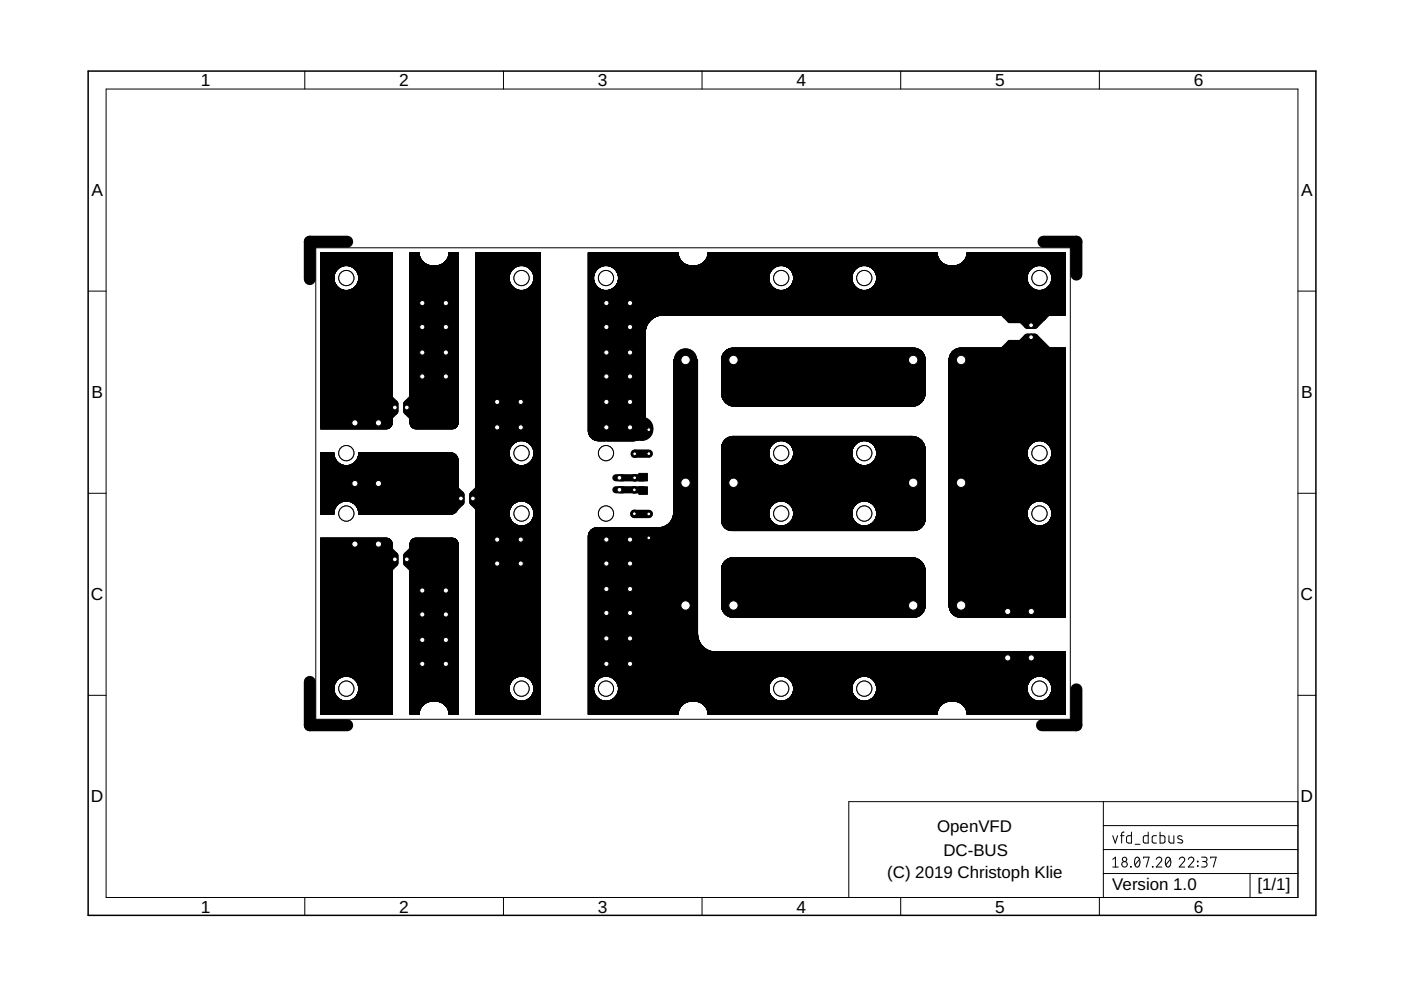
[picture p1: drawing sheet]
<svg xmlns="http://www.w3.org/2000/svg" width="297mm" height="210mm" viewBox="0 0 297 210" stroke-linecap="round" stroke-linejoin="round" font-family="sans-serif">
<defs><g id="words">
<g font-size="3.7">
<text x="42.5" y="18.3">1</text>
<text x="84.7" y="18.3">2</text>
<text x="126.8" y="18.3">3</text>
<text x="168.9" y="18.3">4</text>
<text x="211" y="18.3">5</text>
<text x="253.1" y="18.3">6</text>
<text x="19.4" y="41.6">A</text>
<text x="275.9" y="41.6">A</text>
<text x="19.4" y="84.4">B</text>
<text x="275.9" y="84.4">B</text>
<text x="19.3" y="127.3">C</text>
<text x="275.8" y="127.3">C</text>
<text x="19.3" y="170.1">D</text>
<text x="275.8" y="170.1">D</text>
<text x="42.5" y="193.5">1</text>
<text x="84.7" y="193.5">2</text>
<text x="126.8" y="193.5">3</text>
<text x="168.9" y="193.5">4</text>
<text x="211" y="193.5">5</text>
<text x="253.1" y="193.5">6</text>
</g>
<g font-size="3.6">
<text x="198.7" y="176.3">OpenVFD</text>
<text x="200" y="181.4">DC-BUS</text>
<text x="188.1" y="186.2">(C) 2019 Christoph Klie</text>
<text x="235.8" y="188.7">Version 1.0</text>
<text x="266.6" y="188.7">[1/1]</text>
</g>
</g></defs>
<g fill="none" stroke="#000" stroke-width=".51">
<circle cx="73.4" cy="58.9" r=".76"/>
<circle cx="110.6" cy="58.9" r=".76"/>
<circle cx="128.5" cy="58.9" r=".76"/>
<circle cx="165.6" cy="58.9" r=".76"/>
<circle cx="183.2" cy="58.9" r=".76"/>
<circle cx="220.4" cy="58.9" r=".76"/>
<circle cx="73.4" cy="96.1" r=".76"/>
<circle cx="110.6" cy="96.1" r=".76"/>
<circle cx="128.5" cy="96.1" r=".76"/>
<circle cx="165.6" cy="96.1" r=".76"/>
<circle cx="183.2" cy="96.1" r=".76"/>
<circle cx="220.4" cy="96.1" r=".76"/>
<circle cx="73.4" cy="108.9" r=".76"/>
<circle cx="110.6" cy="108.9" r=".76"/>
<circle cx="128.5" cy="108.9" r=".76"/>
<circle cx="165.6" cy="108.9" r=".76"/>
<circle cx="183.2" cy="108.9" r=".76"/>
<circle cx="220.4" cy="108.9" r=".76"/>
<circle cx="73.4" cy="146" r=".76"/>
<circle cx="110.6" cy="146" r=".76"/>
<circle cx="128.5" cy="146" r=".76"/>
<circle cx="165.6" cy="146" r=".76"/>
<circle cx="183.2" cy="146" r=".76"/>
<circle cx="220.4" cy="146" r=".76"/>
</g>
<path d="M213.9 72.2h3.2v1.8h-3.2zM213.9 66.6h3.2v1.8h-3.2zM81.3 81.7h1.9v3.2h-1.9zM86.9 81.7h1.9v3.2h-1.9zM95.3 100.9h1.8v3.2h-1.8zM100.9 100.9h1.8v3.2h-1.8zM135.4 100.4h1.9v1.6h-1.9zM135.4 103.2h1.9v1.6h-1.9zM81.3 120.1h1.9v3.2h-1.9zM86.9 120.1h1.9v3.2h-1.9z" fill="#000" stroke="#000" stroke-width=".21"/>
<path d="M133.3 64.3l.3 .2v26.1h-5v-26.3h75.2M145.4 76.3v59.7l-4.8 4.8M155.5 76.3h38.1M203.8 76.3v52.1h19M155.5 102.4h38.1M155.5 128.4h38.1M133.3 140.8h83.5M217.8 140.8h5" fill="none" stroke="#000" stroke-width="5"/>
<g fill="none" stroke="#000" stroke-width=".21">
<path d="M68 60h3M68 59.9l3 .1M68 59.9h3M68 59.8h3M68 59.8h2.9M68 59.7l2.9 .1M68 59.7h2.9M68 59.6h2.9M68 59.5h2.9M68 59.5h2.8M68 59.4h2.8M68 59.3h2.8"/>
<path d="M68 59.2h2.8M68 59.1h2.8M68 59h2.8M68 58.9h2.8M68 58.8h2.8M68 58.7h2.8M68 58.6h2.8M68 58.5h2.8M68 58.4h2.8M68 58.2h2.9M68 58.1h2.9M68 58h3"/>
<path d="M68 57.6h3.2M68 57.4h3.2M68 57.3h3.3M68 56.3h15.1M68 56.2h15.1M68 56.1h15.1M68 56h15.1M68 55.9h15.1M68 55.8h15.1M68 55.7h15.1M68 55.6h15.1M68 55.5h15.1"/>
<path d="M68 55.4h15.1M68 55.3h15.1M68 55.2h15.1M68 55.1h15.1M68 55h15.1M68 54.9h15.1M68 54.8h15.1M68 54.7h15.1M68 54.6h15.1M68 54.5h15.1M68 54.4h15.1M68 54.3h15.1"/>
<path d="M68 54.2h15.1M68 54.1h15.1M68 54h15.1M68 53.9h15.1M68 53.8h15.1M68 53.7h15.1M68 53.6h15.1M70.8 58.6v.7M70.8 59.3l.2 .7M70.8 58.4l-2.8 .1M70.9 58.3l-2.9 .1M70.9 58.3h-2.9"/>
<path d="M70.9 58.1l-2.9 .1M71 57.9l-.2 .7M71 60l.3 .6M71 58h-3M71 57.9h-3M71.1 57.8h-3.1M71.1 57.7h-3.1M71.2 57.6h-3.2M71.2 57.5h-3.2M71.3 57.4h-3.3M71.3 57.3l-.3 .6M71.4 57.3h-3.4"/>
<path d="M71.4 57.2l-3.4 .1M71.5 57.2h-3.5M71.5 57.1h-3.5M71.6 57.1h-3.6M71.6 57h-3.6M71.7 57h-3.7M71.7 56.9h-3.7M71.8 56.9h-3.8M71.8 56.9l-.5 .4M71.9 56.8h-3.9M72 56.7l-4 .1M72.1 56.7h-4.1"/>
<path d="M72.2 56.6l-4.2 .1M72.2 56.6h-4.2M72.3 56.5l-4.3 .1M72.4 56.5h-4.4M72.7 56.4l-4.7 .1M72.9 56.4h-4.9M73.1 56.3l-1.3 .6M73.8 56.3l.6 .2M74 56.4h9.1M74.2 56.4h8.9M74.4 56.5h8.7M74.4 56.5l.6 .4"/>
<path d="M74.5 56.5h8.6M74.6 56.6h8.5M74.7 56.6h8.4M74.8 56.7h8.3M74.9 56.7h8.2M75 56.8h8.1M75 56.9l.5 .4M75.1 56.9h8M75.1 57h8M75.2 57h7.9M75.3 57.1h7.8M75.4 57.2h7.7"/>
<path d="M75.5 57.3h7.6M75.5 57.3l.6 1.3M75.6 57.4h7.5M75.6 57.5h7.5M75.6 57.6h7.5M75.7 57.6h7.4M75.7 57.7h7.4M75.8 57.8h7.3M75.8 57.9h7.3M75.9 60h7.2M75.9 57.9h7.2M75.9 59.9h7.2"/>
<path d="M75.9 58h7.2M75.9 59.8h7.2M75.9 58.1h7.2M75.9 59.7h7.2M75.9 58.2h7.2M76 59.6h7.1M76 58.3h7.1M76 59.5h7.1M76 59.4h7.1M76 58.4h7.1M76 58.5h7.1M76.1 58.6v.7"/>
<path d="M76.1 59.3l-.6 1.3M76.1 59.3h7M76.1 59.2h7M76.1 59.1h7M76.1 59h7M76.1 58.9h7M76.1 58.8h7M76.1 58.7h7M76.1 58.6h7M83.1 56.3l-15.1 .1M87 56.3h10.1M87 60h10.1"/>
<path d="M87 59.9h10.1M87 59.8h10.1M87 59.7h10.1M87 59.6h10.1M87 59.5h10.1M87 59.4h10.1M87 59.3h10.1M87 59.2h10.1M87 59.1h10.1M87 59h10.1M87 58.9h10.1M87 58.8h10.1"/>
<path d="M87 58.7h10.1M87 58.6h10.1M87 58.5h10.1M87 58.4h10.1M87 58.3h10.1M87 58.2h10.1M87 58.1h10.1M87 58h10.1M87 57.9h10.1M87 57.8h10.1M87 57.7h10.1M87 57.6h10.1"/>
<path d="M87 57.5h10.1M87 57.4h10.1M87 57.3h10.1M87 57.2h10.1M87 57.1h10.1M87 57h10.1M87 56.9h10.1M87 56.8h10.1M87 56.7h10.1M87 56.6h10.1M87 56.5h10.1M87 56.4h10.1"/>
<path d="M87 56.3h4.2M87 56.2l4 .1M87 56.2h3.8M87 56.1l3.7 .1M87 56.1h3.5M87 56h3.4M87 56h3.3M87 55.9h3.3M87 55.9h3.1M87 55.8h3.1M87 55.8h3M87 55.7h2.9"/>
<path d="M87 55.6l2.9 .1M87 55.6h2.8M87 55.5l2.7 .1M87 55.5h2.7M87 55.4l2.6 .1M87 55.4h2.6M87 55.3l2.5 .1M87 55.3h2.5M87 55.2h2.5M87 55.2h2.4M87 55.1h2.4M87 55.1h2.3"/>
<path d="M87 55h2.3l.2 .4M87 54.9l2.3 .1M87 54.9h2.2M87 54.8l2.2 .1M87 54.8h2.2M87 54.7l2.2 .1M87 54.6l2.1 .1M87 54.6h2.1M87 54.5h2M87 54.4h2M87 54.3l2 .1M87 54.3h1.9"/>
<path d="M87 54.2h1.9M87 54.1h1.9M87 54h1.9M87 53.9h1.9M87 53.8h1.9M87 53.7h1.9M87 53.7h1.8M87 53.6h1.8M88.9 53.9l-.1-.3h-1.8v36.1M88.9 53.9h.1M88.9 53.9v.4M88.9 54.3h.1"/>
<path d="M88.9 54.3l.2 .4M89.1 54.7h-2.1M89.1 54.7h.1M89.1 54.7l.2 .3M89.3 55v.1M89.3 55h.1M89.5 55.4l.4 .3M89.5 55.4h.1M89.8 55.6l.3 .3M90.1 55.9h.1M90.2 55.9l.3 .2M90.5 56.1h.1"/>
<path d="M90.5 56.1l.4 .1M90.9 56.2v.1M90.9 56.2l.8 .2M92.3 56.3l.1 .1M92.4 56.3v.1M92.8 56.3h-.4M92.8 56.3h.1M92.8 56.3h4.3M93 56.3h4.1M93.2 56.2h3.9M93.3 56.2h3.8M93.5 56.1h3.6"/>
<path d="M93.5 56.1l-.7 .2M93.5 56.1h.1M93.6 56h3.5M93.7 56h3.4M93.8 55.9h3.3M93.9 55.9h3.2M93.9 55.9l-.3 .2M94 55.8h3.1M94.1 55.7h3M94.2 55.7h2.9M94.2 55.6l-.3 .3M94.2 55.6l.1 .1"/>
<path d="M94.3 55.6h2.8M94.4 55.5h2.7M94.5 55.4h2.6M94.5 55.4h.1M94.5 55.3h2.6M94.5 55.4l-.3 .2M94.6 55.3h2.5M94.6 55.2h2.5M94.7 55.1h2.4M94.8 55h2.3M94.8 55l-.3 .4M94.8 55v.1"/>
<path d="M94.8 55h.1M94.8 54.9h2.3M94.9 54.8h2.2M94.9 54.7h2.2M95 54.7h.1M95 54.6h2.1M95 54.5h2.1M95.1 54.4h2M95.1 54.3h2M95.1 54.3l-.1 .4M95.1 54.2h2M95.1 54.1h2"/>
<path d="M95.2 54h1.9M95.2 53.9h1.9M95.2 53.9l-.1 .4M95.2 53.9v-.3h1.9v36.1M95.2 53.8h1.9M95.2 53.7h1.9M95.2 53.6h1.9M95.2 53.9h.1M97.1 54.7h-2.1l-.2 .3M100.9 53.6h13.7v97.9h-13.7zM100.9 60h7.2M100.9 59.9h7.2"/>
<path d="M100.9 59.8l7.2 .1M100.9 59.8h7.2M100.9 59.7h7.2M100.9 59.6h7.1M100.9 59.5h7.1M100.9 59.4h7.1M100.9 59.3h7M100.9 59.2h7M100.9 59.1h7M100.9 59h7M100.9 58.9h7M100.9 58.8h7"/>
<path d="M100.9 58.7h7M100.9 58.6h7M100.9 58.5h7M100.9 58.4h7.1M100.9 58.3h7.1M100.9 58.2h7.1M100.9 58.1h7.2M100.9 58h7.2M100.9 57.9h7.2M100.9 57.9h7.3M100.9 57.7h7.4M100.9 57.6h7.4"/>
<path d="M100.9 57.2h7.7M100.9 56.9h8M100.9 56.3h13.7M100.9 56.2h13.7M100.9 56.1h13.7M100.9 56h13.7M100.9 55.9h13.7M100.9 55.8h13.7M100.9 55.7h13.7M100.9 55.6h13.7M100.9 55.5h13.7M100.9 55.4h13.7"/>
<path d="M100.9 55.3h13.7M100.9 55.2h13.7M100.9 55.1h13.7M100.9 55h13.7M100.9 54.9h13.7M100.9 54.8h13.7M100.9 54.7h13.7M100.9 54.6h13.7M100.9 54.5h13.7M100.9 54.4h13.7M100.9 54.3h13.7M100.9 54.2h13.7"/>
<path d="M100.9 54.1h13.7M100.9 54h13.7M100.9 53.9h13.7M100.9 53.8h13.7M100.9 53.7h13.7M100.9 53.6h13.7M107.9 58.6l.2 1.4M108 58.5h-7.1M108 58.3l-7.1 .1M108.1 58.2h-7.2M108.1 58l-7.2 .1M108.1 57.9l-.2 .7"/>
<path d="M108.1 60l.4 .6M108.2 57.8h-7.3M108.2 57.7h-7.3M108.3 57.6h-7.4M108.4 57.5h-7.5M108.4 57.4l-7.5 .1M108.4 57.4h-7.5M108.5 57.3l-7.6 .1M108.5 57.3l-.4 .6M108.5 57.3h-7.6M108.6 57.2h-7.7M108.7 57.1h-7.8"/>
<path d="M108.8 57h-7.9M108.9 56.9h-8M108.9 56.9l-.4 .4M109 56.8h-8.1M109.1 56.7l-8.2 .1M109.2 56.7h-8.3M109.3 56.6l-8.4 .1M109.4 56.6h-8.5M109.5 56.5l-8.6 .1M109.6 56.5h-8.7M109.6 56.5l-.7 .4M109.8 56.4l-8.9 .1"/>
<path d="M110 56.4h-9.1M110.2 56.3l-.6 .2M110.9 56.3l.7 .2M111.1 56.4h3.5M111.3 56.4h3.3M111.6 56.5h3M111.6 56.5l.6 .4M111.8 56.6h2.8M111.9 56.7h2.7M112 56.7h2.6M112.1 56.8h2.5M112.2 56.9h2.4"/>
<path d="M112.2 56.9l.5 .4M112.3 57h2.3M112.4 57h2.2M112.4 57.1h2.2M112.5 57.1h2.1M112.5 57.2h2.1M112.6 57.2h2M112.6 57.3h2M112.7 57.3h1.9M112.7 57.3l.3 .6M112.7 57.4h1.9M112.8 57.5h1.8"/>
<path d="M112.8 57.6h1.8M112.9 57.7h1.7M112.9 57.8h1.7M113 57.9h1.6M113 59.9h1.6M113 57.9l.2 .7M113 60l-.3 .6M113 58h1.6M113.1 59.8h1.5M113.1 58.1h1.5M113.1 59.7h1.5M113.1 59.6h1.5"/>
<path d="M113.1 58.2h1.5M113.1 58.3h1.5M113.1 59.5h1.5M113.1 58.4h1.5M113.2 59.4h1.4M113.2 58.4h1.4M113.2 59.3h1.4M113.2 58.5h1.4M113.2 59.2h1.4M113.2 59.1h1.4M113.2 59h1.4M113.2 58.9h1.4"/>
<path d="M113.2 58.8h1.4M113.2 58.7h1.4M113.2 58.6h1.4M113.2 58.6l-.2 1.4M114.6 56.3l-13.7 .1M124.7 53.8l19.1 .1-.1-.3h-19v37.6M124.7 60h1.4M124.7 59.9h1.3M124.7 59.8h1.3M124.7 59.7h1.3M124.7 59.6h1.3M124.7 59.6h1.2"/>
<path d="M124.7 59.5h1.2M124.7 59.4h1.2M124.7 59.3h1.2M124.7 59.2h1.2M124.7 59.1h1.2M124.7 59h1.2M124.7 58.9h1.2M124.7 58.8h1.2M124.7 58.7h1.2M124.7 58.6h1.2M124.7 58.5h1.2M124.7 58.4h1.2"/>
<path d="M124.7 58.3h1.2M124.7 58.2h1.3M124.7 58.1h1.3M124.7 58h1.3M124.7 57.9h1.4M124.7 57.8h1.4M124.7 57.2h1.8M124.7 56.9h2.1M124.7 56.3h21.4M124.7 56.2l21.2 .1M124.7 56.2h21M124.7 56.1l20.9 .1"/>
<path d="M124.7 56.1h20.8l.3 .1M124.7 56h20.7M124.7 56h20.5M124.7 55.9h20.5M124.7 55.9h20.4M124.7 55.8h20.3M124.7 55.8h20.2M124.7 55.7h20.1M124.7 55.6h20.1M124.7 55.6h20M124.7 55.5l20 .1M124.7 55.5h19.9"/>
<path d="M124.7 55.4l19.8 .1M124.7 55.4h19.8M124.7 55.3h19.7M124.7 55.2h19.7M124.7 55.2h19.6M124.7 55.1h19.6M124.7 55h19.5M124.7 54.9l19.5 .1M124.7 54.9h19.4M124.7 54.8l19.4 .1M124.7 54.8h19.4M124.7 54.7l19.4 .1"/>
<path d="M124.7 54.6l19.3 .1M124.7 54.6h19.3M124.7 54.5l19.3 .1M124.7 54.5h19.3M124.7 54.4h19.2M124.7 54.3h19.2M124.7 54.2h19.1M124.7 54.1h19.1M124.7 54l19.1 .1M124.7 54h19.1M124.7 53.9l19.1 .1M124.7 53.9h19.1"/>
<path d="M124.7 53.8h19.1M124.7 53.7h19.1M124.7 53.6h19.1M125.9 58.6l.1 1.4M125.9 58.5l-1.2 .1M125.9 58.4h-1.2M125.9 58.3l-1.2 .1M126 58.2l-1.3 .1M126 58.1h-1.3M126 58h-1.3M126 57.9l-1.3 .1M126 57.9l-.1 .7"/>
<path d="M126 60l.4 .6M126.1 57.8h-1.4M126.2 57.7h-1.5M126.2 57.6h-1.5M126.3 57.6h-1.6M126.3 57.5h-1.6M126.3 57.4l-1.6 .1M126.4 57.4h-1.7M126.4 57.3l-1.7 .1M126.4 57.3l-.4 .6M126.4 57.3h-1.7M126.6 57.2h-1.9"/>
<path d="M126.6 57.1h-1.9M126.7 57.1h-2M126.7 57h-2M126.8 57h-2.1M126.9 56.9h-2.2M126.9 56.9l-.5 .4M126.9 56.8h-2.2M127 56.7l-2.3 .1M127.1 56.7h-2.4M127.2 56.6l-2.5 .1M127.3 56.6h-2.6M127.4 56.5l-2.7 .1"/>
<path d="M127.5 56.5l-.6 .4M127.5 56.5h-2.8M127.7 56.4l-3 .1M127.9 56.4h-3.2M128.1 56.3l-.6 .2M128.8 56.3l.7 .2M129.1 56.4h36M129.3 56.4h35.6M129.5 56.5h35.1M129.5 56.5l.6 .4M129.6 56.5h34.9M129.7 56.6h34.7"/>
<path d="M129.8 56.6h34.6M129.9 56.7h34.4M129.9 56.7h34.3M130 56.8h34.1M130.1 56.9h33.9M130.1 56.9l.5 .4M130.2 56.9h33.8M130.2 57h33.7M130.3 57h33.6M130.3 57.1h33.5M130.4 57.1h33.3M130.4 57.2h33.3"/>
<path d="M130.5 57.2h33.1M130.5 57.3h33.1M130.6 57.3h32.9M130.6 57.3l.3 .6M130.6 57.4h32.9M130.7 57.5h32.7M130.7 57.6h32.7M130.8 57.7h32.5M130.9 57.9h32.3M130.9 60h32.3M130.9 59.9l32.3 .1M130.9 57.9l.2 .7"/>
<path d="M130.9 60l-.3 .6M131 59.9h32.2M131 58h32.2M131 59.8h32.1M131 58.1h32.1M131 59.7l32.1 .1M131 59.7h32.1M131 58.2h32.1M131 59.6h32.1M131 59.5h32.1M131 58.3h32.1M131.1 59.5h31.9"/>
<path d="M131.1 58.4h31.9M131.1 59.4h31.9M131.1 58.5h31.9M131.1 59.3h31.9M131.1 58.6l-.2 1.4M131.1 59.2h31.9M131.1 59.1h31.9M131.1 59h31.9M131.1 58.9h31.9M131.1 58.8h31.9M131.1 58.7h31.9M131.1 58.6h31.9"/>
<path d="M143.8 53.9h.1M143.8 53.9l.1 .4M143.9 54.3h.1M143.9 54.3h-19.2M143.9 54.3l.1 .4M144 54.7h.1M144 54.7h-19.3M144 54.7l.2 .3M144.2 55h.1M144.2 55l-19.5 .1M144.2 55l.2 .4M144.4 55.4l.4 .3"/>
<path d="M144.8 55.6l.3 .3M145.1 55.9h.1M145.1 55.9l.4 .2M145.8 56.2v.1M145.8 56.2l.4 .1M146.2 56.3h.1M146.2 56.3l.5 .1M147.7 56.3h-.4M147.7 56.3h.1M147.8 56.3h53.2M147.9 56.3h53M148.2 56.2h52.4"/>
<path d="M148.3 56.2h52.2M148.4 56.1h52M148.4 56.1l-.7 .2M148.5 56.1h.1M148.5 56h51.8M148.7 56h51.5M148.7 55.9h51.4M148.8 55.9h.1M148.8 55.9l-.3 .2M148.8 55.9h51.2M148.9 55.8h51M149 55.8h50.8"/>
<path d="M149 55.7h50.8M149.1 55.7h50.6M149.1 55.6l-.3 .3M149.1 55.6l.1 .1M149.2 55.6h50.4M149.2 55.6v.1M149.3 55.5h50.2M149.4 55.4h50M149.4 55.4l-.2 .2M149.5 55.3h49.8M149.5 55.2h49.8M149.6 55.1h49.6"/>
<path d="M149.7 55h.1M149.7 55h49.4M149.7 55l-.3 .4M149.7 55v.1M149.7 54.9h49.4M149.8 54.9h49.3M149.8 54.8h49.2M149.9 54.7h.1M149.9 54.7h49M149.9 54.7l-.2 .3M149.9 54.6h49M149.9 54.5h49"/>
<path d="M150 54.4h48.8M150 54.3h.1M150 54.3h48.8M150 54.2h48.8M150 54.3l-.1 .4M150.1 54.2h48.7M150.1 54.1h48.7M150.1 54h48.6M150.1 53.9h.1M150.1 53.9v-.3h48.6v.3M150.1 53.9h48.6M150.1 53.8h48.6"/>
<path d="M150.1 53.9l-.1 .4M150.1 53.7h48.6M150.1 53.6h48.6M163 58.6l.2 1.4 .3 .6M163 58.5l-31.9 .1M163.1 58.3h-32.1M163.1 58.2l-32.1 .1M163.2 58h-32.2M163.3 57.8h-32.4M163.3 57.7h-32.5M163.5 57.4l-32.8 .1M163.5 57.3l-.5 1.3"/>
<path d="M164 56.9l-.5 .4M164.6 56.5l-.6 .4M165.3 56.3l-.7 .2M166 56.3l.6 .2M166.2 56.4h16.5M166.4 56.4h16.1M166.6 56.5h15.6M166.6 56.5l1.1 .8M166.7 56.5h15.5M166.8 56.6h15.3M166.9 56.6h15.1M167 56.7h14.9"/>
<path d="M167.1 56.7h14.7M167.2 56.8h14.5M167.3 56.9h14.3M167.3 57h14.2M167.4 57h14.1M167.5 57.1h13.9M167.5 57.1h13.8M167.6 57.2h13.7M167.7 57.3h13.5M167.7 57.3h13.4M167.7 57.3l.4 .6M167.8 57.4h13.3"/>
<path d="M167.8 57.5h13.3M167.9 57.6h13.1M167.9 57.7h13.1M167.9 57.7h13M168 57.8h12.9M168 57.9h12.8M168.1 60h12.7M168.1 57.9h12.7M168.1 59.9h12.7M168.1 58h12.7M168.1 57.9l.2 .7M168.1 60l-.4 .6"/>
<path d="M168.1 59.8h12.7M168.1 59.8h12.6M168.1 58.1h12.6M168.1 59.7h12.6M168.1 58.2h12.6M168.2 59.6h12.5M168.2 58.3h12.5M168.2 59.5h12.5M168.2 59.4h12.5M168.2 58.4h12.5M168.2 59.4h12.4M168.2 58.5h12.4"/>
<path d="M168.3 58.6v.7M168.3 59.3h12.3M168.3 59.2h12.3M168.3 59.1h12.3M168.3 59h12.3M168.3 58.9h12.3M168.3 58.8h12.3M168.3 58.7h12.3M168.3 58.6h12.3M168.3 59.3l-.2 .7M180.6 58.6v.7M180.6 59.3l.2 .7"/>
<path d="M180.7 58.4h-12.5M180.8 58.1h-12.7M180.8 57.9l-.2 .7M180.8 60l.3 .6M181.1 57.4l-13.3 .1M181.1 57.3l-.3 .6M181.6 56.9l-.5 .4M182.2 56.5l-.6 .4M182.9 56.3l-.7 .2M183.6 56.3l.7 .2M183.8 56.4h36M184 56.4h35.6"/>
<path d="M184.3 56.5h35.1M184.3 56.5l1 .8M184.3 56.5h35M184.4 56.6h34.8M184.5 56.6h34.6M184.6 56.7h34.4M184.7 56.7h34.2M184.8 56.8h34M184.9 56.9h33.9M184.9 56.9h33.8M185 57h33.7M185 57h33.6"/>
<path d="M185.2 57.2h33.2M185.3 57.2h33.1M185.3 57.3h33M185.3 57.3l.4 .6M185.4 57.4h32.8M185.4 57.5h32.8M185.5 57.6h32.7M185.5 57.6h32.6M185.5 57.7h32.6M185.6 57.7h32.5M185.6 57.8h32.4M185.7 57.9h32.3"/>
<path d="M185.7 60h32.2M185.7 59.9h32.2M185.7 58h32.2M185.7 57.9l.2 .7M185.7 60l-.4 .6M185.7 59.8h32.2M185.7 58.1h32.2M185.8 59.7h32.1M185.8 58.2h32.1M185.8 59.6h32M185.8 58.3h32M185.8 58.2h32"/>
<path d="M185.8 59.5h32M185.8 59.4h32M185.8 58.4h32M185.8 58.5h32M185.9 58.6v.7M185.9 59.3h31.9M185.9 59.2h31.9M185.9 59.1h31.9M185.9 59h31.9M185.9 58.9h31.9M185.9 58.8h31.9M185.9 58.7h31.9"/>
<path d="M185.9 58.6h31.9M185.9 58.5h31.9M185.9 59.3l-.2 .7M198.7 53.9h.1M198.7 53.9l.1 .4M198.8 54.3h.1M198.8 54.3h-48.8M198.8 54.3l.1 .4M198.9 54.7h.1M198.9 54.7h-49M198.9 54.7l.2 .3M199.1 55h.1"/>
<path d="M199.1 55l.1 .1M199.1 55l.3 .4M199.4 55.4l.3 .3M199.4 55.4h-50M199.4 55.4h.1M199.7 55.6l.3 .3M200 55.9h.1M200 55.9l.3 .2M200.3 56.1h.1M200.4 56.1l.3 .1M200.7 56.2l.1 .1M200.7 56.2l.9 .2"/>
<path d="M202.2 56.3v.1M202.6 56.3h-.4M202.6 56.3h.1M202.7 56.3h23.2M202.9 56.3h23M203 56.2l-.4 .1M203 56.2v.1M203.1 56.2h22.8M203.2 56.2h22.7M203.3 56.1h22.6M203.4 56.1l-.4 .1M203.4 56.1h.1"/>
<path d="M203.5 56h22.4M203.6 56h22.3M203.6 55.9h22.3M203.7 55.9l-.3 .2M203.7 55.9h.1M203.8 55.9h22.1M203.8 55.9h.1M203.8 55.8h22.1M203.9 55.8h22M204 55.7h21.9M204.1 55.6l-.3 .3M204.1 55.6v.1"/>
<path d="M204.1 55.6h21.8M204.2 55.6h21.7M204.2 55.5h21.7M204.3 55.5h21.6M204.3 55.4h21.6M204.3 55.4l-.2 .2M204.4 55.3h21.5M204.4 55.4h.1M204.4 55.2h21.5M204.5 55.2h21.4M204.5 55.1h21.4M204.6 55.1h21.3"/>
<path d="M204.6 55h21.3M204.6 55l-.2 .4M204.6 55v.1M204.6 55h.1M204.7 54.9h21.2M204.7 54.8h21.2M204.8 54.7h21.1M204.8 54.7h.1M204.8 54.7l-.2 .3M204.8 54.6h21.1M204.9 54.5h21M204.9 54.4h21"/>
<path d="M204.9 54.3h21M204.9 54.3l-.1 .4M204.9 54.3h.1M205 54.2h20.9M205 54.3h.1M205 54.1h20.9M205 54h20.9M205 53.9h20.9M205 53.9l.1-.3h20.8v13.2h-101.2M205 53.9h.1M205 53.8h20.9M205 53.7h20.9"/>
<path d="M205 53.6h20.9M205 53.9v.4M205.1 53.6h20.8M217.8 58.6v.7M217.8 59.3l.1 .7M217.9 57.9l-.1 .7M217.9 60l.4 .6M218.3 57.3l-.4 .6M218.5 57.1h-33.4M219.4 56.5l-1.1 .8M220 56.3l-.6 .2M220.7 56.3l.7 .2"/>
<path d="M221 56.4h4.9M221.1 56.4h4.8M221.4 56.5h4.5M221.4 56.5l.6 .4M221.5 56.5h4.4M221.6 56.6h4.3M221.7 56.7h4.2M221.8 56.7h4.1M221.9 56.8h4M222 56.9h3.9M222 56.9l.5 .4M222.1 56.9h3.8"/>
<path d="M222.1 57h3.8M222.2 57h3.7M222.2 57.1h3.7M222.3 57.1h3.6M222.3 57.2h3.6M222.4 57.2h3.5M222.4 57.3h3.5M222.5 57.3h3.4M222.5 57.3l.3 .6M222.5 57.4h3.4M222.6 57.5h3.3M222.6 57.6h3.3"/>
<path d="M222.7 57.7h3.2M222.7 57.8h3.2M222.8 57.8h3.1M222.8 57.9h3.1M222.8 60h3.1M222.8 59.9h3.1M222.8 58h3.1M222.8 57.9l.2 .7M222.8 60l-.3 .6M222.9 59.8h3M222.9 58.1h3M222.9 58h3"/>
<path d="M222.9 59.7h3M222.9 59.6h3M222.9 58.2h3M222.9 58.3h3M222.9 59.5h3M222.9 58.4h3M223 59.5h2.9M223 59.4h2.9M223 58.4h2.9M223 59.3h2.9M223 58.5h2.9M223 58.6v.7"/>
<path d="M223 59.2h2.9M223 59.1h2.9M223 59h2.9M223 58.9h2.9M223 58.8h2.9M223 58.7h2.9M223 58.6h2.9M223 59.3l-.2 .7M225.9 56.3l-101.2 .1M68 76.3h15.1M68 80h15.1M68 79.9h15.1"/>
<path d="M68 79.8h15.1M68 79.7h15.1M68 79.6h15.1M68 79.5h15.1M68 79.4h15.1M68 79.3h15.1M68 79.2h15.1M68 79.1h15.1M68 79h15.1M68 78.9h15.1M68 78.8h15.1M68 78.7h15.1"/>
<path d="M68 78.6h15.1M68 78.5h15.1M68 78.4h15.1M68 78.3h15.1M68 78.2h15.1M68 78.1h15.1M68 78h15.1M68 77.9h15.1M68 77.8h15.1M68 77.7h15.1M68 77.6h15.1M68 77.5h15.1"/>
<path d="M68 77.4h15.1M68 77.3h15.1M68 77.2h15.1M68 77.1h15.1M68 77h15.1M68 76.9h15.1M68 76.8h15.1M68 76.7h15.1M68 76.6h15.1M68 76.5h15.1M68 76.4h15.1M68 73.8h15.1"/>
<path d="M68 76.2h15.1M68 76.1h15.1M68 76h15.1M68 75.9h15.1M68 75.8h15.1M68 75.7h15.1M68 75.6h15.1M68 75.5h15.1M68 75.4h15.1M68 75.3h15.1M68 75.2h15.1M68 75.1h15.1"/>
<path d="M68 75h15.1M68 74.9h15.1M68 74.8h15.1M68 74.7h15.1M68 74.6h15.1M68 74.5h15.1M68 74.4h15.1M68 74.3h15.1M68 74.2h15.1M68 74.1h15.1M68 74h15.1M68 73.9h15.1"/>
<path d="M68 61.6h15.1M68 73.7h15.1M68 73.6h15.1M68 73.5h15.1M68 73.4h15.1M68 73.3h15.1M68 73.2h15.1M68 73.1h15.1M68 73h15.1M68 72.9h15.1M68 72.8h15.1M68 72.7h15.1"/>
<path d="M68 72.6h15.1M68 72.5h15.1M68 72.4h15.1M68 72.3h15.1M68 72.2h15.1M68 72.1h15.1M68 72h15.1M68 71.9h15.1M68 71.8h15.1M68 71.7h15.1M68 71.6h15.1M68 71.5h15.1"/>
<path d="M68 71.4h15.1M68 71.3h15.1M68 71.2h15.1M68 71.1h15.1M68 71h15.1M68 70.9h15.1M68 70.8h15.1M68 70.7h15.1M68 70.6h15.1M68 70.5h15.1M68 70.4h15.1M68 70.3h15.1"/>
<path d="M68 70.2h15.1M68 70.1h15.1M68 70h15.1M68 69.9h15.1M68 69.8h15.1M68 69.7h15.1M68 69.6h15.1M68 69.5h15.1M68 69.4h15.1M68 69.3h15.1M68 69.2h15.1M68 69.1h15.1"/>
<path d="M68 69h15.1M68 68.9h15.1M68 68.8h15.1M68 68.7h15.1M68 68.6h15.1M68 68.5h15.1M68 68.4h15.1M68 68.3h15.1M68 68.2h15.1M68 68.1h15.1M68 68h15.1M68 67.9h15.1"/>
<path d="M68 67.8h15.1M68 67.7h15.1M68 67.6h15.1M68 67.5h15.1M68 67.4h15.1M68 67.3h15.1M68 67.2h15.1M68 67.1h15.1M68 67h15.1M68 66.9h15.1M68 66.8h15.1M68 66.7h15.1"/>
<path d="M68 66.6h15.1M68 66.5h15.1M68 66.4h15.1M68 66.3h15.1M68 66.2h15.1M68 66.1h15.1M68 66h15.1M68 65.9h15.1M68 65.8h15.1M68 65.7h15.1M68 65.6h15.1M68 65.5h15.1"/>
<path d="M68 65.4h15.1M68 65.3h15.1M68 65.2h15.1M68 65.1h15.1M68 65h15.1M68 64.9h15.1M68 64.8h15.1M68 64.7h15.1M68 64.6h15.1M68 64.5h15.1M68 64.4h15.1M68 64.3h15.1"/>
<path d="M68 64.2h15.1M68 64.1h15.1M68 64h15.1M68 63.9h15.1M68 63.8h15.1M68 63.7h15.1M68 63.6h15.1M68 63.5h15.1M68 63.4h15.1M68 63.3h15.1M68 63.2h15.1M68 63.1h15.1"/>
<path d="M68 63h15.1M68 62.9h15.1M68 62.8h15.1M68 62.7h15.1M68 62.6h15.1M68 62.5h15.1M68 62.4h15.1M68 62.3h15.1M68 62.2h15.1M68 62.1h15.1M68 62h15.1M68 61.9h15.1"/>
<path d="M68 61.8h15.1M68 61.7h15.1M68 61.5l5 .1M68 61.5h4.8M68 61.4h4.6M68 61.4h4.5M68 61.3h4.3M68 61.2h4.2M68 61.2h4.1M68 61.1h3.9M68 61l3.9 .1M68 61h3.8"/>
<path d="M68 60.9l3.8 .1M68 60.9h3.7M68 60.8l3.6 .1M68 60.8h3.6M68 60.7l3.5 .1M68 60.7h3.5M68 60.6l3.4 .1M68 60.6h3.4M68 60.5l3.3 .1M68 60.5h3.3M68 60.4h3.2M68 60.3l3.2 .1"/>
<path d="M68 60.3h3.2M68 60.2l3.2 .1M68 60.2h3.1M68 60.1l3.1 .1M68 60.1h3.1M71.3 60.6l1.1 .8 .7 .2M73.8 61.6h9.3M74 61.5h9.1M74.3 61.4h8.8M74.4 61.4h8.7M74.5 61.3h8.6M74.6 61.3h8.5"/>
<path d="M74.7 61.2h8.4M74.8 61.2h8.3M74.9 61.1h8.2M75 61.1h8.1M75.1 61h8M75.2 60.9h7.9M75.3 60.8h7.8M75.4 60.7h7.7M75.5 60.6h7.6M75.5 60.6l-1.1 .8-.6 .2M75.6 60.5h7.5M75.6 60.4h7.5"/>
<path d="M75.7 60.3h7.4M75.7 60.2h7.4M75.8 60.2h7.3M75.8 60.1h7.3M75.8 60h7.3M87 76.3h10.1M87 80h10.1M87 79.9h10.1M87 79.8h10.1M87 79.7h10.1M87 79.6h10.1M87 79.5h10.1"/>
<path d="M87 79.4h10.1M87 79.3h10.1M87 79.2h10.1M87 79.1h10.1M87 79h10.1M87 78.9h10.1M87 78.8h10.1M87 78.7h10.1M87 78.6h10.1M87 78.5h10.1M87 78.4h10.1M87 78.3h10.1"/>
<path d="M87 78.2h10.1M87 78.1h10.1M87 78h10.1M87 77.9h10.1M87 77.8h10.1M87 77.7h10.1M87 77.6h10.1M87 77.5h10.1M87 77.4h10.1M87 77.3h10.1M87 77.2h10.1M87 77.1h10.1"/>
<path d="M87 77h10.1M87 76.9h10.1M87 76.8h10.1M87 76.7h10.1M87 76.6h10.1M87 76.5h10.1M87 76.4h10.1M87 73.8h10.1M87 76.2h10.1M87 76.1h10.1M87 76h10.1M87 75.9h10.1"/>
<path d="M87 75.8h10.1M87 75.7h10.1M87 75.6h10.1M87 75.5h10.1M87 75.4h10.1M87 75.3h10.1M87 75.2h10.1M87 75.1h10.1M87 75h10.1M87 74.9h10.1M87 74.8h10.1M87 74.7h10.1"/>
<path d="M87 74.6h10.1M87 74.5h10.1M87 74.4h10.1M87 74.3h10.1M87 74.2h10.1M87 74.1h10.1M87 74h10.1M87 73.9h10.1M87 61.6h10.1M87 73.7h10.1M87 73.6h10.1M87 73.5h10.1"/>
<path d="M87 73.4h10.1M87 73.3h10.1M87 73.2h10.1M87 73.1h10.1M87 73h10.1M87 72.9h10.1M87 72.8h10.1M87 72.7h10.1M87 72.6h10.1M87 72.5h10.1M87 72.4h10.1M87 72.3h10.1"/>
<path d="M87 72.2h10.1M87 72.1h10.1M87 72h10.1M87 71.9h10.1M87 71.8h10.1M87 71.7h10.1M87 71.6h10.1M87 71.5h10.1M87 71.4h10.1M87 71.3h10.1M87 71.2h10.1M87 71.1h10.1"/>
<path d="M87 71h10.1M87 70.9h10.1M87 70.8h10.1M87 70.7h10.1M87 70.6h10.1M87 70.5h10.1M87 70.4h10.1M87 70.3h10.1M87 70.2h10.1M87 70.1h10.1M87 70h10.1M87 69.9h10.1"/>
<path d="M87 69.8h10.1M87 69.7h10.1M87 69.6h10.1M87 69.5h10.1M87 69.4h10.1M87 69.3h10.1M87 69.2h10.1M87 69.1h10.1M87 69h10.1M87 68.9h10.1M87 68.8h10.1M87 68.7h10.1"/>
<path d="M87 68.6h10.1M87 68.5h10.1M87 68.4h10.1M87 68.3h10.1M87 68.2h10.1M87 68.1h10.1M87 68h10.1M87 67.9h10.1M87 67.8h10.1M87 67.7h10.1M87 67.6h10.1M87 67.5h10.1"/>
<path d="M87 67.4h10.1M87 67.3h10.1M87 67.2h10.1M87 67.1h10.1M87 67h10.1M87 66.9h10.1M87 66.8h10.1M87 66.7h10.1M87 66.6h10.1M87 66.5h10.1M87 66.4h10.1M87 66.3h10.1"/>
<path d="M87 66.2h10.1M87 66.1h10.1M87 66h10.1M87 65.9h10.1M87 65.8h10.1M87 65.7h10.1M87 65.6h10.1M87 65.5h10.1M87 65.4h10.1M87 65.3h10.1M87 65.2h10.1M87 65.1h10.1"/>
<path d="M87 65h10.1M87 64.9h10.1M87 64.8h10.1M87 64.7h10.1M87 64.6h10.1M87 64.5h10.1M87 64.4h10.1M87 64.3h10.1M87 64.2h10.1M87 64.1h10.1M87 64h10.1M87 63.9h10.1"/>
<path d="M87 63.8h10.1M87 63.7h10.1M87 63.6h10.1M87 63.5h10.1M87 63.4h10.1M87 63.3h10.1M87 63.2h10.1M87 63.1h10.1M87 63h10.1M87 62.9h10.1M87 62.8h10.1M87 62.7h10.1"/>
<path d="M87 62.6h10.1M87 62.5h10.1M87 62.4h10.1M87 62.3h10.1M87 62.2h10.1M87 62.1h10.1M87 62h10.1M87 61.9h10.1M87 61.8h10.1M87 61.7h10.1M87 61.5h10.1M87 61.4h10.1"/>
<path d="M87 61.3h10.1M87 61.2h10.1M87 61.1h10.1M87 61h10.1M87 60.9h10.1M87 60.8h10.1M87 60.7h10.1M87 60.6h10.1M87 60.5h10.1M87 60.4h10.1M87 60.3h10.1M87 60.2h10.1"/>
<path d="M87 60.1h10.1M100.9 76.3h13.7M100.9 80h13.7M100.9 79.9h13.7M100.9 79.8h13.7M100.9 79.7h13.7M100.9 79.6h13.7M100.9 79.5h13.7M100.9 79.4h13.7M100.9 79.3h13.7M100.9 79.2h13.7M100.9 79.1h13.7"/>
<path d="M100.9 79h13.7M100.9 78.9h13.7M100.9 78.8h13.7M100.9 78.7h13.7M100.9 78.6h13.7M100.9 78.5h13.7M100.9 78.4h13.7M100.9 78.3h13.7M100.9 78.2h13.7M100.9 78.1h13.7M100.9 78h13.7M100.9 77.9h13.7"/>
<path d="M100.9 77.8h13.7M100.9 77.7h13.7M100.9 77.6h13.7M100.9 77.5h13.7M100.9 77.4h13.7M100.9 77.3h13.7M100.9 77.2h13.7M100.9 77.1h13.7M100.9 77h13.7M100.9 76.9h13.7M100.9 76.8h13.7M100.9 76.7h13.7"/>
<path d="M100.9 76.6h13.7M100.9 76.5h13.7M100.9 76.4h13.7M100.9 73.8h13.7M100.9 76.2h13.7M100.9 76.1h13.7M100.9 76h13.7M100.9 75.9h13.7M100.9 75.8h13.7M100.9 75.7h13.7M100.9 75.6h13.7M100.9 75.5h13.7"/>
<path d="M100.9 75.4h13.7M100.9 75.3h13.7M100.9 75.2h13.7M100.9 75.1h13.7M100.9 75h13.7M100.9 74.9h13.7M100.9 74.8h13.7M100.9 74.7h13.7M100.9 74.6h13.7M100.9 74.5h13.7M100.9 74.4h13.7M100.9 74.3h13.7"/>
<path d="M100.9 74.2h13.7M100.9 74.1h13.7M100.9 74h13.7M100.9 73.9h13.7M100.9 61.6h13.7M100.9 73.7h13.7M100.9 73.6h13.7M100.9 73.5h13.7M100.9 73.4h13.7M100.9 73.3h13.7M100.9 73.2h13.7M100.9 73.1h13.7"/>
<path d="M100.9 73h13.7M100.9 72.9h13.7M100.9 72.8h13.7M100.9 72.7h13.7M100.9 72.6h13.7M100.9 72.5h13.7M100.9 72.4h13.7M100.9 72.3h13.7M100.9 72.2h13.7M100.9 72.1h13.7M100.9 72h13.7M100.9 71.9h13.7"/>
<path d="M100.9 71.8h13.7M100.9 71.7h13.7M100.9 71.6h13.7M100.9 71.5h13.7M100.9 71.4h13.7M100.9 71.3h13.7M100.9 71.2h13.7M100.9 71.1h13.7M100.9 71h13.7M100.9 70.9h13.7M100.9 70.8h13.7M100.9 70.7h13.7"/>
<path d="M100.9 70.6h13.7M100.9 70.5h13.7M100.9 70.4h13.7M100.9 70.3h13.7M100.9 70.2h13.7M100.9 70.1h13.7M100.9 70h13.7M100.9 69.9h13.7M100.9 69.8h13.7M100.9 69.7h13.7M100.9 69.6h13.7M100.9 69.5h13.7"/>
<path d="M100.9 69.4h13.7M100.9 69.3h13.7M100.9 69.2h13.7M100.9 69.1h13.7M100.9 69h13.7M100.9 68.9h13.7M100.9 68.8h13.7M100.9 68.7h13.7M100.9 68.6h13.7M100.9 68.5h13.7M100.9 68.4h13.7M100.9 68.3h13.7"/>
<path d="M100.9 68.2h13.7M100.9 68.1h13.7M100.9 68h13.7M100.9 67.9h13.7M100.9 67.8h13.7M100.9 67.7h13.7M100.9 67.6h13.7M100.9 67.5h13.7M100.9 67.4h13.7M100.9 67.3h13.7M100.9 67.2h13.7M100.9 67.1h13.7"/>
<path d="M100.9 67h13.7M100.9 66.9h13.7M100.9 66.8h13.7M100.9 66.7h13.7M100.9 66.6h13.7M100.9 66.5h13.7M100.9 66.4h13.7M100.9 66.3h13.7M100.9 66.2h13.7M100.9 66.1h13.7M100.9 66h13.7M100.9 65.9h13.7"/>
<path d="M100.9 65.8h13.7M100.9 65.7h13.7M100.9 65.6h13.7M100.9 65.5h13.7M100.9 65.4h13.7M100.9 65.3h13.7M100.9 65.2h13.7M100.9 65.1h13.7M100.9 65h13.7M100.9 64.9h13.7M100.9 64.8h13.7M100.9 64.7h13.7"/>
<path d="M100.9 64.6h13.7M100.9 64.5h13.7M100.9 64.4h13.7M100.9 64.3h13.7M100.9 64.2h13.7M100.9 64.1h13.7M100.9 64h13.7M100.9 63.9h13.7M100.9 63.8h13.7M100.9 63.7h13.7M100.9 63.6h13.7M100.9 63.5h13.7"/>
<path d="M100.9 63.4h13.7M100.9 63.3h13.7M100.9 63.2h13.7M100.9 63.1h13.7M100.9 63h13.7M100.9 62.9h13.7M100.9 62.8h13.7M100.9 62.7h13.7M100.9 62.6h13.7M100.9 62.5h13.7M100.9 62.4h13.7M100.9 62.3h13.7"/>
<path d="M100.9 62.2h13.7M100.9 62.1h13.7M100.9 62h13.7M100.9 61.9h13.7M100.9 61.8h13.7M100.9 61.7h13.7M100.9 61.5l9.3 .1M100.9 61.5h9.1M100.9 61.4h8.8M100.9 61.4h8.7M100.9 61.3h8.6M100.9 61.3h8.5"/>
<path d="M100.9 61.2h8.4M100.9 61.2h8.3M100.9 61.1h8.2M100.9 61l8.1 .1M100.9 61h8M100.9 60.9l8 .1M100.9 60.9h7.9M100.9 60.8l7.9 .1M100.9 60.8h7.8M100.9 60.7l7.8 .1M100.9 60.7h7.7M100.9 60.6l7.7 .1"/>
<path d="M100.9 60.6h7.6M100.9 60.5h7.6M100.9 60.5h7.5M100.9 60.4h7.5M100.9 60.3l7.5 .1M100.9 60.3h7.4M100.9 60.2l7.4 .1M100.9 60.2h7.4M100.9 60.1l7.3 .1M100.9 60.1h7.3M100.9 60l7.3 .1M108.5 60.6l1.1 .8 .6 .2"/>
<path d="M111 61.6h3.6M111.1 61.5h3.5M111.4 61.4h3.2M111.5 61.4h3.1M111.7 61.3h2.9M111.8 61.2h2.8M111.9 61.2h2.7M112 61.1h2.6M112.1 61.1h2.5M112.2 61h2.4M112.3 60.9h2.3M112.4 60.9h2.2"/>
<path d="M112.4 60.8h2.2M112.5 60.8h2.1M112.5 60.7h2.1M112.6 60.7h2M112.6 60.6h2M112.7 60.5h1.9M112.7 60.6l-1.1 .8-.7 .2M112.8 60.4h1.8M112.8 60.3h1.8M112.9 60.2h1.7M112.9 60.1h1.7M113 60h1.6"/>
<path d="M124.7 76.3h12.1M124.7 80h12.1M124.7 79.9h12.1M124.7 79.8h12.1M124.7 79.7h12.1M124.7 79.6h12.1M124.7 79.5h12.1M124.7 79.4h12.1M124.7 79.3h12.1M124.7 79.2h12.1M124.7 79.1h12.1M124.7 79h12.1"/>
<path d="M124.7 78.9h12.1M124.7 78.8h12.1M124.7 78.7h12.1M124.7 78.6h12.1M124.7 78.5h12.1M124.7 78.4h12.1M124.7 78.3h12.1M124.7 78.2h12.1M124.7 78.1h12.1M124.7 78h12.1M124.7 77.9h12.1M124.7 77.8h12.1"/>
<path d="M124.7 77.7h12.1M124.7 77.6h12.1M124.7 77.5h12.1M124.7 77.4h12.1M124.7 77.3h12.1M124.7 77.2h12.1M124.7 77.1h12.1M124.7 77h12.1M124.7 76.9h12.1M124.7 76.8h12.1M124.7 76.7h12.1M124.7 76.6h12.1"/>
<path d="M124.7 76.5h12.1M124.7 76.4h12.1M124.7 73.8h12.1M124.7 76.2h12.1M124.7 76.1h12.1M124.7 76h12.1M124.7 75.9h12.1M124.7 75.8h12.1M124.7 75.7h12.1M124.7 75.6h12.1M124.7 75.5h12.1M124.7 75.4h12.1"/>
<path d="M124.7 75.3h12.1M124.7 75.2h12.1M124.7 75.1h12.1M124.7 75h12.1M124.7 74.9h12.1M124.7 74.8h12.1M124.7 74.7h12.1M124.7 74.6h12.1M124.7 74.5h12.1M124.7 74.4h12.1M124.7 74.3h12.1M124.7 74.2h12.1"/>
<path d="M124.7 74.1h12.1M124.7 74h12.1M124.7 73.9h12.1M124.7 61.6h101.2M124.7 73.7h12.1M124.7 73.6h12.1M124.7 73.5h12.1M124.7 73.4h12.1M124.7 73.3h12.1M124.7 73.2h12.1M124.7 73.1h12.1M124.7 73h12.1"/>
<path d="M124.7 72.9h12.1M124.7 72.8h12.1M124.7 72.7h12.1M124.7 72.6h12.1M124.7 72.5h12.1M124.7 72.4h12.1M124.7 72.3h12.1M124.7 72.2h12.1M124.7 72.1h12.1M124.7 72h12.1M124.7 71.9h12.1M124.7 71.8h12.1"/>
<path d="M124.7 71.7h12.1M124.7 71.6h12.1M124.7 71.5h12.1M124.7 71.4h12.1M124.7 71.3h12.1M124.7 71.2h12.1M124.7 71.1h12.1M124.7 71h12.1M124.7 70.9h12.1M124.7 70.8h12.1M124.7 70.7h12.1M124.7 70.6h12.1"/>
<path d="M124.7 70.5h12.1M124.7 70.4h12.1M124.7 70.3h12.1M124.7 70.2h12.1M124.7 70.1h12.1M124.7 70h12.1M124.7 69.9h12.2M124.7 69.8h12.2M124.7 69.7h12.2M124.7 69.6h12.2M124.7 69.2h12.4M124.7 69.1h12.4"/>
<path d="M124.7 69h12.4M124.7 68.5h12.8M124.7 68.4h12.8M124.7 66.7h101.2M124.7 66.6h101.2M124.7 66.5h101.2M124.7 66.4h101.2M124.7 66.3h101.2M124.7 66.2h101.2M124.7 66.1h101.2M124.7 66h101.2M124.7 65.9h101.2"/>
<path d="M124.7 65.8h101.2M124.7 65.7h101.2M124.7 65.6h101.2M124.7 65.5h101.2M124.7 65.4h101.2M124.7 65.3h101.2M124.7 65.2h101.2M124.7 65.1h101.2M124.7 65h101.2M124.7 64.9h101.2M124.7 64.8h101.2M124.7 64.7h101.2"/>
<path d="M124.7 64.6h101.2M124.7 64.5h101.2M124.7 64.4h101.2M124.7 64.3h101.2M124.7 64.2h101.2M124.7 64.1h101.2M124.7 64h101.2M124.7 63.9h101.2M124.7 63.8h101.2M124.7 63.7h101.2M124.7 63.6h101.2M124.7 63.5h101.2"/>
<path d="M124.7 63.4h101.2M124.7 63.3h101.2M124.7 63.2h101.2M124.7 63.1h101.2M124.7 63h101.2M124.7 62.9h101.2M124.7 62.8h101.2M124.7 62.7h101.2M124.7 62.6h101.2M124.7 62.5h101.2M124.7 62.4h101.2M124.7 62.3h101.2"/>
<path d="M124.7 62.2h101.2M124.7 62.1h101.2M124.7 62h101.2M124.7 61.9h101.2M124.7 61.8h101.2M124.7 61.7h101.2M124.7 61.5l3.4 .1M124.7 61.5h3.2M124.7 61.4h3M124.7 61.4h2.8M124.7 61.3h2.7M124.7 61.3h2.6"/>
<path d="M124.7 61.2h2.5M124.7 61.2h2.4M124.7 61.1h2.3M124.7 61l2.3 .1M124.7 61h2.2M124.7 60.9l2.1 .1M124.7 60.9h2M124.7 60.8l2 .1M124.7 60.8h1.9M124.7 60.7l1.9 .1M124.7 60.7h1.8M124.7 60.6l1.8 .1"/>
<path d="M124.7 60.6h1.7M124.7 60.5h1.7M124.7 60.5h1.6M124.7 60.4h1.6M124.7 60.3l1.6 .1M124.7 60.3h1.6M124.7 60.2l1.5 .1M124.7 60.2h1.5M124.7 60.1l1.5 .1M124.7 60.1h1.4M124.7 60l1.4 .1M126.4 60.6l1.1 .8 .6 .2"/>
<path d="M128.9 61.6h36.3M129.1 61.5h36M129.3 61.4h35.5M129.5 61.4h35.2M129.6 61.3h34.9M129.8 61.2h34.6M129.9 61.2h34.4M130 61.1h34.1M130.1 61h33.9M130.2 61h33.8M130.2 60.9h33.7M130.3 60.9h33.6"/>
<path d="M130.3 60.8h33.5M130.4 60.8h33.3M130.5 60.7h33.2M130.5 60.7h33.1M130.5 60.6h33.1M130.6 60.5l32.9 .1M130.6 60.6l-1.1 .8-.7 .2M130.6 60.5h32.9M130.7 60.4h32.7M130.7 60.3h32.7M130.8 60.2h32.5M130.9 60.1h32.4"/>
<path d="M136.8 70.6v20.3M136.8 70.3h-12.1M136.8 70.1v.5M136.9 69.7l-12.2 .1M136.9 69.6l-12.2 .1M136.9 69.5l-12.2 .1M136.9 69.5l-.1 .6M137 69.5h-12.3M137 69.4h-12.3M137 69.3h-12.3M137.1 69.3h-12.4M137.1 69l-.2 .5"/>
<path d="M137.2 68.9l-12.5 .1M137.2 68.9h-12.5M137.2 68.8l-12.5 .1M137.3 68.8h-12.6M137.3 68.7l-12.6 .1M137.3 68.7h-12.6M137.4 68.6l-12.7 .1M137.4 68.6h-12.7M137.4 68.5h-12.7M137.5 68.4l-12.8 .1M137.6 68.3h-12.9M137.7 68.2h-13"/>
<path d="M137.8 68.1h-13.1M137.8 68h-13.1M137.9 67.9l-13.2 .1M138 67.9h-13.3M138 67.8l-13.3 .1M138.1 67.8h-13.4M138.1 67.7l-13.4 .1M138.2 67.7h-13.5M138.3 67.6h-13.6M138.4 67.5h-13.7M138.5 67.5h-13.8M138.5 67.4h-13.8"/>
<path d="M138.5 67.4a3.5 3.5 0 0 0-1.4 1.6M138.6 67.4h-13.9M138.7 67.3h-14M138.9 67.2l-14.2 .1M138.9 67.2h-14.2M139 67.1l-.5 .3M139 67.1l-14.3 .1M139.1 67.1h-14.4M139.3 67l-14.6 .1M139.4 67h-14.7M139.7 66.9l-15 .1M139.9 66.9h-15.2"/>
<path d="M140.4 66.8l-15.7 .1M140.6 66.8l-1.6 .3M142.8 80h5.1M142.8 79.9h5.1M142.8 79.8h5.1M142.8 79.7h5.1M142.8 79.6h5.1M142.8 79.5h5.1M142.8 79.4h5.1M142.8 79.3h5.1M142.8 79.2h5.1M142.8 79.1h5.1"/>
<path d="M142.8 79h5.1M142.8 78.9h5.1M142.8 78.8h5.1M142.8 78.7h5.1M142.8 78.6h5.1M142.8 78.5h5.1M142.8 78.4h5.1M142.8 78.3h5.1M142.8 78.2h5.1M142.8 78.1h5.1M142.8 78h5.1M142.8 77.9h5.1"/>
<path d="M142.8 77.8h5.1M142.8 77.7h5.1M142.8 77.6h5.1M142.8 77.5h5.1M142.8 77.4h5.1M142.8 77.3h5.1M142.8 77.2h5.1M142.8 77.1h5.1M142.8 77h5.1M142.8 76.9h5.1M142.8 76.8h5.1M142.8 76.7h5.1"/>
<path d="M142.8 76.6h5.1M142.8 76.5h5.1M142.8 76.4h5.1M153 76.3h43.2M153 80h43.2M153 79.9h43.2M153 79.8h43.2M153 79.7h43.2M153 79.6h43.2M153 79.5h43.2M153 79.4h43.2M153 79.3h43.2"/>
<path d="M153 79.2h43.2M153 79.1h43.2M153 79h43.2M153 78.9h43.2M153 78.8h43.2M153 78.7h43.2M153 78.6h43.2M153 78.5h43.2M153 78.4h43.2M153 78.3h43.2M153 78.2h43.2M153 78.1h43.2"/>
<path d="M153 78h43.2M153 77.9h43.2M153 77.8h43.2M153 77.7h43.2M153 77.6h43.2M153 77.5h43.2M153 77.4h43.2M153 77.3h43.2M153 77.2h43.2M153 77.1h43.2M153 77h43.2M153 76.9h43.2"/>
<path d="M153 76.8h43.2M153 76.7h43.2M153 76.6h43.2M153 76.5h43.2M153 76.4h43.2M153 76.3v7M153 76.2h43.2M153 76.2h43.1M153 76.1h43.1M153 76h43.1M153 75.9h43.1M153 75.8h43.1"/>
<path d="M153.1 75.7l43 .1M153.1 75.7h43M153.1 75.6h43M153.1 75.6h42.9M153.1 75.6l-.1 .7M153.1 75.5h42.9M153.1 75.4h42.9M153.2 75.4h42.8M153.2 75.3h42.7M153.2 75.3l-.1 .3M153.2 75.2h42.7M153.3 75.1h42.5"/>
<path d="M153.3 75h42.5M153.4 75h42.3M153.4 75l-.2 .3M153.4 74.9h42.3M153.5 74.8h42.1M153.6 74.7h42M153.6 74.7h41.9M153.6 74.7l-.2 .3M153.7 74.6h41.8M153.7 74.5h41.7M153.8 74.5h41.5M153.8 74.4h41.5"/>
<path d="M153.9 74.4h41.3M153.9 74.3h41.3M154 74.3h41.1M154.1 74.2h41M154.2 74.2h40.7M154.2 74.1h40.7M154.4 74.1h40.4M154.5 74h40.2M154.5 74l-.9 .7M154.6 74h39.9M154.7 73.9h39.7M155 73.9h39.2"/>
<path d="M155.1 73.8h38.9M155.2 73.8l-.7 .2M155.5 73.8h-.3M163.5 60.6l1.1 .8 .7 .2M166 61.6h16.9M166.2 61.5h16.5M166.5 61.4h15.9M166.6 61.4h15.7M166.7 61.3h15.4M166.8 61.3h15.3M166.9 61.2h15.1M167 61.2h14.9"/>
<path d="M167.1 61.1h14.7M167.2 61.1h14.5M167.3 61h14.3M167.4 60.9h14.1M167.5 60.8h13.9M167.6 60.7h13.7M167.7 60.6h13.5M167.7 60.6h13.4M167.7 60.6l-1.1 .8-.6 .2M167.8 60.5h13.3M167.8 60.4h13.3M167.8 60.4h13.2"/>
<path d="M167.9 60.3h13.1M167.9 60.2h13.1M168 60.2h12.9M168 60.1h12.9M168 60l12.9 .1M168 60h12.8M181.1 60.6l1.1 .8 .7 .2M183.6 61.6h36.4M183.8 61.5h36M184.1 61.4h35.5M184.2 61.4h35.2M184.3 61.3h35"/>
<path d="M184.4 61.3h34.8M184.5 61.2h34.6M184.6 61.2h34.4M184.7 61.1h34.2M184.8 61.1h34M184.9 61h33.9M184.9 61h33.8M185 60.9h33.7M185 60.9h33.6M185.1 60.8h33.4M185.2 60.7h33.2M185.3 60.6h33"/>
<path d="M185.3 60.6l-1 .8-.7 .2M185.4 60.5h32.9M185.4 60.5h32.8M185.4 60.4h32.8M185.5 60.3h32.6M185.5 60.2h32.6M185.6 60.2h32.5M185.6 60.1h32.4M185.6 60h32.4M185.7 60h32.3M193.6 73.8h.4M194 73.8l.7 .2"/>
<path d="M194.7 74l.8 .7M195.5 74.7l.2 .3M195.7 75l.2 .3M195.9 75.3l.1 .3M196 75.6l.1 .4M196.1 76l.1 .3M196.2 76.3v7M201.2 76.3h24.7M201.2 80h24.7M201.2 79.9h24.7M201.2 79.8h24.7M201.2 79.7h24.7"/>
<path d="M201.2 79.6h24.7M201.2 79.5h24.7M201.2 79.4h24.7M201.2 79.3h24.7M201.2 79.2h24.7M201.2 79.1h24.7M201.2 79h24.7M201.2 78.9h24.7M201.2 78.8h24.7M201.2 78.7h24.7M201.2 78.6h24.7M201.2 78.5h24.7"/>
<path d="M201.2 78.4h24.7M201.2 78.3h24.7M201.2 78.2h24.7M201.2 78.1h24.7M201.2 78h24.7M201.2 77.9h24.7M201.2 77.8h24.7M201.2 77.7h24.7M201.2 77.6h24.7M201.2 77.5h24.7M201.2 77.4h24.7M201.2 77.3h24.7"/>
<path d="M201.2 77.2h24.7M201.2 77.1h24.7M201.2 77h24.7M201.2 76.9h24.7M201.2 76.8h24.7M201.2 76.7h24.7M201.2 76.6h24.7M201.2 76.5h24.7M201.2 76.4h24.7M201.2 76.3v52.1M201.2 76.2h24.7M201.3 76l-.1 .3"/>
<path d="M201.3 76.1h24.6M201.3 76h24.6M201.3 75.9h24.6M201.3 75.8h24.6M201.3 75.7h24.6M201.3 75.6h24.6M201.3 75.6v.4M201.4 75.5h24.5M201.4 75.4h24.5M201.4 75.3h24.5M201.5 75.2h24.4M201.5 75.1h24.4"/>
<path d="M201.6 75h24.3M201.6 75l-.3 .6M201.7 74.9h24.2M201.7 74.8h24.2M201.8 74.8h24.1M201.8 74.7h24.1M201.8 74.7l-.2 .3M201.9 74.6h24M202 74.5h23.9M202.1 74.4h23.8M202.2 74.3h23.7M202.3 74.3h23.6"/>
<path d="M202.3 74.2h23.6M202.4 74.2h23.5M202.5 74.1h23.4M202.6 74.1h23.3M202.7 74l-.9 .7M202.7 74h23.2M202.9 74h23M203 73.9h22.9M203.2 73.9h22.7M203.4 73.8h22.5v57.1h-22.2M203.8 73.8l-1.1 .2M218.3 60.6l1.1 .8 .6 .2"/>
<path d="M220.8 61.6h5.1M221 61.5h4.9M221.2 61.4h4.7M221.3 61.4h4.6M221.5 61.3h4.4M221.6 61.3h4.3M221.7 61.2h4.2M221.8 61.1h4.1M221.9 61.1h4M222 61h3.9M222.1 61h3.8M222.1 60.9h3.8"/>
<path d="M222.2 60.9h3.7M222.2 60.8h3.7M222.3 60.8h3.6M222.3 60.7h3.6M222.4 60.7h3.5M222.4 60.6h3.5M222.5 60.6l-1.1 .8-.7 .2M222.5 60.6h3.4M222.5 60.5h3.4M222.6 60.4h3.3M222.6 60.3h3.3M222.7 60.3h3.2"/>
<path d="M222.7 60.2h3.2M222.7 60.1h3.2M222.8 60.1h3.1M68 99.9h29.1M68 99.8h29.1M68 99.7h29.1M68 99.6h29.1M68 99.5h29.1M68 99.4h29.1M68 99.3h29.1M68 99.2h29.1M68 99.1h29.1"/>
<path d="M68 99h29.1M68 98.9h29.1M68 98.8h29.1M68 98.7h29.1M68 98.6l4.9 .1M68 98.6h4.6M68 98.5l4.5 .1M68 98.5h4.3M68 98.4h4.3M68 98.4h4.2M68 98.3h4.1M68 98.3h4"/>
<path d="M68 98.2h3.9M68 98.1l3.8 .1M68 98.1h3.8M68 98l3.7 .1M68 98h3.6M68 97.9l3.6 .1M68 97.9h3.5M68 97.8l3.5 .1M68 97.8h3.4M68 97.7h3.4M68 97.7h3.3M68 97.6h3.3"/>
<path d="M68 97.5h3.2M68 97.4h3.2M68 97.3l3.1 .1M68 97.3h3.1M68 97.2l3.1 .1M68 97.2h3.1M68 97.1l3 .1M68 97.1h3M68 97h3M68 96.9l3 .1M68 96.9h2.9M68 96.8h2.9"/>
<path d="M68 96.7h2.9M68 96.6h2.9M68 96.6h2.8M68 96.5h2.8M68 96.4h2.8M68 96.3h2.8M68 96.2h2.8M68 96.1h2.8M68 96h2.8M68 90.4h14.9M68 90.3h15M68 89.9h15.1"/>
<path d="M68 89.8h15.1M68 89.7h15.1M68 89.6h15.1M68 89.5h15.1M68 89.4h15.1M68 89.3h15.1M68 89.2h15.1M68 89.1h15.1M68 89h15.1M68 88.9h15.1M68 88.8h15.1M68 88.7h15.1"/>
<path d="M68 88.6h15.1M68 88.5h15.1M68 88.4h15.1M68 88.3h15.1M68 88.2h15.1M68 88.1h15.1M68 88h15.1M68 87.9h15.1M68 87.8h15.1M68 87.7h15.1M68 87.6h15.1M68 87.5h15.1"/>
<path d="M68 87.4h15.1M68 87.3h15.1M68 87.2h15.1M68 87.1h15.1M68 87h15.1M68 86.9h15.1M68 86.8h15.1M68 86.7h15.1M68 86.6h15.1M68 86.5h15.1M68 86.4h15.1M68 86.3h15.1"/>
<path d="M68 86.2h15.1M68 86.1h15.1M68 86h15.1M68 85.9h15.1M68 85.8h15.1M68 85.7h15.1M68 85.6h15.1M68 85.5h15.1M68 85.4h15.1M68 85.3h15.1M68 85.2h15.1M68 85.1h15.1"/>
<path d="M68 85h15.1M68 84.9h15.1M68 84.8h15.1M68 84.7h15.1M68 84.6h15.1M68 84.5h15.1M68 84.4h15.1M68 84.3h15.1M68 84.2h15.1M68 84.1h15.1M68 84h15.1M68 83.9h15.1"/>
<path d="M68 83.8h15.1M68 83.7h15.1M68 83.6h15.1M68 83.5h15.1M68 83.4h15.1M68 83.3h15.1M68 83.2h15.1M68 83.1h15.1M68 83h15.1M68 82.9h15.1M68 82.8h15.1M68 82.7h15.1"/>
<path d="M68 82.6h15.1M68 82.5h15.1M68 82.4h15.1M68 82.3h15.1M68 82.2h15.1M68 82.1h15.1M68 82h15.1M68 81.9h15.1M68 81.8h15.1M68 81.7h15.1M68 81.6h15.1M68 81.5h15.1"/>
<path d="M68 81.4h15.1M68 81.3h15.1M68 81.2h15.1M68 81.1h15.1M68 81h15.1M68 80.9h15.1M68 80.8h15.1M68 80.7h15.1M68 80.6h15.1M68 80.5h15.1M68 80.4h15.1M68 80.3h15.1"/>
<path d="M68 80.2h15.1M68 80.1h15.1M70.8 96.4v-.4h-2.8v13h2.8v-.5M70.8 96.4l.2 .7M71 97.1l.3 .6M71.3 97.7l.5 .5 1.3 .5M74 98.7h23.1M74.2 98.6h22.9M74.4 98.6h22.7M74.5 98.5h22.6M74.6 98.4h22.5M74.7 98.4h22.4"/>
<path d="M74.8 98.3h22.3M74.9 98.3h22.2M75 98.2h22.1M75.1 98.2h22M75.1 98.1h22M75.2 98.1h21.9M75.2 98h21.9M75.3 98h21.8M75.3 97.9h21.8M75.4 97.9h21.7M75.4 97.8h21.7M75.5 97.7h21.6"/>
<path d="M75.5 97.7l-.5 .5-1.2 .5M75.6 97.6h21.5M75.6 97.5h21.5M75.7 97.4h21.4M75.7 97.3h21.4M75.8 97.3h21.3M75.8 97.2h21.2M75.9 97.1h21.1M75.9 97h21.1M75.9 96.9h21M75.9 96.8h21M76 96.7h20.9"/>
<path d="M76 96.7h20.8M76 96.6h20.8M76 96.5h20.7M76 96.5h20.6M76.1 96.4h20.5M76.1 96.4h20.4M76.1 96.3h20.4M76.1 96.2l20.3 .1M76.1 96.2h20.2M76.1 96.1l20.1 .1M76.1 96.1h20M76.1 96l19.8 .1"/>
<path d="M76.1 96.4l-.6 1.3M82.2 90.9h-14.2M82.4 90.8l-14.4 .1M82.4 90.8h-14.4M82.5 90.7l-14.5 .1M82.6 90.7h-14.6M82.7 90.6h-14.7M82.8 90.5l-14.8 .1M82.8 90.5h-14.8M82.8 90.5l-.3 .3M82.9 90.4h-14.9M83 90.3h-15"/>
<path d="M83 90.3l-.2 .2M83 90.2h-15M83 90.1l-15 .1M83.1 90.1h-15.1M83.1 90.1l-.1 .2M83.1 90l-15.1 .1M83.1 90h-15.1M83.1 89.9h-15.1M83.1 89.9v.2M83.1 89.7v-36.1h-15.1v37.3h13.9l.6-.1M83.1 89.7h-15.1M83.1 89.7v.2"/>
<path d="M87 89.8h10.1M87 89.7h10.1M87 89.6h10.1M87 89.5h10.1M87 89.4h10.1M87 89.3h10.1M87 89.2h10.1M87 89.1h10.1M87 89h10.1M87 88.9h10.1M87 88.8h10.1M87 88.7h10.1"/>
<path d="M87 88.6h10.1M87 88.5h10.1M87 88.4h10.1M87 88.3h10.1M87 88.2h10.1M87 88.1h10.1M87 88h10.1M87 87.9h10.1M87 87.8h10.1M87 87.7h10.1M87 87.6h10.1M87 87.5h10.1"/>
<path d="M87 87.4h10.1M87 87.3h10.1M87 87.2h10.1M87 87.1h10.1M87 87h10.1M87 86.9h10.1M87 86.8h10.1M87 86.7h10.1M87 86.6h10.1M87 86.5h10.1M87 86.4h10.1M87 86.3h10.1"/>
<path d="M87 86.2h10.1M87 86.1h10.1M87 86h10.1M87 85.9h10.1M87 85.8h10.1M87 85.7h10.1M87 85.6h10.1M87 85.5h10.1M87 85.4h10.1M87 85.3h10.1M87 85.2h10.1M87 85.1h10.1"/>
<path d="M87 85h10.1M87 84.9h10.1M87 84.8h10.1M87 84.7h10.1M87 84.6h10.1M87 84.5h10.1M87 84.4h10.1M87 84.3h10.1M87 84.2h10.1M87 84.1h10.1M87 84h10.1M87 83.9h10.1"/>
<path d="M87 83.8h10.1M87 83.7h10.1M87 83.6h10.1M87 83.5h10.1M87 83.4h10.1M87 83.3h10.1M87 83.2h10.1M87 83.1h10.1M87 83h10.1M87 82.9h10.1M87 82.8h10.1M87 82.7h10.1"/>
<path d="M87 82.6h10.1M87 82.5h10.1M87 82.4h10.1M87 82.3h10.1M87 82.2h10.1M87 82.1h10.1M87 82h10.1M87 81.9h10.1M87 81.8h10.1M87 81.7h10.1M87 81.6h10.1M87 81.5h10.1"/>
<path d="M87 81.4h10.1M87 81.3h10.1M87 81.2h10.1M87 81.1h10.1M87 81h10.1M87 80.9h10.1M87 80.8h10.1M87 80.7h10.1M87 80.6h10.1M87 80.5h10.1M87 80.4h10.1M87 80.3h10.1"/>
<path d="M87 80.2h10.1M87 80.1h10.1M87 89.7v.2M87 89.9h10.1M87 89.9v.2M87 90h10.1M87 90.1h10M87 90.1l.1 .2M87.1 90.3h9.9M87.1 90.3h9.8M87.1 90.3l.1 .2M87.2 90.4h9.7"/>
<path d="M87.2 90.5l.4 .3 .6 .1h7.7M87.3 90.5h9.5M87.3 90.6h9.4M87.4 90.6h9.3M87.5 90.7h9.1M87.5 90.7h9M87.7 90.8h8.7M87.7 90.8h8.6M87.9 90.9h8.2M95.5 96l1 .3M95.7 96h-19.6v.4M96.5 96.3l.1 .2"/>
<path d="M96.6 96.5l.3 .4M96.8 90.5h-9.6M96.8 90.5l-.3 .3-.7 .1M96.9 90.4h-9.7M96.9 90.3l-.1 .2M96.9 96.9l.1 .2M97 90.2h-9.9M97 90.1l-9.9 .1M97 90.1l-.1 .2M97 97.1l.1 .2M97 90l-10 .1M97.1 89.9h-10.1"/>
<path d="M97.1 89.9l-.1 .2M97.1 97.3v.3M97.1 97.6v9.8M97.1 89.7v.2M100.9 99.9h13.7M100.9 99.8h13.7M100.9 99.7h13.7M100.9 99.6h13.7M100.9 99.5h13.7M100.9 99.4h13.7M100.9 99.3h13.7M100.9 99.2h13.7"/>
<path d="M100.9 99.1h13.7M100.9 99h13.7M100.9 98.9h13.7M100.9 98.8h13.7M100.9 98.7h13.7M100.9 98.6l9.1 .1M100.9 98.6h8.9M100.9 98.5l8.7 .1M100.9 98.5h8.6M100.9 98.4h8.5M100.9 98.4h8.4M100.9 98.3h8.3"/>
<path d="M100.9 98.3h8.2M100.9 98.2h8.2M100.9 98.1l8 .1M100.9 98.1h8M100.9 98l7.9 .1M100.9 98h7.9M100.9 97.9l7.8 .1M100.9 97.9h7.8M100.9 97.8l7.7 .1M100.9 97.8h7.7M100.9 97.7h7.6M100.9 97.6h7.5"/>
<path d="M100.9 97.5h7.5M100.9 97.4h7.4M100.9 97.3l7.4 .1M100.9 97.3h7.3M100.9 97.2l7.3 .1M100.9 97.2h7.3M100.9 97.1l7.3 .1M100.9 97.1h7.2M100.9 97l7.2 .1M100.9 97h7.2M100.9 96.9h7.2M100.9 96.8h7.2"/>
<path d="M100.9 96.8h7.1M100.9 96.7l7.1 .1M100.9 96.7h7.1M100.9 96.6h7.1M100.9 96.5h7.1M100.9 96.5h7M100.9 96.4h7M100.9 96.3h7M100.9 96.2h7M100.9 96.1h7M100.9 96h7M100.9 95.9h7"/>
<path d="M100.9 95.8h7M100.9 95.7h7.1M100.9 95.6h7.1M100.9 95.5h7.1M100.9 95.4h7.1M100.9 95.3h7.2M100.9 95.2h7.2M100.9 95.1h7.2M100.9 94.9h7.3M100.9 94.8h7.4M100.9 93.4h13.7M100.9 93.3h13.7"/>
<path d="M100.9 93.2h13.7M100.9 93.1h13.7M100.9 93h13.7M100.9 92.9h13.7M100.9 92.8h13.7M100.9 92.7h13.7M100.9 92.6h13.7M100.9 92.5h13.7M100.9 92.4h13.7M100.9 92.3h13.7M100.9 92.2h13.7M100.9 92.1h13.7"/>
<path d="M100.9 92h13.7M100.9 91.9h13.7M100.9 91.8h13.7M100.9 91.7h13.7M100.9 91.6h13.7M100.9 91.5h13.7M100.9 91.4h13.7M100.9 91.3h13.7M100.9 91.2h13.7M100.9 91.1h13.7M100.9 91h13.7M100.9 90.9h13.7"/>
<path d="M100.9 90.8h13.7M100.9 90.7h13.7M100.9 90.6h13.7M100.9 90.5h13.7M100.9 90.4h13.7M100.9 90.3h13.7M100.9 90.2h13.7M100.9 90.1h13.7M100.9 90h13.7M100.9 89.9h13.7M100.9 89.8h13.7M100.9 89.7h13.7"/>
<path d="M100.9 89.6h13.7M100.9 89.5h13.7M100.9 89.4h13.7M100.9 89.3h13.7M100.9 89.2h13.7M100.9 89.1h13.7M100.9 89h13.7M100.9 88.9h13.7M100.9 88.8h13.7M100.9 88.7h13.7M100.9 88.6h13.7M100.9 88.5h13.7"/>
<path d="M100.9 88.4h13.7M100.9 88.3h13.7M100.9 88.2h13.7M100.9 88.1h13.7M100.9 88h13.7M100.9 87.9h13.7M100.9 87.8h13.7M100.9 87.7h13.7M100.9 87.6h13.7M100.9 87.5h13.7M100.9 87.4h13.7M100.9 87.3h13.7"/>
<path d="M100.9 87.2h13.7M100.9 87.1h13.7M100.9 87h13.7M100.9 86.9h13.7M100.9 86.8h13.7M100.9 86.7h13.7M100.9 86.6h13.7M100.9 86.5h13.7M100.9 86.4h13.7M100.9 86.3h13.7M100.9 86.2h13.7M100.9 86.1h13.7"/>
<path d="M100.9 86h13.7M100.9 85.9h13.7M100.9 85.8h13.7M100.9 85.7h13.7M100.9 85.6h13.7M100.9 85.5h13.7M100.9 85.4h13.7M100.9 85.3h13.7M100.9 85.2h13.7M100.9 85.1h13.7M100.9 85h13.7M100.9 84.9h13.7"/>
<path d="M100.9 84.8h13.7M100.9 84.7h13.7M100.9 84.6h13.7M100.9 84.5h13.7M100.9 84.4h13.7M100.9 84.3h13.7M100.9 84.2h13.7M100.9 84.1h13.7M100.9 84h13.7M100.9 83.9h13.7M100.9 83.8h13.7M100.9 83.7h13.7"/>
<path d="M100.9 83.6h13.7M100.9 83.5h13.7M100.9 83.4h13.7M100.9 83.3h13.7M100.9 83.2h13.7M100.9 83.1h13.7M100.9 83h13.7M100.9 82.9h13.7M100.9 82.8h13.7M100.9 82.7h13.7M100.9 82.6h13.7M100.9 82.5h13.7"/>
<path d="M100.9 82.4h13.7M100.9 82.3h13.7M100.9 82.2h13.7M100.9 82.1h13.7M100.9 82h13.7M100.9 81.9h13.7M100.9 81.8h13.7M100.9 81.7h13.7M100.9 81.6h13.7M100.9 81.5h13.7M100.9 81.4h13.7M100.9 81.3h13.7"/>
<path d="M100.9 81.2h13.7M100.9 81.1h13.7M100.9 81h13.7M100.9 80.9h13.7M100.9 80.8h13.7M100.9 80.7h13.7M100.9 80.6h13.7M100.9 80.5h13.7M100.9 80.4h13.7M100.9 80.3h13.7M100.9 80.2h13.7M100.9 80.1h13.7"/>
<path d="M107.9 95.7h-7M108 95.5l-7.1 .1M108.1 95.2l-7.2 .1M108.1 95.1l-.2 .6 .2 1.4M108.1 97.1a2.61 2.61 0 0 0 2.1 1.6M108.1 95l-7.2 .1M108.2 95h-7.3M108.2 94.9l-7.3 .1M108.3 94.8h-7.4M108.3 94.7h-7.4M108.4 94.7h-7.5M108.4 94.6h-7.5"/>
<path d="M108.5 94.5h-7.6M108.5 94.4l-7.6 .1M108.6 94.4h-7.7M108.6 94.3l-7.7 .1M108.6 94.3h-7.7M108.7 94.2l-7.8 .1M108.8 94.2h-7.9M108.8 94.1h-7.9M108.9 94.1h-8M108.9 94h-8M109 94h-8.1M109.1 93.9h-8.2"/>
<path d="M109.2 93.9h-8.3M109.3 93.8h-8.4M109.4 93.7l-8.5 .1M109.4 93.7h-8.5M109.5 93.6l-8.6 .1M109.6 93.6l-1.1 .9-.4 .6M109.7 93.6h-8.8M110 93.5l-9.1 .1M110.1 93.5h-9.2M110.2 93.5l-.6 .1M110.9 93.5l.7 .1M111 93.5h3.6"/>
<path d="M111.1 98.7h3.5M111.2 93.5h3.4M111.4 98.6h3.2M111.4 93.6h3.2M111.5 98.6h3.1M111.6 93.6h3M111.6 93.6l.6 .4M111.7 98.5h2.9M111.7 93.7h2.9M111.7 98.4h2.9M111.8 93.7h2.8M111.8 98.4h2.8"/>
<path d="M111.9 93.8h2.7M111.9 98.3h2.7M112 93.9h2.6M112 98.3h2.6M112.1 93.9h2.5M112.1 98.2h2.5M112.1 94h2.5M112.2 98.2h2.4M112.2 94l.8 1.1M112.2 98.1h2.4M112.2 94h2.4M112.3 94.1h2.3"/>
<path d="M112.3 98.1h2.3M112.4 98h2.2M112.4 94.2h2.2M112.4 97.9h2.2M112.5 94.3h2.1M112.5 97.9h2.1M112.5 97.8h2.1M112.6 94.4h2M112.6 97.7h2M112.7 97.7h1.9M112.7 94.5h1.9M112.7 97.7l-.5 .5-1.3 .5"/>
<path d="M112.7 97.6h1.9M112.7 94.6h1.9M112.8 97.5h1.8M112.8 94.7h1.8M112.8 97.4h1.8M112.8 94.8h1.8M112.9 94.8h1.7M112.9 97.3h1.7M112.9 94.9h1.7M112.9 97.2h1.7M113 97.2h1.6M113 95h1.6"/>
<path d="M113 97.1h1.6M113 95.1h1.6M113 95.1l.2 1.3M113 97.1l-.3 .6M113 97h1.6M113.1 97h1.5M113.1 96.9h1.5M113.1 95.2h1.5M113.1 95.3h1.5M113.1 96.8h1.5M113.1 95.4h1.5M113.1 96.7h1.5"/>
<path d="M113.1 96.6h1.5M113.1 95.5h1.5M113.2 96.6h1.4M113.2 96.5h1.4M113.2 95.6h1.4M113.2 95.7h1.4M113.2 96.4h1.4M113.2 96.3h1.4M113.2 96.2h1.4M113.2 96.1h1.4M113.2 96h1.4M113.2 95.9h1.4"/>
<path d="M113.2 95.8h1.4M113.2 96.4l-.2 .7M114.6 93.4l-13.7 .1M124.7 91.5h12M124.7 91.4h12M124.7 91.3h12.1M124.7 91.2h12.1M124.7 91.1h12.1M124.7 91h12.1M124.7 90.9h12.1M124.7 90.8h12.1M124.7 90.7h12.1"/>
<path d="M124.7 90.6h12.1M124.7 90.5h12.1M124.7 90.4h12.1M124.7 90.3h12.1M124.7 90.2h12.1M124.7 90.1h12.1M124.7 90h12.1M124.7 89.9h12.1M124.7 89.8h12.1M124.7 89.7h12.1M124.7 89.6h12.1M124.7 89.5h12.1"/>
<path d="M124.7 89.4h12.1M124.7 89.3h12.1M124.7 89.2h12.1M124.7 89.1h12.1M124.7 89h12.1M124.7 88.9h12.1M124.7 88.8h12.1M124.7 88.7h12.1M124.7 88.6h12.1M124.7 88.5h12.1M124.7 88.4h12.1M124.7 88.3h12.1"/>
<path d="M124.7 88.2h12.1M124.7 88.1h12.1M124.7 88h12.1M124.7 87.9h12.1M124.7 87.8h12.1M124.7 87.7h12.1M124.7 87.6h12.1M124.7 87.5h12.1M124.7 87.4h12.1M124.7 87.3h12.1M124.7 87.2h12.1M124.7 87.1h12.1"/>
<path d="M124.7 87h12.1M124.7 86.9h12.1M124.7 86.8h12.1M124.7 86.7h12.1M124.7 86.6h12.1M124.7 86.5h12.1M124.7 86.4h12.1M124.7 86.3h12.1M124.7 86.2h12.1M124.7 86.1h12.1M124.7 86h12.1M124.7 85.9h12.1"/>
<path d="M124.7 85.8h12.1M124.7 85.7h12.1M124.7 85.6h12.1M124.7 85.5h12.1M124.7 85.4h12.1M124.7 85.3h12.1M124.7 85.2h12.1M124.7 85.1h12.1M124.7 85h12.1M124.7 84.9h12.1M124.7 84.8h12.1M124.7 84.7h12.1"/>
<path d="M124.7 84.6h12.1M124.7 84.5h12.1M124.7 84.4h12.1M124.7 84.3h12.1M124.7 84.2h12.1M124.7 84.1h12.1M124.7 84h12.1M124.7 83.9h12.1M124.7 83.8h12.1M124.7 83.7h12.1M124.7 83.6h12.1M124.7 83.5h12.1"/>
<path d="M124.7 83.4h12.1M124.7 83.3h12.1M124.7 83.2h12.1M124.7 83.1h12.1M124.7 83h12.1M124.7 82.9h12.1M124.7 82.8h12.1M124.7 82.7h12.1M124.7 82.6h12.1M124.7 82.5h12.1M124.7 82.4h12.1M124.7 82.3h12.1"/>
<path d="M124.7 82.2h12.1M124.7 82.1h12.1M124.7 82h12.1M124.7 81.9h12.1M124.7 81.8h12.1M124.7 81.7h12.1M124.7 81.6h12.1M124.7 81.5h12.1M124.7 81.4h12.1M124.7 81.3h12.1M124.7 81.2h12.1M124.7 81.1h12.1"/>
<path d="M124.7 81h12.1M124.7 80.9h12.1M124.7 80.8h12.1M124.7 80.7h12.1M124.7 80.6h12.1M124.7 80.5h12.1M124.7 80.4h12.1M124.7 80.3h12.1M124.7 80.2h12.1M124.7 80.1h12.1M124.7 91.2l.1 .4M124.8 91.6h11.9"/>
<path d="M124.8 91.5h11.9M124.8 91.6v.3M124.8 91.7h11.9M124.8 91.9h11.8M124.8 91.8h11.8M124.8 91.9l.4 .6M124.9 92h11.6M124.9 92.1h11.6M124.9 92.2h11.6M125 92.3h11.4M125 92.4h11.3M125.1 92.4h11.2"/>
<path d="M125.1 92.5h11.1M125.2 92.5l.2 .3M125.2 92.6h11M125.2 92.6h10.9M125.3 92.7h10.8M125.3 92.8h10.7M125.4 92.8l.2 .2M125.4 92.9h10.5M125.5 92.9h10.3M125.5 93h10.3M125.6 93h10.1M125.6 93l.3 .2"/>
<path d="M125.7 93.1h9.9M125.8 93.1h9.7M125.9 93.2h9.5M125.9 93.2l.7 .2M126.1 93.3h9.1M126.2 93.3h8.9M126.4 93.4h8.5M126.6 93.4h8.1M126.6 93.4l.4 .1M128.1 93.5h.1M128.8 93.5h.1M135.6 93.1l-1.4 .4"/>
<path d="M136.2 92.6l-.6 .5M136.4 92.3l-.2 .3M136.4 92.2h-11.5M136.5 92.1h-11.6M136.6 91.8h-11.8M136.7 91.7h-11.9M136.7 91.6l-11.9 .1M136.7 91.7l-.3 .6M136.8 91.4h-12.1M136.8 91.3l-.1 .4M136.8 90.9v.4M142.8 99.9h5.1"/>
<path d="M142.8 99.8h5.1M142.8 99.7h5.1M142.8 99.6h5.1M142.8 99.5h5.1M142.8 99.4h5.1M142.8 99.3h5.1M142.8 99.2h5.1M142.8 99.1h5.1M142.8 99h5.1M142.8 98.9h5.1M142.8 98.8h5.1M142.8 98.7h5.1"/>
<path d="M142.8 98.6h5.1M142.8 98.5h5.1M142.8 98.4h5.1M142.8 98.3h5.1M142.8 98.2h5.1M142.8 98.1h5.1M142.8 98h5.1M142.8 97.9h5.1M142.8 97.8h5.1M142.8 97.7h5.1M142.8 97.6h5.1M142.8 97.5h5.1"/>
<path d="M142.8 97.4h5.1M142.8 97.3h5.1M142.8 97.2h5.1M142.8 97.1h5.1M142.8 97h5.1M142.8 96.9h5.1M142.8 96.8h5.1M142.8 96.7h5.1M142.8 96.6h5.1M142.8 96.5h5.1M142.8 96.4h5.1M142.8 96.3h5.1"/>
<path d="M142.8 96.2h5.1M142.8 96.1h5.1M142.8 96h5.1M142.8 95.9h5.1M142.8 95.8h5.1M142.8 95.7h5.1M142.8 95.6h5.1M142.8 95.5h5.1M142.8 95.4h5.1M142.8 95.3h5.1M142.8 95.2h5.1M142.8 95.1h5.1"/>
<path d="M142.8 95h5.1M142.8 94.9h5.1M142.8 94.8h5.1M142.8 94.7h5.1M142.8 94.6h5.1M142.8 94.5h5.1M142.8 94.4h5.1M142.8 94.3h5.1M142.8 94.2h5.1M142.8 94.1h5.1M142.8 94h5.1M142.8 93.9h5.1"/>
<path d="M142.8 93.8h5.1M142.8 93.7h5.1M142.8 93.6h5.1M142.8 93.5h5.1M142.8 93.4h5.1M142.8 93.3h5.1M142.8 93.2h5.1M142.8 93.1h5.1M142.8 93h5.1M142.8 92.9h5.1M142.8 92.8h5.1M142.8 92.7h5.1"/>
<path d="M142.8 92.6h5.1M142.8 92.5h5.1M142.8 92.4h5.1M142.8 92.3h5.1M142.8 92.2h5.1M142.8 92.1h5.1M142.8 92h5.1M142.8 91.9h5.1M142.8 91.8h5.1M142.8 91.7h5.1M142.8 91.6h5.1M142.8 91.5h5.1"/>
<path d="M142.8 91.4h5.1M142.8 91.3h5.1M142.8 91.2h5.1M142.8 91.1h5.1M142.8 91h5.1M142.8 90.9h5.1M142.8 90.8h5.1M142.8 90.7h5.1M142.8 90.6h5.1M142.8 90.5h5.1M142.8 90.4h5.1M142.8 90.3h5.1"/>
<path d="M142.8 90.2h5.1M142.8 90.1h5.1M142.8 90h5.1M142.8 89.9h5.1M142.8 89.8h5.1M142.8 89.7h5.1M142.8 89.6h5.1M142.8 89.5h5.1M142.8 89.4h5.1M142.8 89.3h5.1M142.8 89.2h5.1M142.8 89.1h5.1"/>
<path d="M142.8 89h5.1M142.8 88.9h5.1M142.8 88.8h5.1M142.8 88.7h5.1M142.8 88.6h5.1M142.8 88.5h5.1M142.8 88.4h5.1M142.8 88.3h5.1M142.8 88.2h5.1M142.8 88.1h5.1M142.8 88h5.1M142.8 87.9h5.1"/>
<path d="M142.8 87.8h5.1M142.8 87.7h5.1M142.8 87.6h5.1M142.8 87.5h5.1M142.8 87.4h5.1M142.8 87.3h5.1M142.8 87.2h5.1M142.8 87.1h5.1M142.8 87h5.1M142.8 86.9h5.1M142.8 86.8h5.1M142.8 86.7h5.1"/>
<path d="M142.8 86.6h5.1M142.8 86.5h5.1M142.8 86.4h5.1M142.8 86.3h5.1M142.8 86.2h5.1M142.8 86.1h5.1M142.8 86h5.1M142.8 85.9h5.1M142.8 85.8h5.1M142.8 85.7h5.1M142.8 85.6h5.1M142.8 85.5h5.1"/>
<path d="M142.8 85.4h5.1M142.8 85.3h5.1M142.8 85.2h5.1M142.8 85.1h5.1M142.8 85h5.1M142.8 84.9h5.1M142.8 84.8h5.1M142.8 84.7h5.1M142.8 84.6h5.1M142.8 84.5h5.1M142.8 84.4h5.1M142.8 84.3h5.1"/>
<path d="M142.8 84.2h5.1M142.8 84.1h5.1M142.8 84h5.1M142.8 83.9h5.1M142.8 83.8h5.1M142.8 83.7h5.1M142.8 83.6h5.1M142.8 83.5h5.1M142.8 83.4h5.1M142.8 83.3h5.1M142.8 83.2h5.1M142.8 83.1h5.1"/>
<path d="M142.8 83h5.1M142.8 82.9h5.1M142.8 82.8h5.1M142.8 82.7h5.1M142.8 82.6h5.1M142.8 82.5h5.1M142.8 82.4h5.1M142.8 82.3h5.1M142.8 82.2h5.1M142.8 82.1h5.1M142.8 82h5.1M142.8 81.9h5.1"/>
<path d="M142.8 81.8h5.1M142.8 81.7h5.1M142.8 81.6h5.1M142.8 81.5h5.1M142.8 81.4h5.1M142.8 81.3h5.1M142.8 81.2h5.1M142.8 81.1h5.1M142.8 81h5.1M142.8 80.9h5.1M142.8 80.8h5.1M142.8 80.7h5.1"/>
<path d="M142.8 80.6h5.1M142.8 80.5h5.1M142.8 80.4h5.1M142.8 80.3h5.1M142.8 80.2h5.1M142.8 80.1h5.1M153 99.9h43.2M153 99.8h43.2M153 99.7h43.2M153 99.6h43.2M153 99.5h43.2M153 99.4h43.2"/>
<path d="M153 99.3h43.2M153 99.2h43.2M153 99.1h43.2M153 99h43.2M153 98.9h43.2M153 98.8h43.2M153 98.7h43.2M153 98.6l12.1 .1M153 98.6h11.8M153 98.5l11.7 .1M153 98.5h11.5M153 98.4h11.5"/>
<path d="M153 98.4h11.4M153 98.3h11.3M153 98.3h11.2M153 98.2h11.1M153 98.1l11 .1M153 98.1h11M153 98l10.9 .1M153 98h10.9M153 97.9l10.8 .1M153 97.9h10.7M153 97.8l10.7 .1M153 97.8h10.6"/>
<path d="M153 97.7h10.6M153 97.7h10.5M153 97.6h10.5M153 97.5h10.4M153 97.4h10.4M153 97.3l10.3 .1M153 97.3h10.3M153 97.2l10.3 .1M153 97.2h10.3M153 97.1l10.2 .1M153 97.1h10.2M153 97h10.2"/>
<path d="M153 96.9l10.2 .1M153 96.9h10.1M153 96.8h10.1M153 96.7h10.1M153 96.6h10.1M153 96.6h10M153 96.5h10M153 96.4h10M153 96.3h10M153 96.2h10M153 96.1h10M153 96h10"/>
<path d="M153 95.9h10M153 95.8h10M153 95.7h10M153 95.5h10M153 95.5h10.1M153 95.4h10.1M153 95.2h10.1M153 95.2h10.2M153 95.1h10.2M153 83.4h43.2M153 83.3h43.2M153 83.2h43.2"/>
<path d="M153 83.1h43.2M153 83h43.2M153 82.9h43.2M153 82.8h43.2M153 82.7h43.2M153 82.6h43.2M153 82.5h43.2M153 82.4h43.2M153 82.3h43.2M153 82.2h43.2M153 82.1h43.2M153 82h43.2"/>
<path d="M153 81.9h43.2M153 81.8h43.2M153 81.7h43.2M153 81.6h43.2M153 81.5h43.2M153 81.4h43.2M153 81.3h43.2M153 81.2h43.2M153 81.1h43.2M153 81h43.2M153 80.9h43.2M153 80.8h43.2"/>
<path d="M153 80.7h43.2M153 80.6h43.2M153 80.5h43.2M153 80.4h43.2M153 80.3h43.2M153 80.2h43.2M153 80.1h43.2M153 83.3v.4M153 95.1v15.2M153 83.6h43.1M153 83.5h43.1M153 83.8h43.1"/>
<path d="M153 83.7h43.1M153 83.7l.1 .4M153 94.6h10.5M153 94.5h10.5M153 83.9h43.1M153.1 94.4h10.5M153.1 84h43M153.1 83.9h43M153.1 84.1h42.9M153.1 94.3l-.1 .8M153.1 84.2h42.9M153.1 84.1l.1 .4"/>
<path d="M153.1 84.3h42.9M153.2 84.3h42.8M153.2 84.4h42.7M153.2 94l-.1 .3M153.2 84.5h42.7M153.2 84.5l.5 .7M153.3 84.6h42.6M153.3 84.6h42.5M153.3 84.7h42.5M153.4 84.7h42.4M153.4 93.7l-.2 .3M153.4 84.8h42.3"/>
<path d="M153.5 84.9h42.2M153.5 84.9h42.1M153.5 93.5h41.9M153.5 85h42.1M153.6 85h42M153.6 93.4h41.8M153.6 93.4h41.7M153.6 93.4l-.2 .3M153.6 85.1h41.9M153.6 85.2h41.9M153.7 93.3h41.6M153.7 85.2l.3 .3"/>
<path d="M153.7 85.2h41.7M153.7 93.2l41.5 .1M153.8 85.3h41.6M153.8 93.2h41.3M153.8 85.3h41.5M153.9 85.4h41.4M153.9 93.1h41.1M153.9 85.4h41.3M154 93h41M154 85.5h41.2M154 85.5l.6 .4 1.2 .3M154.1 93h40.8"/>
<path d="M154.1 85.5h41M154.1 92.9h40.7M154.1 85.6h40.9M154.1 92.9l-.5 .5M154.2 85.6h40.7M154.2 92.9h40.5M154.2 85.7h40.7M154.3 92.8h40.3M154.3 85.7h40.5M154.4 92.8h40.1M154.4 85.8h40.3M154.5 92.7h39.9"/>
<path d="M154.5 85.9h40.1M154.6 85.9h39.9M154.6 92.7h39.6M154.8 92.6h39.3M154.8 86h39.6M154.8 92.6l-.7 .3M155 86h39.2M155 92.6h38.8M155.1 86.1h39M155.4 92.5h38M155.4 86.1h38.4M155.5 92.5l-.7 .1"/>
<path d="M155.8 86.2h37.5M163 95.7v.7M163 96.4l.5 1.3M163 95.7h-10M163 95.6h-10M163.1 95.4l-10.1 .1M163.1 95.3l-10.1 .1M163.1 95.3h-10.1M163.2 95.1h-10.2M163.2 95.1l-.2 .6M163.2 95h-10.2M163.3 94.9l-10.3 .1"/>
<path d="M163.3 94.9h-10.3M163.3 94.8h-10.3M163.4 94.8h-10.4M163.4 94.7h-10.4M163.4 94.6h-10.4M163.5 97.7l.5 .5 1.3 .5M163.6 94.4h-10.5M163.7 94.3l-10.6 .1M163.7 94.3h-10.6M163.8 94.2l-10.7 .1M163.8 94.2h-10.7M163.9 94.1h-10.8"/>
<path d="M163.9 94.1h-10.7M164 94h-10.8M164.1 94h-10.9M164.1 93.9h-10.9M164.3 93.9h-11M164.3 93.8h-11M164.4 93.7l-11.1 .1M164.5 93.7h-11.1M164.6 93.6l-11.2 .1M164.6 93.6l-1.1 .9-.3 .6M164.8 93.6h-11.4M165 93.5l-11.5 .1"/>
<path d="M165.2 93.5h-11.7M165.3 93.5l-.7 .1M166 93.5l.6 .1M166.1 93.5h16.7M166.2 98.7h16.5M166.2 93.5h16.4M166.4 98.6h16.1M166.5 93.6h15.9M166.6 98.6h15.7M166.6 93.6l1.1 .9M166.7 93.6h15.5M166.7 98.5h15.5"/>
<path d="M166.8 98.4h15.3M166.8 93.7h15.3M166.8 93.7h15.2M166.9 98.4h15.1M166.9 93.8h15M167 98.3h14.9M167 93.9h14.9M167.1 98.3h14.7M167.1 93.9h14.7M167.2 98.2h14.5M167.2 94h14.5M167.3 98.2h14.3"/>
<path d="M167.3 94h14.3M167.3 98.1h14.3M167.3 94.1h14.2M167.4 98.1h14.1M167.4 94.1h14.1M167.4 98h14.1M167.4 94.2h14M167.5 98h13.9M167.5 94.2h13.9M167.5 97.9h13.9M167.5 94.3h13.8M167.6 97.9h13.7"/>
<path d="M167.6 94.3h13.7M167.6 97.8h13.7M167.6 94.4h13.6M167.7 97.7h13.5M167.7 94.4h13.5M167.7 97.7h13.4M167.7 94.5l.4 .6M167.7 97.7l-.5 .5-1.2 .5M167.7 94.5h13.4M167.8 97.6h13.3M167.8 94.6h13.3M167.8 97.5h13.2"/>
<path d="M167.9 97.5h13.1M167.9 94.7h13.1M167.9 97.4h13.1M167.9 94.8h13.1M168 97.3h12.9M168 94.9h12.9M168 97.2h12.9M168 97.2h12.8M168 95h12.8M168.1 97.1h12.7M168.1 97h12.7M168.1 95.1h12.7"/>
<path d="M168.1 95.1l.2 .6M168.1 97.1l-.4 .6M168.1 95.2h12.7M168.1 96.9h12.6M168.1 95.2h12.6M168.1 96.8h12.6M168.1 95.3h12.6M168.2 96.8h12.5M168.2 96.7h12.5M168.2 95.4h12.5M168.2 96.6h12.5M168.2 95.5h12.5"/>
<path d="M168.2 96.5h12.4M168.2 95.7h12.4M168.3 95.7v.7M168.3 96.5h12.3M168.3 96.4h12.3M168.3 96.3h12.3M168.3 96.2h12.3M168.3 96.1h12.3M168.3 96h12.3M168.3 95.9h12.3M168.3 95.8h12.3M168.3 95.7h12.3"/>
<path d="M168.3 96.4l-.2 .7M180.6 95.7v.7M180.6 96.4l.2 .7M180.7 95.6h-12.5M180.7 95.3h-12.6M180.8 95.1l-.2 .6M180.8 97.1l.3 .6M181 94.7h-13.1M181.1 94.5l-.3 .6M181.1 97.7l.5 .5 1.3 .5M181.6 94l-.5 .5M182.2 93.6l-.6 .4"/>
<path d="M182.9 93.5l-.7 .1M183.6 93.5l1.2 .5M183.7 93.5h11.8M183.8 98.7h12.4M183.9 93.5l11.6 .1M184 98.6h12.2M184.1 93.6h11.5M184.2 98.6h12M184.3 93.6l11.3 .1M184.3 98.5h11.9M184.4 98.4h11.8M184.4 93.7h11.2"/>
<path d="M184.4 93.7l11.3 .1M184.5 98.4h11.7M184.6 93.8h11.1M184.6 98.3h11.6M184.6 93.9h11.1M184.7 98.3h11.5M184.7 93.9h11.1M184.8 98.2h11.4M184.8 94h11M184.8 94l.9 1.1M184.9 98.2h11.3M184.9 94h10.9"/>
<path d="M184.9 98.1h11.3M184.9 94.1h11M185 98.1h11.2M185 94.1h10.9M185 98h11.2M185 94.2h10.9M185.1 98h11.1M185.1 94.2h10.8M185.1 97.9h11.1M185.1 94.3h10.8M185.2 97.9h11M185.2 94.3l10.8 .1"/>
<path d="M185.2 97.8h11M185.3 94.4h10.7M185.3 97.7h10.9M185.3 97.7l-.5 .5-1.2 .5M185.4 94.5h10.6M185.4 97.6h10.8M185.4 94.6h10.6M185.4 97.5h10.8M185.5 97.5h10.7M185.5 94.7h10.6M185.5 97.4h10.7M185.5 94.8h10.6"/>
<path d="M185.6 97.3h10.6M185.6 94.9h10.5M185.6 97.2h10.6M185.6 94.9l10.5 .1M185.6 95h10.5M185.7 95h10.4M185.7 97.1h10.5M185.7 97h10.5M185.7 95.1h10.4M185.7 95.1l.2 .6M185.7 97.1l-.4 .6M185.7 95.2h10.4"/>
<path d="M185.7 96.9h10.5M185.7 95.2h10.5M185.8 96.8h10.4M185.8 95.3h10.4M185.8 96.7h10.4M185.8 95.4h10.4M185.8 95.5h10.4M185.8 96.6h10.4M185.8 96.5h10.4M185.8 95.7h10.4M185.8 95.6h10.4M185.9 95.7v.7"/>
<path d="M185.9 96.5h10.3M185.9 96.4h10.3M185.9 96.3h10.3M185.9 96.2h10.3M185.9 96.1h10.3M185.9 96h10.3M185.9 95.9h10.3M185.9 95.8h10.3M185.9 95.7h10.3M185.9 96.4l-.2 .7M193.3 92.5l.8 .1M194.1 92.6l.4 .2"/>
<path d="M194.5 85.9l-1.2 .3M194.5 92.8l1 .7M195.2 85.5l-.7 .4M195.5 93.5l.2 .3M195.7 84.9l-.5 .6M195.7 93.8l.2 .4M195.9 84.5l-.2 .4M195.9 94.2l.2 .8M196 84.1h-42.9M196.1 83.7h-43.1M196.1 83.7l-.2 .8M196.1 95l.1 .4"/>
<path d="M196.2 83.4h-43.2M196.2 95.4v14.6M196.2 83.3l-.1 .4M201.2 99.9h24.7M201.2 99.8h24.7M201.2 99.7h24.7M201.2 99.6h24.7M201.2 99.5h24.7M201.2 99.4h24.7M201.2 99.3h24.7M201.2 99.2h24.7M201.2 99.1h24.7"/>
<path d="M201.2 99h24.7M201.2 98.9h24.7M201.2 98.8h24.7M201.2 98.7h24.7M201.2 98.6l18.6 .1M201.2 98.6h18.4M201.2 98.5l18.3 .1M201.2 98.5h18.1M201.2 98.4h18M201.2 98.4h17.9M201.2 98.3h17.8M201.2 98.3h17.7"/>
<path d="M201.2 98.2h17.7M201.2 98.1l17.6 .1M201.2 98.1h17.5M201.2 98l17.5 .1M201.2 98h17.4M201.2 97.9l17.3 .1M201.2 97.9h17.3M201.2 97.8l17.2 .1M201.2 97.8h17.2M201.2 97.7h17.1M201.2 97.6h17M201.2 97.5h17"/>
<path d="M201.2 97.4h16.9M201.2 97.3l16.9 .1M201.2 97.3h16.9M201.2 97.2l16.8 .1M201.2 97.2h16.8M201.2 97.1l16.8 .1M201.2 97.1h16.8M201.2 97h16.7M201.2 96.9h16.7M201.2 96.8h16.7M201.2 96.8h16.6M201.2 96.7h16.6"/>
<path d="M201.2 96.6h16.6M201.2 96.5h16.6M201.2 96.4h16.6M201.2 96.3h16.6M201.2 96.2h16.6M201.2 96.1h16.6M201.2 96h16.6M201.2 95.9h16.6M201.2 95.8h16.6M201.2 95.7h16.6M201.2 95.6h16.6M201.2 95.4h16.6"/>
<path d="M201.2 95.3h16.7M201.2 95.1h16.7M201.2 94.9h16.9M201.2 94.8h16.9M201.2 94.7h17M201.2 94.4h17.1M201.2 94.1h17.4M201.2 93.4h24.7M201.2 93.3h24.7M201.2 93.2h24.7M201.2 93.1h24.7M201.2 93h24.7"/>
<path d="M201.2 92.9h24.7M201.2 92.8h24.7M201.2 92.7h24.7M201.2 92.6h24.7M201.2 92.5h24.7M201.2 92.4h24.7M201.2 92.3h24.7M201.2 92.2h24.7M201.2 92.1h24.7M201.2 92h24.7M201.2 91.9h24.7M201.2 91.8h24.7"/>
<path d="M201.2 91.7h24.7M201.2 91.6h24.7M201.2 91.5h24.7M201.2 91.4h24.7M201.2 91.3h24.7M201.2 91.2h24.7M201.2 91.1h24.7M201.2 91h24.7M201.2 90.9h24.7M201.2 90.8h24.7M201.2 90.7h24.7M201.2 90.6h24.7"/>
<path d="M201.2 90.5h24.7M201.2 90.4h24.7M201.2 90.3h24.7M201.2 90.2h24.7M201.2 90.1h24.7M201.2 90h24.7M201.2 89.9h24.7M201.2 89.8h24.7M201.2 89.7h24.7M201.2 89.6h24.7M201.2 89.5h24.7M201.2 89.4h24.7"/>
<path d="M201.2 89.3h24.7M201.2 89.2h24.7M201.2 89.1h24.7M201.2 89h24.7M201.2 88.9h24.7M201.2 88.8h24.7M201.2 88.7h24.7M201.2 88.6h24.7M201.2 88.5h24.7M201.2 88.4h24.7M201.2 88.3h24.7M201.2 88.2h24.7"/>
<path d="M201.2 88.1h24.7M201.2 88h24.7M201.2 87.9h24.7M201.2 87.8h24.7M201.2 87.7h24.7M201.2 87.6h24.7M201.2 87.5h24.7M201.2 87.4h24.7M201.2 87.3h24.7M201.2 87.2h24.7M201.2 87.1h24.7M201.2 87h24.7"/>
<path d="M201.2 86.9h24.7M201.2 86.8h24.7M201.2 86.7h24.7M201.2 86.6h24.7M201.2 86.5h24.7M201.2 86.4h24.7M201.2 86.3h24.7M201.2 86.2h24.7M201.2 86.1h24.7M201.2 86h24.7M201.2 85.9h24.7M201.2 85.8h24.7"/>
<path d="M201.2 85.7h24.7M201.2 85.6h24.7M201.2 85.5h24.7M201.2 85.4h24.7M201.2 85.3h24.7M201.2 85.2h24.7M201.2 85.1h24.7M201.2 85h24.7M201.2 84.9h24.7M201.2 84.8h24.7M201.2 84.7h24.7M201.2 84.6h24.7"/>
<path d="M201.2 84.5h24.7M201.2 84.4h24.7M201.2 84.3h24.7M201.2 84.2h24.7M201.2 84.1h24.7M201.2 84h24.7M201.2 83.9h24.7M201.2 83.8h24.7M201.2 83.7h24.7M201.2 83.6h24.7M201.2 83.5h24.7M201.2 83.4h24.7"/>
<path d="M201.2 83.3h24.7M201.2 83.2h24.7M201.2 83.1h24.7M201.2 83h24.7M201.2 82.9h24.7M201.2 82.8h24.7M201.2 82.7h24.7M201.2 82.6h24.7M201.2 82.5h24.7M201.2 82.4h24.7M201.2 82.3h24.7M201.2 82.2h24.7"/>
<path d="M201.2 82.1h24.7M201.2 82h24.7M201.2 81.9h24.7M201.2 81.8h24.7M201.2 81.7h24.7M201.2 81.6h24.7M201.2 81.5h24.7M201.2 81.4h24.7M201.2 81.3h24.7M201.2 81.2h24.7M201.2 81.1h24.7M201.2 81h24.7"/>
<path d="M201.2 80.9h24.7M201.2 80.8h24.7M201.2 80.7h24.7M201.2 80.6h24.7M201.2 80.5h24.7M201.2 80.4h24.7M201.2 80.3h24.7M201.2 80.2h24.7M201.2 80.1h24.7M217.8 95.7v.7M217.8 96.4l.1 .7M217.8 95.7h-16.6"/>
<path d="M217.8 95.5l-16.6 .1M217.8 95.5h-16.6M217.9 95.3l-16.7 .1M217.9 95.2l-16.7 .1M217.9 95.2h-16.7M217.9 95.1l-.1 .6M217.9 97.1l.4 .6M218 95l-16.8 .1M218 95h-16.8M218 94.9l-16.8 .1M218.1 94.8h-16.9M218.1 94.7h-16.9"/>
<path d="M218.2 94.6h-17M218.3 94.5h-17.1M218.3 97.7l.5 .5 1.2 .5M218.4 94.4h-17.2M218.4 94.3l-17.2 .1M218.5 94.3h-17.3M218.5 94.2l-17.3 .1M218.6 94.2h-17.4M218.7 94.1h-17.5M218.7 94h-17.5M218.8 94l-.9 1.1M218.8 94h-17.6"/>
<path d="M218.9 93.9h-17.7M219 93.9h-17.8M219.1 93.8h-17.9M219.2 93.7l-18 .1M219.2 93.7h-18M219.4 93.6l-18.2 .1M219.5 93.6h-18.3M219.8 93.5l-18.6 .1M219.9 93.5h-18.7M220 93.5l-1.2 .5M220.7 93.5l.7 .1M220.9 93.5h5"/>
<path d="M220.9 98.7h5M221 93.5h4.9M221.2 98.6h4.7M221.2 93.6h4.7M221.3 98.6h4.6M221.4 93.6h4.5M221.4 93.6l1.1 .9M221.5 98.5h4.4M221.5 93.7h4.4M221.5 98.4h4.4M221.6 93.7h4.3M221.6 98.4h4.3"/>
<path d="M221.7 93.8h4.2M221.7 98.3h4.2M221.8 93.9h4.1M221.8 98.3h4.1M221.9 93.9h4M221.9 98.2h4M222 94h3.9M222 98.2h3.9M222 98.1h3.9M222.1 94.1h3.8M222.1 98.1h3.8M222.2 98h3.7"/>
<path d="M222.2 94.2h3.7M222.2 97.9h3.7M222.3 97.9h3.6M222.3 94.3h3.6M222.4 97.8h3.5M222.4 94.3h3.5M222.4 94.4h3.5M222.4 97.7h3.5M222.5 94.4h3.4M222.5 97.7h3.4M222.5 94.5h3.4M222.5 94.5l.3 .6"/>
<path d="M222.5 97.7l-.5 .5-1.3 .5M222.5 97.6h3.4M222.5 94.6h3.4M222.6 97.5h3.3M222.6 94.6h3.3M222.6 94.7h3.3M222.6 97.4h3.3M222.7 94.8h3.2M222.7 97.4h3.2M222.7 97.3h3.2M222.7 94.9h3.2M222.8 97.2h3.1"/>
<path d="M222.8 95h3.1M222.8 97.1h3.1M222.8 97h3.1M222.8 95.1h3.1M222.8 95.1l.2 .6M222.8 97.1l-.3 .6M222.9 97h3M222.9 96.9h3M222.9 95.2h3M222.9 95.3h3M222.9 96.8h3M222.9 96.7h3"/>
<path d="M222.9 95.4h3M222.9 96.6h3M222.9 95.5h3M223 96.6h2.9M223 96.5h2.9M223 95.6h2.9M223 95.5h2.9M223 95.7h2.9M223 95.7v.7M223 96.4h2.9M223 96.3h2.9M223 96.2h2.9"/>
<path d="M223 96.1h2.9M223 96h2.9M223 95.9h2.9M223 95.8h2.9M223 96.4l-.2 .7M225.9 93.4l-24.7 .1M68 120h15.1M68 119.9h15.1M68 119.8h15.1M68 119.7h15.1M68 119.6h15.1M68 119.5h15.1"/>
<path d="M68 119.4h15.1M68 119.3h15.1M68 119.2h15.1M68 119.1h15.1M68 119h15.1M68 118.9h15.1M68 118.8h15.1M68 118.7h15.1M68 118.6h15.1M68 118.5h15.1M68 118.4h15.1M68 118.3h15.1"/>
<path d="M68 118.2h15.1M68 118.1h15.1M68 118h15.1M68 117.9h15.1M68 117.8h15.1M68 117.7h15.1M68 117.6h15.1M68 117.5h15.1M68 117.4h15.1M68 117.3h15.1M68 117.2h15.1M68 117.1h15.1"/>
<path d="M68 117h15.1M68 116.9h15.1M68 116.8h15.1M68 116.7h15.1M68 116.6h15.1M68 116.5h15.1M68 116.4h15.1M68 116.3h15.1M68 116.2h15.1M68 116.1h15.1M68 116h15.1M68 115.9h15.1"/>
<path d="M68 115.8h15.1M68 115.7h15.1M68 115.6h15.1M68 115.5h15.1M68 115.4h15.1M68 115.3h15.1M68 115.2h15.1M68 115.1h15.1M68 115h15.1M68 114.9h15.1M68 114.9h15M68 114.8h15"/>
<path d="M68 114.7l15 .1M68 114.7h15M68 114.6h14.9M68 114.5l14.8 .1M68 114.5h14.8M68 114.4h14.7M68 114.3h14.6M68 114.3h14.5M68 114.2h14.4M68 114.1h14.2M68 109h2.8M68 108.9h2.8"/>
<path d="M68 108.8h2.8M68 108.7h2.8M68 108.6h2.8M68 108.5h2.8M68 108.4h2.8M68 108.3h2.8M68 108.3h2.9M68 108.2h2.9M68 108.1h2.9M68 108h2.9M68 107.9h3M68 107.8h3"/>
<path d="M68 107.6h3.1M68 107.5h3.2M68 107.4h3.3M68 107.3h3.3M68 106.2h29.1M68 106.1h29.1M68 106h29.1M68 105.9h29.1M68 105.8h29.1M68 105.7h29.1M68 105.6h29.1M68 105.5h29.1"/>
<path d="M68 105.4h29.1M68 105.3h29.1M68 105.2h29.1M68 105.1h29.1M68 105h29.1M68 104.9h29.1M68 104.8h29.1M68 104.7h29.1M68 104.6h29.1M68 104.5h29.1M68 104.4h29.1M68 104.3h29.1"/>
<path d="M68 104.2h29.1M68 104.1h29.1M68 104h29.1M68 103.9h29.1M68 103.8h29.1M68 103.7h29.1M68 103.6h29.1M68 103.5h29.1M68 103.4h29.1M68 103.3h29.1M68 103.2h29.1M68 103.1h29.1"/>
<path d="M68 103h29.1M68 102.9h29.1M68 102.8h29.1M68 102.7h29.1M68 102.6h29.1M68 102.5h29.1M68 102.4h29.1M68 102.3h29.1M68 102.2h29.1M68 102.1h29.1M68 102h29.1M68 101.9h29.1"/>
<path d="M68 101.8h29.1M68 101.7h29.1M68 101.6h29.1M68 101.5h29.1M68 101.4h29.1M68 101.3h29.1M68 101.2h29.1M68 101.1h29.1M68 101h29.1M68 100.9h29.1M68 100.8h29.1M68 100.7h29.1"/>
<path d="M68 100.6h29.1M68 100.5h29.1M68 100.4h29.1M68 100.3h29.1M68 100.2h29.1M68 100.1h29.1M68 100h29.1M70.8 108.4h-2.8M70.9 108.1h-2.9M71 107.9h-3M71 107.9l-.2 .6M71 107.8h-3"/>
<path d="M71.1 107.7l-3.1 .1M71.1 107.7h-3.1M71.1 107.6l-3.1 .1M71.2 107.5l-3.2 .1M71.2 107.4h-3.2M71.3 107.3h-3.3M71.4 107.2l-3.4 .1M71.4 107.2h-3.4M71.5 107.1h-3.5M71.6 107h-3.6M71.7 106.9h-3.7M71.7 106.8l-3.7 .1"/>
<path d="M71.8 106.8h-3.8M71.9 106.7l-3.9 .1M72 106.7h-4M72.1 106.6l-4.1 .1M72.2 106.6h-4.2M72.2 106.5l-4.2 .1M72.3 106.5h-4.3M72.4 106.4h-4.4M72.7 106.4h-4.7M72.8 106.3h-4.8M73 106.3h-5M73.1 106.2a2.69 2.69 0 0 0-2.1 1.7"/>
<path d="M73.8 106.2l.6 .2M73.8 106.3h23.3M74 106.3h23.1M74.2 106.4h22.9M74.4 106.4h22.7M74.4 106.4a2.6 2.6 0 0 1 1.7 2.6h19.6M74.5 106.5h22.6M74.6 106.5h22.5M74.7 106.6h22.4M74.8 106.6h22.3M74.9 106.7h22.2M75 106.7h22.1"/>
<path d="M75.1 106.8h22M75.2 106.9h21.9M75.2 107h21.9M75.3 107h21.8M75.3 107.1h21.8M75.4 107.1h21.7M75.4 107.2h21.7M75.5 107.2h21.6M75.5 107.3h21.6M75.6 107.3h21.5M75.6 107.4h21.5M75.6 107.5h21.5"/>
<path d="M75.7 107.5h21.4M75.7 107.6h21.4M75.8 107.7h21.3M75.8 107.8h21.2M75.9 107.8h21.1M75.9 107.9h21.1M75.9 108.1h21.1M75.9 108h21.1M75.9 108.2h21M75.9 108.1h21M76 108.2h20.9M76 108.3h20.8"/>
<path d="M76 108.5h20.7M82.5 114.3l-.6-.2h-13.9v37.4h15.1v-36.1M82.5 114.3l.2 .1M82.7 114.4l.1 .2M82.8 114.6l.2 .1M83 114.7l.1 .2M83.1 114.9v.2M83.1 115.1v.3M87 115.4v36.1h1.8l.1-.3M87 120h10.1M87 119.9h10.1M87 119.8h10.1"/>
<path d="M87 119.7h10.1M87 119.6h10.1M87 119.5h10.1M87 119.4h10.1M87 119.3h10.1M87 119.2h10.1M87 119.1h10.1M87 119h10.1M87 118.9h10.1M87 118.8h10.1M87 118.7h10.1M87 118.6h10.1"/>
<path d="M87 118.5h10.1M87 118.4h10.1M87 118.3h10.1M87 118.2h10.1M87 118.1h10.1M87 118h10.1M87 117.9h10.1M87 117.8h10.1M87 117.7h10.1M87 117.6h10.1M87 117.5h10.1M87 117.4h10.1"/>
<path d="M87 117.3h10.1M87 117.2h10.1M87 117.1h10.1M87 117h10.1M87 116.9h10.1M87 116.8h10.1M87 116.7h10.1M87 116.6h10.1M87 116.5h10.1M87 116.4h10.1M87 116.3h10.1M87 116.2h10.1"/>
<path d="M87 116.1h10.1M87 116h10.1M87 115.9h10.1M87 115.8h10.1M87 115.7h10.1M87 115.6h10.1M87 115.5h10.1M87 115.4h10.1M87 115.3h10.1M87 115.2h10.1M87 115.1h10.1M87 115.1v.3"/>
<path d="M87 115h10M87 114.9h10M87 114.9v.2M87.1 114.9h9.9M87.1 114.8h9.9M87.1 114.7h9.8M87.1 114.7l-.1 .2M87.2 114.7h9.7M87.2 114.6h9.7M87.2 114.6h9.6M87.2 114.6l-.1 .1M87.3 114.5h9.5"/>
<path d="M87.3 114.4h9.4M87.4 114.4h9.3M87.4 114.4l.8-.3h7.6l.7 .2 .3 .3M87.4 114.4l-.2 .2M87.5 114.3h9.1M87.5 114.3h9M87.7 114.2h8.7M87.7 114.2h8.6M87.9 114.1h8.2M95.9 109h-19.8M96.1 108.9h-20M96.2 108.9h-20.1"/>
<path d="M96.3 108.8h-20.2M96.4 108.8h-20.3M96.5 108.7l-1 .3M96.5 108.7h-20.4M96.5 108.6l-20.4 .1M96.6 108.6h-20.5M96.6 108.5l-20.5 .1M96.6 108.6l-.1 .1M96.8 108.4l-20.8 .1M96.8 108.4h-20.8M96.8 108.4l-.2 .2M96.8 114.6l.1 .1"/>
<path d="M96.9 108.3h-20.9M96.9 114.7l.1 .2M96.9 108.2l-.1 .2M97 114.9l.1 .2M97 107.9l-.1 .3M97.1 115.1v.3M97.1 107.7l-.1 .2M97.1 115.4v36.1h-1.9v-.3M97.1 107.4v.3M100.9 111.8h13.7M100.9 120h13.7M100.9 119.9h13.7"/>
<path d="M100.9 119.8h13.7M100.9 119.7h13.7M100.9 119.6h13.7M100.9 119.5h13.7M100.9 119.4h13.7M100.9 119.3h13.7M100.9 119.2h13.7M100.9 119.1h13.7M100.9 119h13.7M100.9 118.9h13.7M100.9 118.8h13.7M100.9 118.7h13.7"/>
<path d="M100.9 118.6h13.7M100.9 118.5h13.7M100.9 118.4h13.7M100.9 118.3h13.7M100.9 118.2h13.7M100.9 118.1h13.7M100.9 118h13.7M100.9 117.9h13.7M100.9 117.8h13.7M100.9 117.7h13.7M100.9 117.6h13.7M100.9 117.5h13.7"/>
<path d="M100.9 117.4h13.7M100.9 117.3h13.7M100.9 117.2h13.7M100.9 117.1h13.7M100.9 117h13.7M100.9 116.9h13.7M100.9 116.8h13.7M100.9 116.7h13.7M100.9 116.6h13.7M100.9 116.5h13.7M100.9 116.4h13.7M100.9 116.3h13.7"/>
<path d="M100.9 116.2h13.7M100.9 116.1h13.7M100.9 116h13.7M100.9 115.9h13.7M100.9 115.8h13.7M100.9 115.7h13.7M100.9 115.6h13.7M100.9 115.5h13.7M100.9 115.4h13.7M100.9 115.3h13.7M100.9 115.2h13.7M100.9 115.1h13.7"/>
<path d="M100.9 115h13.7M100.9 114.9h13.7M100.9 114.8h13.7M100.9 114.7h13.7M100.9 114.6h13.7M100.9 114.5h13.7M100.9 114.4h13.7M100.9 114.3h13.7M100.9 114.2h13.7M100.9 114.1h13.7M100.9 114h13.7M100.9 113.9h13.7"/>
<path d="M100.9 113.8h13.7M100.9 113.7h13.7M100.9 113.6h13.7M100.9 113.5h13.7M100.9 113.4h13.7M100.9 113.3h13.7M100.9 113.2h13.7M100.9 113.1h13.7M100.9 113h13.7M100.9 112.9h13.7M100.9 112.8h13.7M100.9 112.7h13.7"/>
<path d="M100.9 112.6h13.7M100.9 112.5h13.7M100.9 112.4h13.7M100.9 112.3h13.7M100.9 112.2h13.7M100.9 112.1h13.7M100.9 112h13.7M100.9 111.9h13.7M100.9 111.7h13.7M100.9 111.6h13.7M100.9 111.5h13.7M100.9 111.5h9.3"/>
<path d="M100.9 111.4h9.1M100.9 111.3l8.9 .1M100.9 111.3h8.7M100.9 111.2l8.6 .1M100.9 111.2h8.5M100.9 111.1l8.4 .1M100.9 111.1h8.3M100.9 111l8.2 .1M100.9 111h8.1M100.9 110.9l8 .1M100.9 110.9h8M100.9 110.8h7.9"/>
<path d="M100.9 110.7h7.8M100.9 110.6h7.7M100.9 110.5h7.6M100.9 110.4l7.6 .1M100.9 110.4h7.5M100.9 110.3l7.5 .1M100.9 110.3h7.5M100.9 110.2h7.4M100.9 110.1h7.4M100.9 110.1h7.3M100.9 110h7.3M100.9 109.9h7.3"/>
<path d="M100.9 109.9h7.2M100.9 109.8h7.2M100.9 109.7l7.2 .1M100.9 109.7h7.2M100.9 109.6h7.2M100.9 109.5h7.1M100.9 109.4l7.1 .1M100.9 109.4h7.1M100.9 109.3h7.1M100.9 109.2h7M100.9 109.1h7M100.9 109h7"/>
<path d="M100.9 108.9h7M100.9 108.8h7M100.9 108.7h7M100.9 108.6h7M100.9 108.5h7M100.9 108.4h7.1M100.9 108.3h7.1M100.9 108.2h7.1M100.9 108.1h7.2M100.9 108h7.2M100.9 107.9h7.2M100.9 107.8h7.2"/>
<path d="M100.9 107.7h7.3M100.9 107.6h7.4M100.9 107h7.9M100.9 106.2h13.7M100.9 106.1h13.7M100.9 106h13.7M100.9 105.9h13.7M100.9 105.8h13.7M100.9 105.7h13.7M100.9 105.6h13.7M100.9 105.5h13.7M100.9 105.4h13.7"/>
<path d="M100.9 105.3h13.7M100.9 105.2h13.7M100.9 105.1h13.7M100.9 105h13.7M100.9 104.9h13.7M100.9 104.8h13.7M100.9 104.7h13.7M100.9 104.6h13.7M100.9 104.5h13.7M100.9 104.4h13.7M100.9 104.3h13.7M100.9 104.2h13.7"/>
<path d="M100.9 104.1h13.7M100.9 104h13.7M100.9 103.9h13.7M100.9 103.8h13.7M100.9 103.7h13.7M100.9 103.6h13.7M100.9 103.5h13.7M100.9 103.4h13.7M100.9 103.3h13.7M100.9 103.2h13.7M100.9 103.1h13.7M100.9 103h13.7"/>
<path d="M100.9 102.9h13.7M100.9 102.8h13.7M100.9 102.7h13.7M100.9 102.6h13.7M100.9 102.5h13.7M100.9 102.4h13.7M100.9 102.3h13.7M100.9 102.2h13.7M100.9 102.1h13.7M100.9 102h13.7M100.9 101.9h13.7M100.9 101.8h13.7"/>
<path d="M100.9 101.7h13.7M100.9 101.6h13.7M100.9 101.5h13.7M100.9 101.4h13.7M100.9 101.3h13.7M100.9 101.2h13.7M100.9 101.1h13.7M100.9 101h13.7M100.9 100.9h13.7M100.9 100.8h13.7M100.9 100.7h13.7M100.9 100.6h13.7"/>
<path d="M100.9 100.5h13.7M100.9 100.4h13.7M100.9 100.3h13.7M100.9 100.2h13.7M100.9 100.1h13.7M100.9 100h13.7M107.9 108.5h-7M108 108.4l-7.1 .1M108 108.3h-7.1M108.1 108.1h-7.2M108.1 107.9l-7.2 .1M108.1 107.9l-.2 .6 .2 1.4"/>
<path d="M108.1 109.9l.8 1.1 .7 .3M108.2 107.7l-7.3 .1M108.2 107.6l-7.3 .1M108.3 107.5h-7.4M108.4 107.4l-7.5 .1M108.4 107.4h-7.5M108.4 107.3h-7.5M108.5 107.3h-7.6M108.5 107.2l-7.6 .1M108.6 107.2h-7.7M108.6 107.1h-7.7M108.7 107.1h-7.8"/>
<path d="M108.7 107h-7.8M108.8 106.9h-7.9M108.9 106.8l-8 .1M108.9 106.8h-8M109 106.7l-8.1 .1M109.1 106.7h-8.2M109.2 106.6l-8.3 .1M109.3 106.6h-8.4M109.4 106.5l-8.5 .1M109.5 106.5h-8.6M109.6 106.4l-1.1 .9-.4 .6M109.6 111.3l.6 .2"/>
<path d="M109.6 106.4h-8.7M109.8 106.4h-8.9M110 106.3h-9.1M110.2 106.3h-9.3M110.2 106.2l-.6 .2M110.9 106.2a2.61 2.61 0 0 1 2.1 1.7M110.9 106.3h3.7M111 111.5h3.6M111.1 111.4h3.5M111.2 106.3h3.4M111.3 106.4h3.3M111.4 111.4h3.2"/>
<path d="M111.5 106.4h3.1M111.6 111.3h3M111.6 111.3l-.7 .2M111.7 111.3h2.9M111.7 106.5h2.9M111.8 111.2h2.8M111.8 106.5h2.8M111.8 106.6h2.8M112 111.1h2.6M112 106.6h2.6M112 106.7h2.6M112.1 106.7h2.5"/>
<path d="M112.1 111h2.5M112.2 111h2.4M112.2 111l-.6 .3M112.2 106.8h2.4M112.2 110.9h2.4M112.3 106.8h2.3M112.3 106.9h2.3M112.3 110.8h2.3M112.4 107h2.2M112.4 110.8h2.2M112.4 110.7h2.2M112.5 107.1h2.1"/>
<path d="M112.5 110.7h2.1M112.5 110.6h2.1M112.6 110.6h2M112.6 107.2h2M112.6 110.5h2M112.7 110.5h1.9M112.7 107.3h1.9M112.7 110.4h1.9M112.7 107.4h1.9M112.8 110.3h1.8M112.8 107.4h1.8M112.8 107.5h1.8"/>
<path d="M112.8 110.2h1.8M112.9 110.1h1.7M112.9 107.6h1.7M112.9 110h1.7M112.9 107.7h1.7M113 109.9h1.6M113 107.8h1.6M113 107.9l.2 .6-.2 1.4M113 109.9l-.8 1.1M113 109.8h1.6M113 107.9h1.6M113.1 109.7h1.5"/>
<path d="M113.1 108h1.5M113.1 109.6h1.5M113.1 108.1h1.5M113.1 108.2h1.5M113.1 109.5h1.5M113.1 108.3h1.5M113.1 109.4h1.5M113.2 109.3h1.4M113.2 108.4h1.4M113.2 109.2h1.4M113.2 108.5h1.4M113.2 109.1h1.4"/>
<path d="M113.2 109h1.4M113.2 108.9h1.4M113.2 108.8h1.4M113.2 108.7h1.4M113.2 108.6h1.4M124.7 113.8v37.7h19l.1-.3M124.7 120h23.2M124.7 119.9h23.2M124.7 119.8h23.2M124.7 119.7h23.2M124.7 119.6h23.2M124.7 119.5h23.2"/>
<path d="M124.7 119.4h23.2M124.7 119.3h23.2M124.7 119.2h23.2M124.7 119.1h23.2M124.7 119h23.2M124.7 118.9h23.2M124.7 118.8h23.2M124.7 118.7h23.2M124.7 118.6h23.2M124.7 118.5h23.2M124.7 118.4h23.2M124.7 118.3h23.2"/>
<path d="M124.7 118.2h23.2M124.7 118.1h23.2M124.7 118h23.2M124.7 117.9h23.2M124.7 117.8h23.2M124.7 117.7h23.2M124.7 117.6h23.2M124.7 117.5h23.2M124.7 117.4h23.2M124.7 117.3h23.2M124.7 117.2h23.2M124.7 117.1h23.2"/>
<path d="M124.7 117h23.2M124.7 116.9h23.2M124.7 116.8h23.2M124.7 116.7h23.2M124.7 116.6h23.2M124.7 116.5h23.2M124.7 116.4h23.2M124.7 116.3h23.2M124.7 116.2h23.2M124.7 116.1h23.2M124.7 116h23.2M124.7 115.9h23.2"/>
<path d="M124.7 115.8h23.2M124.7 115.7h23.2M124.7 115.6h23.2M124.7 115.5h23.2M124.7 115.4h23.2M124.7 115.3h23.2M124.7 115.2h23.2M124.7 115.1h23.2M124.7 115h23.2M124.7 114.9h23.2M124.7 114.8h23.2M124.7 114.7h23.2"/>
<path d="M124.7 114.6h23.2M124.7 114.5h23.2M124.7 114.4h23.2M124.7 114.3h23.2M124.7 114.2h23.2M124.7 114.1h23.2M124.7 114h23.2M124.7 113.9h23.2M124.7 113.8h23.2M124.7 113.7h23.2M124.7 113.6h23.2M124.7 113.5h23.2"/>
<path d="M124.8 113.5l-.1 .3M124.8 113.5h23.1M124.8 113.4h23.1M124.8 113.3h23.1M124.8 113.2h23.1M124.8 113.1h23.1M124.9 113.1h23M124.9 113h23M124.9 112.9l-.1 .6M124.9 112.9h23M125 112.8h22.9M125 112.7h22.9"/>
<path d="M125.1 112.7h22.8M125.1 112.6h22.8M125.2 112.5h22.7M125.3 112.4l-.4 .5M125.3 112.4h22.6M125.4 112.3h22.5M125.5 112.2h22.4M125.6 112.2h22.3M125.7 112.1h22.2M125.8 112.1l-.5 .3M125.8 112.1h22.1M125.9 112h22"/>
<path d="M126 112h21.9M126.3 111.9h21.6M139.8 111.9h8.1M140.3 111.8h7.6M140.5 111.8h7.4M140.7 111.7h7.2M140.8 111.7h7.1M140.9 111.6h7M141 111.5h6.9M141.2 111.5h6.7M141.2 111.4h6.7M141.4 111.4l-.9 .3-.9 .2h-13l-.8 .2"/>
<path d="M141.4 111.4h6.5M141.4 111.3h6.5M141.5 111.3h6.4M141.6 111.2h6.3M141.7 111.1h6.2M141.7 111.1l-.3 .3M141.8 111.1h6.1M141.8 111h6.1M141.9 111h6M141.9 110.9h6M142 110.8h5.9M142 110.8l-.3 .3"/>
<path d="M142.1 110.7h5.8M142.1 110.6h5.8M142.2 110.6h5.7M142.2 110.5h5.7M142.3 110.4h5.6M142.3 110.4l-.3 .4M142.4 110.3h5.5M142.4 110.2h5.5M142.5 110.2h5.4M142.5 110.1h5.4M142.5 110h5.4M142.5 110l-.2 .4"/>
<path d="M142.6 109.9h5.3M142.6 109.8h5.3M142.6 109.7h5.3M142.7 109.6h5.2M142.7 109.6l-.2 .4M142.7 109.5h5.2M142.7 109.4h5.2M142.7 109.3h5.2M142.8 109.2h5.1M142.8 109.2l-.1 .4M142.8 109.1h5.1M142.8 109h5.1"/>
<path d="M142.8 108.7v.5M142.8 108.7v-32.4h5.1v58.1M142.8 108.9h5.1M142.8 108.8h5.1M142.8 108.7h5.1M142.8 108.6h5.1M142.8 108.5h5.1M142.8 108.4h5.1M142.8 108.3h5.1M142.8 108.2h5.1M142.8 108.1h5.1M142.8 108h5.1"/>
<path d="M142.8 107.9h5.1M142.8 107.8h5.1M142.8 107.7h5.1M142.8 107.6h5.1M142.8 107.5h5.1M142.8 107.4h5.1M142.8 107.3h5.1M142.8 107.2h5.1M142.8 107.1h5.1M142.8 107h5.1M142.8 106.9h5.1M142.8 106.8h5.1"/>
<path d="M142.8 106.7h5.1M142.8 106.6h5.1M142.8 106.5h5.1M142.8 106.4h5.1M142.8 106.3h5.1M142.8 106.2h5.1M142.8 106.1h5.1M142.8 106h5.1M142.8 105.9h5.1M142.8 105.8h5.1M142.8 105.7h5.1M142.8 105.6h5.1"/>
<path d="M142.8 105.5h5.1M142.8 105.4h5.1M142.8 105.3h5.1M142.8 105.2h5.1M142.8 105.1h5.1M142.8 105h5.1M142.8 104.9h5.1M142.8 104.8h5.1M142.8 104.7h5.1M142.8 104.6h5.1M142.8 104.5h5.1M142.8 104.4h5.1"/>
<path d="M142.8 104.3h5.1M142.8 104.2h5.1M142.8 104.1h5.1M142.8 104h5.1M142.8 103.9h5.1M142.8 103.8h5.1M142.8 103.7h5.1M142.8 103.6h5.1M142.8 103.5h5.1M142.8 103.4h5.1M142.8 103.3h5.1M142.8 103.2h5.1"/>
<path d="M142.8 103.1h5.1M142.8 103h5.1M142.8 102.9h5.1M142.8 102.8h5.1M142.8 102.7h5.1M142.8 102.6h5.1M142.8 102.5h5.1M142.8 102.4h5.1M142.8 102.3h5.1M142.8 102.2h5.1M142.8 102.1h5.1M142.8 102h5.1"/>
<path d="M142.8 101.9h5.1M142.8 101.8h5.1M142.8 101.7h5.1M142.8 101.6h5.1M142.8 101.5h5.1M142.8 101.4h5.1M142.8 101.3h5.1M142.8 101.2h5.1M142.8 101.1h5.1M142.8 101h5.1M142.8 100.9h5.1M142.8 100.8h5.1"/>
<path d="M142.8 100.7h5.1M142.8 100.6h5.1M142.8 100.5h5.1M142.8 100.4h5.1M142.8 100.3h5.1M142.8 100.2h5.1M142.8 100.1h5.1M142.8 100h5.1M153 110.3h10.4M153 110.2l10.4 .1M153 110.2h10.4M153 110.1l10.3 .1"/>
<path d="M153 110.1h10.3M153 110h10.3M153 109.9h10.2M153 109.8h10.2M153 109.7h10.2M153 109.7h10.1M153 109.6l10.1 .1M153 109.6h10.1M153 109.5h10.1M153 109.4h10.1M153 109.4h10M153 109.3h10"/>
<path d="M153 109.2h10M153 109.1h10M153 109h10M153 108.9h10M153 108.8h10M153 108.7h10M153 108.6h10M153 108.5h10M153 108.4h10M153 108.3h10.1M153 108.2h10.1M153 108.1h10.1"/>
<path d="M153 108h10.2M153 107.9h10.2M153 107.6h10.3M153 107.4h10.5M153 107.3h10.5M153 106.2h43.2M153 106.1h43.2M153 106h43.2M153 105.9h43.2M153 105.8h43.2M153 105.7h43.2M153 105.6h43.2"/>
<path d="M153 105.5h43.2M153 105.4h43.2M153 105.3h43.2M153 105.2h43.2M153 105.1h43.2M153 105h43.2M153 104.9h43.2M153 104.8h43.2M153 104.7h43.2M153 104.6h43.2M153 104.5h43.2M153 104.4h43.2"/>
<path d="M153 104.3h43.2M153 104.2h43.2M153 104.1h43.2M153 104h43.2M153 103.9h43.2M153 103.8h43.2M153 103.7h43.2M153 103.6h43.2M153 103.5h43.2M153 103.4h43.2M153 103.3h43.2M153 103.2h43.2"/>
<path d="M153 103.1h43.2M153 103h43.2M153 102.9h43.2M153 102.8h43.2M153 102.7h43.2M153 102.6h43.2M153 102.5h43.2M153 102.4h43.2M153 102.3h43.2M153 102.2h43.2M153 102.1h43.2M153 102h43.2"/>
<path d="M153 101.9h43.2M153 101.8h43.2M153 101.7h43.2M153 101.6h43.2M153 101.5h43.2M153 101.4h43.2M153 101.3h43.2M153 101.2h43.2M153 101.1h43.2M153 101h43.2M153 100.9h43.2M153 100.8h43.2"/>
<path d="M153 100.7h43.2M153 100.6h43.2M153 100.5h43.2M153 100.4h43.2M153 100.3h43.2M153 100.2h43.2M153 100.1h43.2M153 100h43.2M153 110.3l.1 .7M153 110.6h10.7M153 110.6h10.6M153 110.5h10.6"/>
<path d="M153 110.4h10.5M153 110.7h10.8M153 110.7h10.7M153 110.8h10.9M153 110.8h10.8M153.1 110.9h10.8M153.1 111h11M153.1 110.9l10.9 .1M153.1 111l.1 .3M153.1 120h42.8M153.1 111l11.1 .1M153.1 119.9h42.8"/>
<path d="M153.1 111.1h11.1M153.1 111.1l11.2 .1M153.2 119.8h42.6M153.2 111.2h11.2M153.2 111.2l11.3 .1M153.2 119.7h42.6M153.2 119.7l-.1 .4M153.2 111.3h11.4M153.2 111.3l.2 .3M153.2 111.3l11.6 .1M153.3 119.6h42.4M153.3 119.5h42.4"/>
<path d="M153.3 111.4h11.8M153.3 111.5h11.9M153.4 119.4h42.2M153.4 111.5h42.2M153.4 111.6h42.2M153.4 111.6l.2 .3M153.4 119.3h42.2M153.4 111.6h42.1M153.5 119.3h42M153.5 119.2h42M153.5 111.7h42M153.5 119.2h41.9"/>
<path d="M153.6 111.8h41.8M153.6 111.8h41.7M153.6 119.1h41.8M153.6 119.1l-.4 .6M153.6 119.1h41.7M153.6 111.9l.6 .4 1 .2M153.6 111.9h41.7M153.7 119h41.6M153.7 111.9h41.5M153.7 119h41.5M153.8 118.9h41.4M153.8 112h41.3"/>
<path d="M153.8 118.9h41.3M153.9 118.8h41.1M153.9 112.1h41.1M154 112.1h40.9M154 118.7h40.9M154.1 112.2h40.7M154.1 118.6h40.7M154.1 118.6l-.5 .5M154.2 112.2h40.5M154.2 118.6h40.5M154.3 112.3h40.3M154.3 118.5h40.3"/>
<path d="M154.4 118.5h40.1M154.4 112.4h40.1M154.5 118.4h39.9M154.6 112.4h39.7M154.6 118.4h39.6M154.7 112.5h39.4M154.8 118.3h39.3M154.8 118.3l38.5-.1 1.2 .3M154.8 118.3l-.7 .3M155 118.3h38.8M163 109.2a2.64 2.64 0 0 0 1.6 2.1M163 108.4h-10"/>
<path d="M163.1 108.2h-10.1M163.1 108.1h-10.1M163.2 107.9h-10.2M163.2 107.8l-10.2 .1M163.2 107.8h-10.2M163.3 107.7l-10.3 .1M163.3 107.7h-10.3M163.3 107.6l-10.3 .1M163.4 107.5l-10.4 .1M163.4 107.5h-10.4M163.4 107.4l-10.4 .1M163.5 107.3h-10.5"/>
<path d="M163.6 107.2l-10.6 .1M163.6 107.2h-10.6M163.7 107.1h-10.7M163.8 107h-10.8M163.9 106.9h-10.9M163.9 106.8l-10.9 .1M164 106.8h-11M164.1 106.7l-11.1 .1M164.2 106.7h-11.2M164.3 106.6l-11.3 .1M164.4 106.6h-11.4M164.4 106.5l-11.4 .1"/>
<path d="M164.5 106.5h-11.5M164.6 106.4a2.65 2.65 0 0 0-1.6 2.8M164.6 111.3l.7 .2M164.6 106.4h-11.6M164.9 106.4h-11.9M165 106.3h-12M165.2 106.3h-12.2M165.3 106.2l-.7 .2M166 106.2l.6 .2M166 106.3h16.9M166 111.5h16.8M166.2 111.4h16.5"/>
<path d="M166.2 106.3h16.4M166.4 106.4h16.1M166.4 111.4h16.1M166.6 106.4h15.6M166.6 111.3h15.6M166.6 106.4l1.1 .9M166.6 111.3l-.6 .2M166.7 111.3h15.5M166.7 106.5h15.5M166.8 111.2h15.3M166.8 106.5h15.2M166.9 106.6h15.1"/>
<path d="M166.9 111.2h15.1M167 106.6h14.9M167 111.1h14.8M167.1 106.7h14.7M167.1 111.1h14.7M167.2 106.7h14.5M167.2 111h14.5M167.3 111h14.3M167.3 106.8h14.3M167.3 110.9h14.2M167.3 106.8h14.2M167.4 110.8h14.1"/>
<path d="M167.4 106.9h14.1M167.4 110.8h14M167.4 107h14M167.5 110.7h13.9M167.5 107h13.9M167.5 110.7h13.8M167.5 107.1h13.9M167.6 110.6h13.7M167.6 107.1h13.7M167.6 110.6h13.6M167.6 107.2h13.6M167.7 110.5h13.5"/>
<path d="M167.7 107.2h13.5M167.7 107.3l.4 .6M167.7 110.5l-1.1 .8M167.7 110.4h13.4M167.7 107.3h13.4M167.8 110.4h13.3M167.8 107.3h13.3M167.8 107.4h13.3M167.8 110.3l13.3 .1M167.8 110.3h13.2M167.8 107.4h13.2M167.9 110.3h13.1"/>
<path d="M167.9 110.2h13.1M167.9 107.5h13.1M167.9 107.6h13.1M167.9 110.1l13.1 .1M167.9 107.6h13M168 110.1h12.9M168 110h12.9M168 107.7h12.9M168 109.9h12.8M168 107.8h12.8M168.1 107.8h12.7M168.1 109.9h12.7"/>
<path d="M168.1 109.8h12.7M168.1 107.9h12.7M168.1 107.9l.2 .6M168.1 109.9l-.4 .6M168.1 109.7h12.7M168.1 109.7h12.6M168.1 108.1h12.6M168.1 108h12.7M168.1 109.6h12.6M168.2 109.5l12.5 .1M168.2 109.5h12.5M168.2 108.2h12.5"/>
<path d="M168.2 109.4h12.5M168.2 108.3h12.5M168.2 108.4h12.5M168.2 109.3h12.4M168.2 108.4h12.4M168.3 108.5v.7M168.3 109.2l12.3 .1M168.3 109.2h12.3M168.3 109.1h12.3M168.3 109h12.3M168.3 108.9h12.3M168.3 108.8h12.3"/>
<path d="M168.3 108.7h12.3M168.3 108.6h12.3M168.3 108.5h12.3M168.3 109.2l-.2 .7M180.6 108.5v.7M180.6 109.2l.2 .7M180.8 107.9l-.2 .6M180.8 109.9l.3 .6M180.9 107.7l-12.9 .1M181 107.5h-13.1M181.1 107.3l-.3 .6M181.1 110.5l.5 .5"/>
<path d="M181.6 111l.6 .3M182.2 106.4l-1.1 .9M182.2 111.3l.7 .2M182.9 106.2l-.7 .2M183.6 106.2l.7 .2M183.6 106.3h12.6M183.9 106.3h12.3M184 106.4h12.2M184.2 106.4h12M184.3 111.3h11.5M184.3 106.4l.5 .4M184.3 111.3l-.7 .2"/>
<path d="M184.3 106.5h11.9M184.4 106.5h11.8M184.5 106.6h11.7M184.6 106.6h11.6M184.7 106.7h11.5M184.8 111h11.1M184.8 106.7h11.4M184.8 106.8l.9 1.1M184.8 111l-.5 .3M184.9 106.8h11.3M185 106.9h11.2M185 107h11.2"/>
<path d="M185.1 107h11.1M185.1 110.7h10.9M185.1 107.1h11.1M185.2 107.1h11M185.3 107.2h10.9M185.3 110.5h10.8M185.4 110.4h10.7M185.4 107.3h10.8M185.4 107.4h10.8M185.4 110.3h10.7M185.5 110.2h10.6M185.5 107.5h10.7"/>
<path d="M185.5 107.6h10.7M185.5 110.1h10.6M185.6 110h10.6M185.6 107.7h10.6M185.7 109.9h10.5M185.7 107.8h10.5M185.7 107.9h10.5M185.7 107.9l.2 .6M185.7 109.9l-.9 1.1M185.7 109.8h10.5M185.7 109.7h10.5M185.7 108.1h10.5"/>
<path d="M185.7 108h10.5M185.8 109.6h10.4M185.8 108.1h10.4M185.8 109.5h10.4M185.8 108.2h10.4M185.8 108.3h10.4M185.8 109.4h10.4M185.8 108.4h10.4M185.8 109.3h10.4M185.9 108.5v.7M185.9 109.2h10.3M185.9 109.1h10.3"/>
<path d="M185.9 109h10.3M185.9 108.9h10.3M185.9 108.8h10.3M185.9 108.7h10.3M185.9 108.6h10.3M185.9 108.5h10.3M185.9 109.2l-.2 .7M194.3 112.4l-.7 .1M194.5 118.5l.7 .4M195 112.1l-.7 .3M195.2 118.9l.5 .6M195.3 111.9l-.3 .2"/>
<path d="M195.5 111.7h-42M195.5 111.6l-.2 .3M195.7 111.5h-12.1M195.7 119.5l.2 .4M195.7 111.4h-11.9M195.7 111.3l-11.7 .1M195.7 111.3l-.2 .3M195.8 111.2l-11.5 .1M195.8 111.2h-11.4M195.9 111.1l-11.4 .1M195.9 111.1h-11.3M195.9 119.9l.2 .8"/>
<path d="M195.9 111l-11.2 .1M195.9 111l-.2 .3M196 110.9l-11.1 .1M196 110.9h-11.1M196 110.8h-11M196 110.7h-10.9M196 110.7l-.1 .3M196.1 110.6h-10.9M196.1 110.6h-10.8M196.1 110.3l-10.7 .1M196.1 110.3l-.1 .4M196.2 110.1h-10.6"/>
<path d="M196.2 110l-.1 .3M201.2 111.8h24.7M201.2 120h24.7M201.2 119.9h24.7M201.2 119.8h24.7M201.2 119.7h24.7M201.2 119.6h24.7M201.2 119.5h24.7M201.2 119.4h24.7M201.2 119.3h24.7M201.2 119.2h24.7M201.2 119.1h24.7"/>
<path d="M201.2 119h24.7M201.2 118.9h24.7M201.2 118.8h24.7M201.2 118.7h24.7M201.2 118.6h24.7M201.2 118.5h24.7M201.2 118.4h24.7M201.2 118.3h24.7M201.2 118.2h24.7M201.2 118.1h24.7M201.2 118h24.7M201.2 117.9h24.7"/>
<path d="M201.2 117.8h24.7M201.2 117.7h24.7M201.2 117.6h24.7M201.2 117.5h24.7M201.2 117.4h24.7M201.2 117.3h24.7M201.2 117.2h24.7M201.2 117.1h24.7M201.2 117h24.7M201.2 116.9h24.7M201.2 116.8h24.7M201.2 116.7h24.7"/>
<path d="M201.2 116.6h24.7M201.2 116.5h24.7M201.2 116.4h24.7M201.2 116.3h24.7M201.2 116.2h24.7M201.2 116.1h24.7M201.2 116h24.7M201.2 115.9h24.7M201.2 115.8h24.7M201.2 115.7h24.7M201.2 115.6h24.7M201.2 115.5h24.7"/>
<path d="M201.2 115.4h24.7M201.2 115.3h24.7M201.2 115.2h24.7M201.2 115.1h24.7M201.2 115h24.7M201.2 114.9h24.7M201.2 114.8h24.7M201.2 114.7h24.7M201.2 114.6h24.7M201.2 114.5h24.7M201.2 114.4h24.7M201.2 114.3h24.7"/>
<path d="M201.2 114.2h24.7M201.2 114.1h24.7M201.2 114h24.7M201.2 113.9h24.7M201.2 113.8h24.7M201.2 113.7h24.7M201.2 113.6h24.7M201.2 113.5h24.7M201.2 113.4h24.7M201.2 113.3h24.7M201.2 113.2h24.7M201.2 113.1h24.7"/>
<path d="M201.2 113h24.7M201.2 112.9h24.7M201.2 112.8h24.7M201.2 112.7h24.7M201.2 112.6h24.7M201.2 112.5h24.7M201.2 112.4h24.7M201.2 112.3h24.7M201.2 112.2h24.7M201.2 112.1h24.7M201.2 112h24.7M201.2 111.9h24.7"/>
<path d="M201.2 111.7h24.7M201.2 111.6h24.7M201.2 111.5h24.7M201.2 111.5h18.8M201.2 111.4h18.6M201.2 111.3l18.4 .1M201.2 111.3h18.2M201.2 111.2l18.1 .1M201.2 111.2h18M201.2 111.1l17.9 .1M201.2 111.1h17.8M201.2 111l17.7 .1"/>
<path d="M201.2 111h17.6M201.2 110.9l17.6 .1M201.2 110.9h17.5M201.2 110.8h17.5M201.2 110.8h17.4M201.2 110.7h17.3M201.2 110.6h17.2M201.2 110.5h17.1M201.2 110.4h17.1M201.2 110.4h17M201.2 110.3h17M201.2 110.2h16.9"/>
<path d="M201.2 110.1h16.9M201.2 110h16.8M201.2 109.9h16.8M201.2 109.9h16.7M201.2 109.8h16.7M201.2 109.7l16.7 .1M201.2 109.7h16.7M201.2 109.6l16.7 .1M201.2 109.6h16.7M201.2 109.5h16.6M201.2 109.4l16.6 .1M201.2 109.4h16.6"/>
<path d="M201.2 109.3l16.6 .1M201.2 109.3h16.6M201.2 109.2h16.6M201.2 109.1h16.6M201.2 109h16.6M201.2 108.9h16.6M201.2 108.8h16.6M201.2 108.7h16.6M201.2 108.6h16.6M201.2 108.5h16.6M201.2 108.3h16.6M201.2 108.2h16.6"/>
<path d="M201.2 108h16.7M201.2 107.9h16.7M201.2 107.8h16.8M201.2 107.7h16.8M201.2 107.6h16.9M201.2 107.5h16.9M201.2 107.3h17.1M201.2 107h17.4M201.2 106.2h24.7M201.2 106.1h24.7M201.2 106h24.7M201.2 105.9h24.7"/>
<path d="M201.2 105.8h24.7M201.2 105.7h24.7M201.2 105.6h24.7M201.2 105.5h24.7M201.2 105.4h24.7M201.2 105.3h24.7M201.2 105.2h24.7M201.2 105.1h24.7M201.2 105h24.7M201.2 104.9h24.7M201.2 104.8h24.7M201.2 104.7h24.7"/>
<path d="M201.2 104.6h24.7M201.2 104.5h24.7M201.2 104.4h24.7M201.2 104.3h24.7M201.2 104.2h24.7M201.2 104.1h24.7M201.2 104h24.7M201.2 103.9h24.7M201.2 103.8h24.7M201.2 103.7h24.7M201.2 103.6h24.7M201.2 103.5h24.7"/>
<path d="M201.2 103.4h24.7M201.2 103.3h24.7M201.2 103.2h24.7M201.2 103.1h24.7M201.2 103h24.7M201.2 102.9h24.7M201.2 102.8h24.7M201.2 102.7h24.7M201.2 102.6h24.7M201.2 102.5h24.7M201.2 102.4h24.7M201.2 102.3h24.7"/>
<path d="M201.2 102.2h24.7M201.2 102.1h24.7M201.2 102h24.7M201.2 101.9h24.7M201.2 101.8h24.7M201.2 101.7h24.7M201.2 101.6h24.7M201.2 101.5h24.7M201.2 101.4h24.7M201.2 101.3h24.7M201.2 101.2h24.7M201.2 101.1h24.7"/>
<path d="M201.2 101h24.7M201.2 100.9h24.7M201.2 100.8h24.7M201.2 100.7h24.7M201.2 100.6h24.7M201.2 100.5h24.7M201.2 100.4h24.7M201.2 100.3h24.7M201.2 100.2h24.7M201.2 100.1h24.7M201.2 100h24.7M217.8 108.5v.7"/>
<path d="M217.8 109.2l.1 .7M217.8 108.4l-16.6 .1M217.8 108.4h-16.6M217.8 108.3h-16.6M217.9 108.1h-16.7M217.9 107.9l-16.7 .1M217.9 107.9l-.1 .6M217.9 109.9l.9 1.1M218 107.8h-16.8M218 107.7l-16.8 .1M218.1 107.6l-16.9 .1M218.1 107.5l-16.9 .1"/>
<path d="M218.2 107.4h-17M218.2 107.3h-17M218.3 107.2l-17.1 .1M218.4 107.2h-17.2M218.4 107.1h-17.2M218.5 107.1h-17.3M218.5 107h-17.3M218.7 106.9h-17.5M218.7 106.8l-17.5 .1M218.8 106.8h-17.6M218.8 106.8l-.9 1.1M218.8 111l.6 .3"/>
<path d="M218.8 106.7l-17.6 .1M218.9 106.7h-17.7M219 106.6l-17.8 .1M219.1 106.6h-17.9M219.2 106.5l-18 .1M219.3 106.5h-18.1M219.4 106.4l-.6 .4M219.4 111.3l.6 .2M219.4 106.4h-18.2M219.6 106.4h-18.4M219.8 106.3h-18.6M220 106.3h-18.8"/>
<path d="M220 106.2l-.6 .2M220.7 106.2l.7 .2M220.7 106.3h5.2M220.8 111.5h5.1M220.9 111.4h5M221 106.3h4.9M221.1 106.4h4.8M221.2 111.4h4.7M221.4 106.4h4.5M221.4 111.3h4.5M221.4 106.4l1.1 .9M221.4 111.3l-.7 .2"/>
<path d="M221.5 111.3h4.4M221.5 106.5h4.4M221.6 111.2h4.3M221.6 106.5h4.3M221.7 111.2h4.2M221.7 106.6h4.2M221.8 106.6h4.1M221.8 111.1h4.1M221.8 106.7h4.1M221.9 106.7h4M222 111h3.9M222 106.8h3.9"/>
<path d="M222.1 110.9h3.8M222.1 106.8h3.8M222.1 110.8h3.8M222.1 106.9h3.8M222.2 110.8h3.7M222.2 107h3.7M222.2 110.7h3.7M222.3 107.1h3.6M222.3 110.7h3.6M222.3 110.6h3.6M222.4 110.6h3.5M222.4 107.2h3.5"/>
<path d="M222.4 110.5h3.5M222.5 107.3h3.4M222.5 107.3l.3 .6M222.5 110.5l-1.1 .8M222.5 110.4h3.4M222.5 107.4h3.4M222.6 110.3h3.3M222.6 107.4h3.3M222.6 107.5h3.3M222.7 110.2h3.2M222.7 107.6h3.2M222.7 110.1h3.2"/>
<path d="M222.7 110h3.2M222.7 107.7h3.2M222.8 110h3.1M222.8 107.7h3.1M222.8 109.9h3.1M222.8 107.8h3.1M222.8 109.8h3.1M222.8 107.9h3.1M222.8 107.9l.2 .6M222.8 109.9l-.3 .6M222.9 109.7h3M222.9 108h3"/>
<path d="M222.9 107.9h3M222.9 108.1h3M222.9 109.6h3M222.9 108.2h3M222.9 109.5h3M222.9 109.4h3M222.9 108.3h3M223 109.4h2.9M223 109.3h2.9M223 108.4h2.9M223 108.5h2.9M223 108.5v.7"/>
<path d="M223 109.2h2.9M223 109.1h2.9M223 109h2.9M223 108.9h2.9M223 108.8h2.9M223 108.7h2.9M223 108.6h2.9M223 109.2l-.2 .7M68 138.2h15.1M68 140h15.1M68 139.9h15.1M68 139.8h15.1"/>
<path d="M68 139.7h15.1M68 139.6h15.1M68 139.5h15.1M68 139.4h15.1M68 139.3h15.1M68 139.2h15.1M68 139.1h15.1M68 139h15.1M68 138.9h15.1M68 138.8h15.1M68 138.7h15.1M68 138.6h15.1"/>
<path d="M68 138.5h15.1M68 138.4h15.1M68 138.3h15.1M68 138.1h15.1M68 138h15.1M68 137.9h15.1M68 137.8h15.1M68 137.7h15.1M68 137.6h15.1M68 137.5h15.1M68 137.4h15.1M68 137.3h15.1"/>
<path d="M68 137.2h15.1M68 137.1h15.1M68 137h15.1M68 136.9h15.1M68 136.8h15.1M68 136.7h15.1M68 136.6h15.1M68 136.5h15.1M68 136.4h15.1M68 136.3h15.1M68 136.2h15.1M68 136.1h15.1"/>
<path d="M68 136h15.1M68 135.9h15.1M68 135.8h15.1M68 135.7h15.1M68 135.6h15.1M68 135.5h15.1M68 135.4h15.1M68 135.3h15.1M68 135.2h15.1M68 135.1h15.1M68 135h15.1M68 134.9h15.1"/>
<path d="M68 134.8h15.1M68 134.7h15.1M68 134.6h15.1M68 134.5h15.1M68 134.4h15.1M68 134.3h15.1M68 134.2h15.1M68 134.1h15.1M68 134h15.1M68 133.9h15.1M68 133.8h15.1M68 133.7h15.1"/>
<path d="M68 133.6h15.1M68 133.5h15.1M68 133.4h15.1M68 133.3h15.1M68 133.2h15.1M68 133.1h15.1M68 133h15.1M68 132.9h15.1M68 132.8h15.1M68 132.7h15.1M68 132.6h15.1M68 132.5h15.1"/>
<path d="M68 132.4h15.1M68 132.3h15.1M68 132.2h15.1M68 132.1h15.1M68 132h15.1M68 131.9h15.1M68 131.8h15.1M68 131.7h15.1M68 131.6h15.1M68 131.5h15.1M68 131.4h15.1M68 131.3h15.1"/>
<path d="M68 131.2h15.1M68 131.1h15.1M68 131h15.1M68 130.9h15.1M68 130.8h15.1M68 130.7h15.1M68 130.6h15.1M68 130.5h15.1M68 130.4h15.1M68 130.3h15.1M68 130.2h15.1M68 130.1h15.1"/>
<path d="M68 130h15.1M68 129.9h15.1M68 129.8h15.1M68 129.7h15.1M68 129.6h15.1M68 129.5h15.1M68 129.4h15.1M68 129.3h15.1M68 129.2h15.1M68 129.1h15.1M68 129h15.1M68 128.9h15.1"/>
<path d="M68 128.8h15.1M68 128.7h15.1M68 128.6h15.1M68 128.5h15.1M68 128.4h15.1M68 128.3h15.1M68 128.2h15.1M68 128.1h15.1M68 128h15.1M68 127.9h15.1M68 127.8h15.1M68 127.7h15.1"/>
<path d="M68 127.6h15.1M68 127.5h15.1M68 127.4h15.1M68 127.3h15.1M68 127.2h15.1M68 127.1h15.1M68 127h15.1M68 126.9h15.1M68 126.8h15.1M68 126.7h15.1M68 126.6h15.1M68 126.5h15.1"/>
<path d="M68 126.4h15.1M68 126.3h15.1M68 126.2h15.1M68 126.1h15.1M68 126h15.1M68 125.9h15.1M68 125.8h15.1M68 125.7h15.1M68 125.6h15.1M68 125.5h15.1M68 125.4h15.1M68 125.3h15.1"/>
<path d="M68 125.2h15.1M68 125.1h15.1M68 125h15.1M68 124.9h15.1M68 124.8h15.1M68 124.7h15.1M68 124.6h15.1M68 124.5h15.1M68 124.4h15.1M68 124.3h15.1M68 124.2h15.1M68 124.1h15.1"/>
<path d="M68 124h15.1M68 123.9h15.1M68 123.8h15.1M68 123.7h15.1M68 123.6h15.1M68 123.5h15.1M68 123.4h15.1M68 123.3h15.1M68 123.2h15.1M68 123.1h15.1M68 123h15.1M68 122.9h15.1"/>
<path d="M68 122.8h15.1M68 122.7h15.1M68 122.6h15.1M68 122.5h15.1M68 122.4h15.1M68 122.3h15.1M68 122.2h15.1M68 122.1h15.1M68 122h15.1M68 121.9h15.1M68 121.8h15.1M68 121.7h15.1"/>
<path d="M68 121.6h15.1M68 121.5h15.1M68 121.4h15.1M68 121.3h15.1M68 121.2h15.1M68 121.1h15.1M68 121h15.1M68 120.9h15.1M68 120.8h15.1M68 120.7h15.1M68 120.6h15.1M68 120.5h15.1"/>
<path d="M68 120.4h15.1M68 120.3h15.1M68 120.2h15.1M68 120.1h15.1M87 138.2h10.1M87 140h10.1M87 139.9h10.1M87 139.8h10.1M87 139.7h10.1M87 139.6h10.1M87 139.5h10.1M87 139.4h10.1"/>
<path d="M87 139.3h10.1M87 139.2h10.1M87 139.1h10.1M87 139h10.1M87 138.9h10.1M87 138.8h10.1M87 138.7h10.1M87 138.6h10.1M87 138.5h10.1M87 138.4h10.1M87 138.3h10.1M87 138.1h10.1"/>
<path d="M87 138h10.1M87 137.9h10.1M87 137.8h10.1M87 137.7h10.1M87 137.6h10.1M87 137.5h10.1M87 137.4h10.1M87 137.3h10.1M87 137.2h10.1M87 137.1h10.1M87 137h10.1M87 136.9h10.1"/>
<path d="M87 136.8h10.1M87 136.7h10.1M87 136.6h10.1M87 136.5h10.1M87 136.4h10.1M87 136.3h10.1M87 136.2h10.1M87 136.1h10.1M87 136h10.1M87 135.9h10.1M87 135.8h10.1M87 135.7h10.1"/>
<path d="M87 135.6h10.1M87 135.5h10.1M87 135.4h10.1M87 135.3h10.1M87 135.2h10.1M87 135.1h10.1M87 135h10.1M87 134.9h10.1M87 134.8h10.1M87 134.7h10.1M87 134.6h10.1M87 134.5h10.1"/>
<path d="M87 134.4h10.1M87 134.3h10.1M87 134.2h10.1M87 134.1h10.1M87 134h10.1M87 133.9h10.1M87 133.8h10.1M87 133.7h10.1M87 133.6h10.1M87 133.5h10.1M87 133.4h10.1M87 133.3h10.1"/>
<path d="M87 133.2h10.1M87 133.1h10.1M87 133h10.1M87 132.9h10.1M87 132.8h10.1M87 132.7h10.1M87 132.6h10.1M87 132.5h10.1M87 132.4h10.1M87 132.3h10.1M87 132.2h10.1M87 132.1h10.1"/>
<path d="M87 132h10.1M87 131.9h10.1M87 131.8h10.1M87 131.7h10.1M87 131.6h10.1M87 131.5h10.1M87 131.4h10.1M87 131.3h10.1M87 131.2h10.1M87 131.1h10.1M87 131h10.1M87 130.9h10.1"/>
<path d="M87 130.8h10.1M87 130.7h10.1M87 130.6h10.1M87 130.5h10.1M87 130.4h10.1M87 130.3h10.1M87 130.2h10.1M87 130.1h10.1M87 130h10.1M87 129.9h10.1M87 129.8h10.1M87 129.7h10.1"/>
<path d="M87 129.6h10.1M87 129.5h10.1M87 129.4h10.1M87 129.3h10.1M87 129.2h10.1M87 129.1h10.1M87 129h10.1M87 128.9h10.1M87 128.8h10.1M87 128.7h10.1M87 128.6h10.1M87 128.5h10.1"/>
<path d="M87 128.4h10.1M87 128.3h10.1M87 128.2h10.1M87 128.1h10.1M87 128h10.1M87 127.9h10.1M87 127.8h10.1M87 127.7h10.1M87 127.6h10.1M87 127.5h10.1M87 127.4h10.1M87 127.3h10.1"/>
<path d="M87 127.2h10.1M87 127.1h10.1M87 127h10.1M87 126.9h10.1M87 126.8h10.1M87 126.7h10.1M87 126.6h10.1M87 126.5h10.1M87 126.4h10.1M87 126.3h10.1M87 126.2h10.1M87 126.1h10.1"/>
<path d="M87 126h10.1M87 125.9h10.1M87 125.8h10.1M87 125.7h10.1M87 125.6h10.1M87 125.5h10.1M87 125.4h10.1M87 125.3h10.1M87 125.2h10.1M87 125.1h10.1M87 125h10.1M87 124.9h10.1"/>
<path d="M87 124.8h10.1M87 124.7h10.1M87 124.6h10.1M87 124.5h10.1M87 124.4h10.1M87 124.3h10.1M87 124.2h10.1M87 124.1h10.1M87 124h10.1M87 123.9h10.1M87 123.8h10.1M87 123.7h10.1"/>
<path d="M87 123.6h10.1M87 123.5h10.1M87 123.4h10.1M87 123.3h10.1M87 123.2h10.1M87 123.1h10.1M87 123h10.1M87 122.9h10.1M87 122.8h10.1M87 122.7h10.1M87 122.6h10.1M87 122.5h10.1"/>
<path d="M87 122.4h10.1M87 122.3h10.1M87 122.2h10.1M87 122.1h10.1M87 122h10.1M87 121.9h10.1M87 121.8h10.1M87 121.7h10.1M87 121.6h10.1M87 121.5h10.1M87 121.4h10.1M87 121.3h10.1"/>
<path d="M87 121.2h10.1M87 121.1h10.1M87 121h10.1M87 120.9h10.1M87 120.8h10.1M87 120.7h10.1M87 120.6h10.1M87 120.5h10.1M87 120.4h10.1M87 120.3h10.1M87 120.2h10.1M87 120.1h10.1"/>
<path d="M100.9 138.2h13.7M100.9 140h13.7M100.9 139.9h13.7M100.9 139.8h13.7M100.9 139.7h13.7M100.9 139.6h13.7M100.9 139.5h13.7M100.9 139.4h13.7M100.9 139.3h13.7M100.9 139.2h13.7M100.9 139.1h13.7M100.9 139h13.7"/>
<path d="M100.9 138.9h13.7M100.9 138.8h13.7M100.9 138.7h13.7M100.9 138.6h13.7M100.9 138.5h13.7M100.9 138.4h13.7M100.9 138.3h13.7M100.9 138.1h13.7M100.9 138h13.7M100.9 137.9h13.7M100.9 137.8h13.7M100.9 137.7h13.7"/>
<path d="M100.9 137.6h13.7M100.9 137.5h13.7M100.9 137.4h13.7M100.9 137.3h13.7M100.9 137.2h13.7M100.9 137.1h13.7M100.9 137h13.7M100.9 136.9h13.7M100.9 136.8h13.7M100.9 136.7h13.7M100.9 136.6h13.7M100.9 136.5h13.7"/>
<path d="M100.9 136.4h13.7M100.9 136.3h13.7M100.9 136.2h13.7M100.9 136.1h13.7M100.9 136h13.7M100.9 135.9h13.7M100.9 135.8h13.7M100.9 135.7h13.7M100.9 135.6h13.7M100.9 135.5h13.7M100.9 135.4h13.7M100.9 135.3h13.7"/>
<path d="M100.9 135.2h13.7M100.9 135.1h13.7M100.9 135h13.7M100.9 134.9h13.7M100.9 134.8h13.7M100.9 134.7h13.7M100.9 134.6h13.7M100.9 134.5h13.7M100.9 134.4h13.7M100.9 134.3h13.7M100.9 134.2h13.7M100.9 134.1h13.7"/>
<path d="M100.9 134h13.7M100.9 133.9h13.7M100.9 133.8h13.7M100.9 133.7h13.7M100.9 133.6h13.7M100.9 133.5h13.7M100.9 133.4h13.7M100.9 133.3h13.7M100.9 133.2h13.7M100.9 133.1h13.7M100.9 133h13.7M100.9 132.9h13.7"/>
<path d="M100.9 132.8h13.7M100.9 132.7h13.7M100.9 132.6h13.7M100.9 132.5h13.7M100.9 132.4h13.7M100.9 132.3h13.7M100.9 132.2h13.7M100.9 132.1h13.7M100.9 132h13.7M100.9 131.9h13.7M100.9 131.8h13.7M100.9 131.7h13.7"/>
<path d="M100.9 131.6h13.7M100.9 131.5h13.7M100.9 131.4h13.7M100.9 131.3h13.7M100.9 131.2h13.7M100.9 131.1h13.7M100.9 131h13.7M100.9 130.9h13.7M100.9 130.8h13.7M100.9 130.7h13.7M100.9 130.6h13.7M100.9 130.5h13.7"/>
<path d="M100.9 130.4h13.7M100.9 130.3h13.7M100.9 130.2h13.7M100.9 130.1h13.7M100.9 130h13.7M100.9 129.9h13.7M100.9 129.8h13.7M100.9 129.7h13.7M100.9 129.6h13.7M100.9 129.5h13.7M100.9 129.4h13.7M100.9 129.3h13.7"/>
<path d="M100.9 129.2h13.7M100.9 129.1h13.7M100.9 129h13.7M100.9 128.9h13.7M100.9 128.8h13.7M100.9 128.7h13.7M100.9 128.6h13.7M100.9 128.5h13.7M100.9 128.4h13.7M100.9 128.3h13.7M100.9 128.2h13.7M100.9 128.1h13.7"/>
<path d="M100.9 128h13.7M100.9 127.9h13.7M100.9 127.8h13.7M100.9 127.7h13.7M100.9 127.6h13.7M100.9 127.5h13.7M100.9 127.4h13.7M100.9 127.3h13.7M100.9 127.2h13.7M100.9 127.1h13.7M100.9 127h13.7M100.9 126.9h13.7"/>
<path d="M100.9 126.8h13.7M100.9 126.7h13.7M100.9 126.6h13.7M100.9 126.5h13.7M100.9 126.4h13.7M100.9 126.3h13.7M100.9 126.2h13.7M100.9 126.1h13.7M100.9 126h13.7M100.9 125.9h13.7M100.9 125.8h13.7M100.9 125.7h13.7"/>
<path d="M100.9 125.6h13.7M100.9 125.5h13.7M100.9 125.4h13.7M100.9 125.3h13.7M100.9 125.2h13.7M100.9 125.1h13.7M100.9 125h13.7M100.9 124.9h13.7M100.9 124.8h13.7M100.9 124.7h13.7M100.9 124.6h13.7M100.9 124.5h13.7"/>
<path d="M100.9 124.4h13.7M100.9 124.3h13.7M100.9 124.2h13.7M100.9 124.1h13.7M100.9 124h13.7M100.9 123.9h13.7M100.9 123.8h13.7M100.9 123.7h13.7M100.9 123.6h13.7M100.9 123.5h13.7M100.9 123.4h13.7M100.9 123.3h13.7"/>
<path d="M100.9 123.2h13.7M100.9 123.1h13.7M100.9 123h13.7M100.9 122.9h13.7M100.9 122.8h13.7M100.9 122.7h13.7M100.9 122.6h13.7M100.9 122.5h13.7M100.9 122.4h13.7M100.9 122.3h13.7M100.9 122.2h13.7M100.9 122.1h13.7"/>
<path d="M100.9 122h13.7M100.9 121.9h13.7M100.9 121.8h13.7M100.9 121.7h13.7M100.9 121.6h13.7M100.9 121.5h13.7M100.9 121.4h13.7M100.9 121.3h13.7M100.9 121.2h13.7M100.9 121.1h13.7M100.9 121h13.7M100.9 120.9h13.7"/>
<path d="M100.9 120.8h13.7M100.9 120.7h13.7M100.9 120.6h13.7M100.9 120.5h13.7M100.9 120.4h13.7M100.9 120.3h13.7M100.9 120.2h13.7M100.9 120.1h13.7M124.7 138.2h101.2v13.3h-20.8l-.1-.3M124.7 140h101.2M124.7 139.9h101.2M124.7 139.8h101.2"/>
<path d="M124.7 139.7h101.2M124.7 139.6h101.2M124.7 139.5h101.2M124.7 139.4h101.2M124.7 139.3h101.2M124.7 139.2h101.2M124.7 139.1h101.2M124.7 139h101.2M124.7 138.9h101.2M124.7 138.8h101.2M124.7 138.7h101.2M124.7 138.6h101.2"/>
<path d="M124.7 138.5h101.2M124.7 138.4h101.2M124.7 138.3h101.2M124.7 138.2h26.8M124.7 138.1l26.3 .1M124.7 138.1h26M124.7 138h25.9M124.7 138h25.7M124.7 137.9h25.6M124.7 137.9h25.5M124.7 137.8h25.4M124.7 137.8h25.2"/>
<path d="M124.7 137.7h25.2M124.7 137.6l25.1 .1M124.7 137.6h25M124.7 137.5l24.9 .1M124.7 137.5h24.8M124.7 137.4l24.7 .1M124.7 137.4h24.7M124.7 137.3l24.6 .1M124.7 137.3h24.5M124.7 137.2h24.5M124.7 137.2h24.4M124.7 137.1h24.4"/>
<path d="M124.7 137.1h24.3M124.7 137h24.2M124.7 136.9l24.2 .1M124.7 136.9h24.2M124.7 136.8l24.1 .1M124.7 136.8h24.1M124.7 136.7h24M124.7 136.6h23.9M124.7 136.5h23.9M124.7 136.5h23.8M124.7 136.4h23.8M124.7 136.3h23.7"/>
<path d="M124.7 136.2l23.7 .1M124.7 136.2h23.7M124.7 136.1l23.7 .1M124.7 136.1h23.6M124.7 136l23.6 .1M124.7 136h23.6M124.7 135.9l23.5 .1M124.7 135.9h23.5M124.7 135.8h23.5M124.7 135.7l23.5 .1M124.7 135.7h23.4M124.7 135.6l23.4 .1"/>
<path d="M124.7 135.6h23.4M124.7 135.5h23.4M124.7 135.4h23.3M124.7 135.3h23.3M124.7 135.2h23.3M124.7 135.1h23.3M124.7 135h23.3M124.7 134.9h23.2M124.7 134.8h23.2M124.7 134.7h23.2M124.7 134.6h23.2M124.7 134.5h23.2"/>
<path d="M124.7 134.4h23.2M124.7 134.3h23.2M124.7 134.2h23.2M124.7 134.1h23.2M124.7 134h23.2M124.7 133.9h23.2M124.7 133.8h23.2M124.7 133.7h23.2M124.7 133.6h23.2M124.7 133.5h23.2M124.7 133.4h23.2M124.7 133.3h23.2"/>
<path d="M124.7 133.2h23.2M124.7 133.1h23.2M124.7 133h23.2M124.7 132.9h23.2M124.7 132.8h23.2M124.7 132.7h23.2M124.7 132.6h23.2M124.7 132.5h23.2M124.7 132.4h23.2M124.7 132.3h23.2M124.7 132.2h23.2M124.7 132.1h23.2"/>
<path d="M124.7 132h23.2M124.7 131.9h23.2M124.7 131.8h23.2M124.7 131.7h23.2M124.7 131.6h23.2M124.7 131.5h23.2M124.7 131.4h23.2M124.7 131.3h23.2M124.7 131.2h23.2M124.7 131.1h23.2M124.7 131h23.2M124.7 130.9h23.2"/>
<path d="M124.7 130.8h23.2M124.7 130.7h23.2M124.7 130.6h23.2M124.7 130.5h23.2M124.7 130.4h23.2M124.7 130.3h23.2M124.7 130.2h23.2M124.7 130.1h23.2M124.7 130h23.2M124.7 129.9h23.2M124.7 129.8h23.2M124.7 129.7h23.2"/>
<path d="M124.7 129.6h23.2M124.7 129.5h23.2M124.7 129.4h23.2M124.7 129.3h23.2M124.7 129.2h23.2M124.7 129.1h23.2M124.7 129h23.2M124.7 128.9h23.2M124.7 128.8h23.2M124.7 128.7h23.2M124.7 128.6h23.2M124.7 128.5h23.2"/>
<path d="M124.7 128.4h23.2M124.7 128.3h23.2M124.7 128.2h23.2M124.7 128.1h23.2M124.7 128h23.2M124.7 127.9h23.2M124.7 127.8h23.2M124.7 127.7h23.2M124.7 127.6h23.2M124.7 127.5h23.2M124.7 127.4h23.2M124.7 127.3h23.2"/>
<path d="M124.7 127.2h23.2M124.7 127.1h23.2M124.7 127h23.2M124.7 126.9h23.2M124.7 126.8h23.2M124.7 126.7h23.2M124.7 126.6h23.2M124.7 126.5h23.2M124.7 126.4h23.2M124.7 126.3h23.2M124.7 126.2h23.2M124.7 126.1h23.2"/>
<path d="M124.7 126h23.2M124.7 125.9h23.2M124.7 125.8h23.2M124.7 125.7h23.2M124.7 125.6h23.2M124.7 125.5h23.2M124.7 125.4h23.2M124.7 125.3h23.2M124.7 125.2h23.2M124.7 125.1h23.2M124.7 125h23.2M124.7 124.9h23.2"/>
<path d="M124.7 124.8h23.2M124.7 124.7h23.2M124.7 124.6h23.2M124.7 124.5h23.2M124.7 124.4h23.2M124.7 124.3h23.2M124.7 124.2h23.2M124.7 124.1h23.2M124.7 124h23.2M124.7 123.9h23.2M124.7 123.8h23.2M124.7 123.7h23.2"/>
<path d="M124.7 123.6h23.2M124.7 123.5h23.2M124.7 123.4h23.2M124.7 123.3h23.2M124.7 123.2h23.2M124.7 123.1h23.2M124.7 123h23.2M124.7 122.9h23.2M124.7 122.8h23.2M124.7 122.7h23.2M124.7 122.6h23.2M124.7 122.5h23.2"/>
<path d="M124.7 122.4h23.2M124.7 122.3h23.2M124.7 122.2h23.2M124.7 122.1h23.2M124.7 122h23.2M124.7 121.9h23.2M124.7 121.8h23.2M124.7 121.7h23.2M124.7 121.6h23.2M124.7 121.5h23.2M124.7 121.4h23.2M124.7 121.3h23.2"/>
<path d="M124.7 121.2h23.2M124.7 121.1h23.2M124.7 121h23.2M124.7 120.9h23.2M124.7 120.8h23.2M124.7 120.7h23.2M124.7 120.6h23.2M124.7 120.5h23.2M124.7 120.4h23.2M124.7 120.3h23.2M124.7 120.2h23.2M124.7 120.1h23.2"/>
<path d="M145.4 136v.3M147.9 134.4v.6M147.9 135l.2 .5M148.1 135.5l.2 .5M148.3 136l.2 .5M148.5 136.5l.3 .4a3.8 3.8 0 0 0 2.9 1.3M153 128.4h43.2M153 128.3h43.2M153 128.2h43.2M153 128.1h43.2M153 128h43.2M153 127.9h43.2"/>
<path d="M153 127.8h43.2M153 127.7h43.2M153 127.6h43.2M153 127.5h43.2M153 127.4h43.2M153 127.3h43.2M153 127.2h43.2M153 127.1h43.2M153 127h43.2M153 126.9h43.2M153 126.8h43.2M153 126.7h43.2"/>
<path d="M153 126.6h43.2M153 126.5h43.2M153 126.4h43.2M153 126.3h43.2M153 126.2h43.2M153 126.1h43.2M153 126h43.2M153 125.9h43.2M153 125.8h43.2M153 125.7h43.2M153 125.6h43.2M153 125.5h43.2"/>
<path d="M153 125.4h43.2M153 125.3h43.2M153 125.2h43.2M153 125.1h43.2M153 125h43.2M153 124.9h43.2M153 124.8h43.2M153 124.7h43.2M153 124.6h43.2M153 124.5h43.2M153 124.4h43.2M153 124.3h43.2"/>
<path d="M153 124.2h43.2M153 124.1h43.2M153 124h43.2M153 123.9h43.2M153 123.8h43.2M153 123.7h43.2M153 123.6h43.2M153 123.5h43.2M153 123.4h43.2M153 123.3h43.2M153 123.2h43.2M153 123.1h43.2"/>
<path d="M153 123h43.2M153 122.9h43.2M153 122.8h43.2M153 122.7h43.2M153 122.6h43.2M153 122.5h43.2M153 122.4h43.2M153 122.3h43.2M153 122.2h43.2M153 122.1h43.2M153 122h43.2M153 121.9h43.2"/>
<path d="M153 121.8h43.2M153 121.7h43.2M153 121.6h43.2M153 121.5h43.2M153 121.4h43.2M153 121.3h43.2M153 121.2h43.2M153 121.1h43.2M153 121h43.2M153 120.9l43.2 .1M153 120.9h43.1M153 120.8h43.1"/>
<path d="M153 120.7h43.1M153 120.8v7.6M153 128.4l.1 .7M153 128.7h43.1M153 128.6h43.1M153 128.5h43.1M153 128.5h43.2M153 120.6h43.1M153 120.5h43.1M153 120.4h43.1M153 128.8h43.1M153 120.3h43"/>
<path d="M153 120.4v.4M153 128.9h43.1M153 120.2l43 .1M153 120.2h43M153.1 129h43M153.1 120.1l42.9 .1M153.1 120.1h42.9M153.1 129.1h42.9M153.1 129.1h43M153.1 120l42.9 .1M153.1 129.1l.1 .3M153.1 120.1l-.1 .3"/>
<path d="M153.1 129.2h42.9M153.1 129.3h42.9M153.2 129.3h42.8M153.2 129.4h42.7M153.2 129.4l.4 .6M153.2 129.5h42.7M153.3 129.6h42.5M153.4 129.7h42.4M153.4 129.8h42.3M153.5 129.9h42.1M153.6 130h42M153.6 130h41.9"/>
<path d="M153.6 130l1.2 .8M153.6 130.1h41.9M153.7 130.2h41.7M153.8 130.2h41.5M153.8 130.3h41.5M153.9 130.3h41.3M153.9 130.4h41.3M154 130.4h41.1M154.1 130.5h41M154.2 130.5h40.7M154.3 130.6h40.5M154.4 130.6h40.4"/>
<path d="M154.5 130.7h40.1M154.6 130.7h39.9M154.7 130.8h39.7M154.8 130.8l.7 .1M155 130.9h39.2M155.4 130.9h38.3M195.5 130l-.8 .7-1.1 .2M195.7 129.8l-.2 .2M196 129.1l-.3 .7M196.1 128.9l-43 .1M196.1 120.7l.1 .4M196.1 128.7l-.1 .4"/>
<path d="M196.2 121.1v7.3M196.2 128.4l-.1 .3M201.2 128.5h24.7M201.2 128.4h24.7M201.2 128.3h24.7M201.2 128.2h24.7M201.2 128.1h24.7M201.2 128h24.7M201.2 127.9h24.7M201.2 127.8h24.7M201.2 127.7h24.7M201.2 127.6h24.7"/>
<path d="M201.2 127.5h24.7M201.2 127.4h24.7M201.2 127.3h24.7M201.2 127.2h24.7M201.2 127.1h24.7M201.2 127h24.7M201.2 126.9h24.7M201.2 126.8h24.7M201.2 126.7h24.7M201.2 126.6h24.7M201.2 126.5h24.7M201.2 126.4h24.7"/>
<path d="M201.2 126.3h24.7M201.2 126.2h24.7M201.2 126.1h24.7M201.2 126h24.7M201.2 125.9h24.7M201.2 125.8h24.7M201.2 125.7h24.7M201.2 125.6h24.7M201.2 125.5h24.7M201.2 125.4h24.7M201.2 125.3h24.7M201.2 125.2h24.7"/>
<path d="M201.2 125.1h24.7M201.2 125h24.7M201.2 124.9h24.7M201.2 124.8h24.7M201.2 124.7h24.7M201.2 124.6h24.7M201.2 124.5h24.7M201.2 124.4h24.7M201.2 124.3h24.7M201.2 124.2h24.7M201.2 124.1h24.7M201.2 124h24.7"/>
<path d="M201.2 123.9h24.7M201.2 123.8h24.7M201.2 123.7h24.7M201.2 123.6h24.7M201.2 123.5h24.7M201.2 123.4h24.7M201.2 123.3h24.7M201.2 123.2h24.7M201.2 123.1h24.7M201.2 123h24.7M201.2 122.9h24.7M201.2 122.8h24.7"/>
<path d="M201.2 122.7h24.7M201.2 122.6h24.7M201.2 122.5h24.7M201.2 122.4h24.7M201.2 122.3h24.7M201.2 122.2h24.7M201.2 122.1h24.7M201.2 122h24.7M201.2 121.9h24.7M201.2 121.8h24.7M201.2 121.7h24.7M201.2 121.6h24.7"/>
<path d="M201.2 121.5h24.7M201.2 121.4h24.7M201.2 121.3h24.7M201.2 121.2h24.7M201.2 121.1h24.7M201.2 121h24.7M201.2 120.9h24.7M201.2 120.8h24.7M201.2 120.7h24.7M201.2 120.6h24.7M201.2 120.5h24.7M201.2 120.4h24.7"/>
<path d="M201.2 120.3h24.7M201.2 120.2h24.7M201.2 120.1h24.7M201.2 128.4l.1 .3M201.3 128.8h24.6M201.3 128.7h24.6M201.3 128.6h24.6M201.3 128.7v.4M201.3 128.9h24.6M201.3 129.1h24.6M201.3 129h24.6M201.3 129.1l.3 .7"/>
<path d="M201.4 129.2h24.5M201.4 129.3h24.5M201.4 129.4h24.5M201.5 129.5h24.4M201.5 129.6h24.4M201.6 129.7h24.3M201.6 129.8l.2 .2M201.7 129.8h24.2M201.7 129.9h24.2M201.8 129.9h24.1M201.8 130h24.1M201.8 130l.9 .7 1.1 .2"/>
<path d="M201.9 130.1h24M202 130.2h23.9M202.1 130.3h23.8M202.2 130.4h23.7M202.3 130.4h23.6M202.3 130.5h23.6M202.4 130.5h23.5M202.5 130.6h23.4M202.6 130.6h23.3M202.7 130.7h23.2M202.8 130.7h23.1M203 130.8h22.9"/>
<path d="M203.2 130.9h22.7M68 148.9h15.1M68 148.8h15.1M68 148.7h15.1M68 149.1h15.1M68 149.4h15.1M68 150h15.1M68 149.7h15.1M68 150.3h15.1M68 151.2h15.1M68 148.6h15.1M68 151.4h15.1"/>
<path d="M68 151.3h15.1M68 151.1h15.1M68 151h15.1M68 150.9h15.1M68 150.8h15.1M68 150.7h15.1M68 150.6h15.1M68 150.5h15.1M68 150.4h15.1M68 150.2h15.1M68 150.1h15.1M68 149.9h15.1"/>
<path d="M68 149.8h15.1M68 149.6h15.1M68 149.5h15.1M68 149.3h15.1M68 149.2h15.1M68 149h15.1M68 148.5l4.9 .1M68 148.5h4.7M68 148.4l4.5 .1M68 148.4h4.3M68 148.3l4.3 .1M68 148.3h4.2"/>
<path d="M68 148.2l4.1 .1M68 148.2h4M68 148.1l3.9 .1M68 148.1h3.8M68 148h3.8M68 148h3.7M68 147.9l3.6 .1M68 147.9h3.6M68 147.8h3.6M68 147.8h3.5M68 147.7h3.4M68 147.6h3.3"/>
<path d="M68 147.5h3.3M68 147.4l3.2 .1M68 147.4h3.2M68 147.3h3.2M68 147.3h3.1M68 147.2l3.1 .1M68 147.2h3.1M68 147.1l3.1 .1M68 147.1h3M68 147h3M68 146.9h3M68 146.8h2.9"/>
<path d="M68 146.7h2.9M68 146.6l2.9 .1M68 146.6h2.9M68 146.5l2.9 .1M68 146.5h2.8M68 146.4h2.8M68 146.3h2.8M68 146.2h2.8M68 146.1h2.8M68 146h2.8M68 145.9h2.8M68 145.8h2.8"/>
<path d="M68 145.7h2.8M68 145.6h2.8M68 145.5h2.8M68 145.4h2.9M68 145.3h2.9M68 145.2h2.9M68 145.1h3M68 145h3M68 144.8h3.1M68 144.7h3.1M68 144.6h3.2M68 144.5h3.3"/>
<path d="M68 144.2h3.6M68 143.3h15.1M68 143.2h15.1M68 143.1h15.1M68 143h15.1M68 142.9h15.1M68 142.8h15.1M68 142.7h15.1M68 142.6h15.1M68 142.5h15.1M68 142.4h15.1M68 142.3h15.1"/>
<path d="M68 142.2h15.1M68 142.1h15.1M68 142h15.1M68 141.9h15.1M68 141.8h15.1M68 141.7h15.1M68 141.6h15.1M68 141.5h15.1M68 141.4h15.1M68 141.3h15.1M68 141.2h15.1M68 141.1h15.1"/>
<path d="M68 141h15.1M68 140.9h15.1M68 140.8h15.1M68 140.7h15.1M68 140.6h15.1M68 140.5h15.1M68 140.4h15.1M68 140.3h15.1M68 140.2h15.1M68 140.1h15.1M70.8 145.7v.7M70.8 146.4l.2 .6"/>
<path d="M70.8 145.6h-2.8M70.9 145.4l-2.9 .1M70.9 145.3h-2.9M71 145.1h-3M71 147l.3 .6M71 144.9l-3 .1M71 144.9h-3M71.1 144.8l-3.1 .1M71.1 144.7l-3.1 .1M71.2 144.6l-3.2 .1M71.2 144.5h-3.2M71.3 144.4h-3.3"/>
<path d="M71.3 144.4l-.5 1.3M71.3 147.6l.5 .5 1.3 .5M71.4 144.4h-3.4M71.4 144.3l-3.4 .1M71.5 144.3h-3.5M71.5 144.2h-3.5M71.6 144.1h-3.6M71.7 144.1h-3.7M71.7 144h-3.7M71.8 144h-3.8M71.9 143.9h-3.9M71.9 143.8l-3.9 .1"/>
<path d="M72 143.8h-4M72.1 143.7l-4.1 .1M72.2 143.7h-4.2M72.3 143.6l-4.3 .1M72.4 143.6h-4.4M72.5 143.5l-4.5 .1M72.8 143.5h-4.8M72.9 143.4h-4.9M73.1 143.4l-.7 .2-1.1 .8M73.8 143.4a2.67 2.67 0 0 1 2.3 2.3M73.9 148.6h9.2M73.9 143.4h9.2"/>
<path d="M74.1 143.5h9M74.2 148.5h8.9M74.3 148.5h8.8M74.3 143.5h8.8M74.4 143.6h8.7M74.5 148.4h8.6M74.5 143.6h8.6M74.6 148.4h8.5M74.6 143.7h8.5M74.7 148.3h8.4M74.8 148.3h8.3M74.8 143.7h8.3"/>
<path d="M74.8 143.8h8.3M74.9 148.2h8.2M74.9 143.8h8.2M75 143.9h8.1M75 148.1h8.1M75.1 144h8M75.1 148h8M75.2 148h7.9M75.2 144.1h7.9M75.3 147.9h7.8M75.3 147.8h7.8M75.3 144.2h7.8"/>
<path d="M75.4 147.8h7.7M75.4 144.3h7.7M75.4 147.7h7.7M75.5 147.7h7.6M75.5 144.4h7.6M75.5 147.6h7.6M75.5 147.6l-.5 .5-1.2 .5M75.6 147.6h7.5M75.6 147.5h7.5M75.6 144.5h7.5M75.6 144.6h7.5M75.6 147.4h7.5"/>
<path d="M75.7 147.4h7.4M75.7 144.6h7.4M75.7 144.7h7.4M75.7 147.3h7.4M75.8 147.2h7.3M75.8 144.8h7.3M75.8 147.1h7.3M75.8 144.9h7.3M75.9 147h7.2M75.9 145.1h7.2M75.9 145h7.2M75.9 146.9h7.2"/>
<path d="M75.9 146.8h7.2M75.9 145.2h7.2M75.9 146.7h7.2M75.9 145.3h7.2M76 146.6h7.1M76 145.4h7.1M76 145.3h7.1M76 146.5h7.1M76 145.5h7.1M76 146.4h7.1M76 145.6h7.1M76.1 146.3h7"/>
<path d="M76.1 146.2h7M76.1 146.1h7M76.1 146h7M76.1 145.9h7M76.1 145.8h7M76.1 145.7h7M76.1 145.6h7M76.1 145.7v.7M76.1 146.4l-.6 1.2M83.1 143.4h-15.1M87 151.2h1.9M87 143.4h10.1"/>
<path d="M87 148.6h10.1M87 151.4h1.8M87 151.3h1.8M87 151.1h1.9M87 151h1.9M87 150.9h1.9M87 150.8h1.9M87 150.7h1.9M87 150.7h2M87 150.6h2M87 150.3h2.1M87 149.6h2.6"/>
<path d="M87 148.5h10.1M87 148.4h10.1M87 148.3h10.1M87 148.2h10.1M87 148.1h10.1M87 148h10.1M87 147.9h10.1M87 147.8h10.1M87 147.7h10.1M87 147.6h10.1M87 147.5h10.1M87 147.4h10.1"/>
<path d="M87 147.3h10.1M87 147.2h10.1M87 147.1h10.1M87 147h10.1M87 146.9h10.1M87 146.8h10.1M87 146.7h10.1M87 146.6h10.1M87 146.5h10.1M87 146.4h10.1M87 146.3h10.1M87 146.2h10.1"/>
<path d="M87 146.1h10.1M87 146h10.1M87 145.9h10.1M87 145.8h10.1M87 145.7h10.1M87 145.6h10.1M87 145.5h10.1M87 145.4h10.1M87 145.3h10.1M87 145.2h10.1M87 145.1h10.1M87 145h10.1"/>
<path d="M87 144.9h10.1M87 144.8h10.1M87 144.7h10.1M87 144.6h10.1M87 144.5h10.1M87 144.4h10.1M87 144.3h10.1M87 144.2h10.1M87 144.1h10.1M87 144h10.1M87 143.9h10.1M87 143.8h10.1"/>
<path d="M87 143.7h10.1M87 143.6h10.1M87 143.5h10.1M87 143.3h10.1M87 143.2h10.1M87 143.1h10.1M87 143h10.1M87 142.9h10.1M87 142.8h10.1M87 142.7h10.1M87 142.6h10.1M87 142.5h10.1"/>
<path d="M87 142.4h10.1M87 142.3h10.1M87 142.2h10.1M87 142.1h10.1M87 142h10.1M87 141.9h10.1M87 141.8h10.1M87 141.7h10.1M87 141.6h10.1M87 141.5h10.1M87 141.4h10.1M87 141.3h10.1"/>
<path d="M87 141.2h10.1M87 141.1h10.1M87 141h10.1M87 140.9h10.1M87 140.8h10.1M87 140.7h10.1M87 140.6h10.1M87 140.5h10.1M87 140.4h10.1M87 140.3h10.1M87 140.2h10.1M87 140.1h10.1"/>
<path d="M88.9 151.3h-1.9M88.9 151.1v.1M88.9 151l-1.9 .1M88.9 150.8h-1.9M88.9 150.7h.1M88.9 150.7v.4M89 150.6l-2 .1M89 150.5l-2 .1M89 150.5h-2M89.1 150.4l-2.1 .1M89.1 150.4h-2.1M89.1 150.3v.1"/>
<path d="M89.1 150.4l-.2 .3M89.1 150.3h-2.1M89.2 150.2h-2.2M89.2 150.1h-2.2M89.3 150.1h-2.3M89.3 150h.1M89.3 150l-.2 .3M89.3 150h-2.3M89.3 149.9l-2.3 .1M89.4 149.9h-2.4M89.4 149.8l-2.4 .1M89.5 149.8h-2.5"/>
<path d="M89.5 149.7l-2.5 .1M89.5 149.7h-2.5M89.5 149.7h.1M89.5 149.7l-.2 .3M89.6 149.6h-2.6M89.7 149.5h-2.7M89.8 149.4h-2.8M89.9 149.4l-.4 .3M89.9 149.4h-2.9M90 149.3h-3M90 149.2l-3 .1M90.1 149.2h-3.1"/>
<path d="M90.1 149.1l-3.1 .1M90.3 149.1h-3.3M90.3 149l-3.3 .1M90.5 149h-3.5M90.5 148.9l-.7 .5M90.5 148.9h.1M90.5 148.9h-3.5M90.7 148.9h-3.7M90.8 148.8h-3.8M90.9 148.8h.1M90.9 148.8l-.4 .1M91 148.8h-4"/>
<path d="M91.3 148.7h-4.3M91.3 148.7l-.4 .1M91.7 148.7h.1M91.7 148.7h-.4M92.4 148.7h.4M92.8 148.7h4.3M92.8 148.7l.4 .1M93 148.8h4.1M93.2 148.8l.3 .1M93.2 148.8h.1M93.3 148.8h3.8M93.3 148.9h3.8"/>
<path d="M93.5 148.9h3.6M93.5 148.9h.1M93.6 148.9l.3 .3M93.6 149h3.5M93.7 149h3.4M93.8 149.1h3.3M93.9 149.1h3.2M93.9 149.1l.7 .6M94 149.2h3.1M94.1 149.2h3M94.1 149.3h3M94.2 149.4h2.9"/>
<path d="M94.3 149.4h2.8M94.3 149.5h2.8M94.4 149.5h2.7M94.4 149.6h2.7M94.5 149.7h2.6M94.5 149.7l.3 .3M94.6 149.7h2.5M94.6 149.8h2.5M94.7 149.8h2.4M94.7 149.9h2.4M94.8 150h2.3M94.8 150h.1"/>
<path d="M94.8 150l.1 .3h2.2M94.8 150.1h2.3M94.9 150.2h2.2M94.9 150.3h2.2M95 150.4h2.1M95 150.3v.1M95 150.4l.1 .3M95 150.4h.1M95 150.5h2.1M95.1 150.6h2M95.1 150.7h2M95.1 150.7l.1 .4"/>
<path d="M95.1 150.7h.1M95.1 150.8h2M95.1 150.9h2M95.2 151h1.9M95.2 151.2h1.9M95.2 151.4h1.9M95.2 151.3h1.9M95.2 151.1v.1M95.2 151.2h.1M97.1 148.7h-10.1M97.1 151.1h-1.9M97.1 150.7h-2"/>
<path d="M97.1 149.6l-2.6 .1M100.9 148.9h13.7M100.9 148.8h13.7M100.9 148.7h13.7M100.9 149.1h13.7M100.9 149.4h13.7M100.9 150h13.7M100.9 149.7h13.7M100.9 150.3h13.7M100.9 151.2h13.7M100.9 148.6h13.7M100.9 151.4h13.7"/>
<path d="M100.9 151.3h13.7M100.9 151.1h13.7M100.9 151h13.7M100.9 150.9h13.7M100.9 150.8h13.7M100.9 150.7h13.7M100.9 150.6h13.7M100.9 150.5h13.7M100.9 150.4h13.7M100.9 150.2h13.7M100.9 150.1h13.7M100.9 149.9h13.7"/>
<path d="M100.9 149.8h13.7M100.9 149.6h13.7M100.9 149.5h13.7M100.9 149.3h13.7M100.9 149.2h13.7M100.9 149h13.7M100.9 148.5l9.1 .1M100.9 148.5h8.9M100.9 148.4l8.8 .1M100.9 148.4h8.6M100.9 148.3l8.5 .1M100.9 148.3h8.4"/>
<path d="M100.9 148.2l8.3 .1M100.9 148.2h8.2M100.9 148.1l8.2 .1M100.9 148.1h8M100.9 148l8 .1M100.9 148h7.9M100.9 147.9l7.9 .1M100.9 147.9h7.8M100.9 147.8h7.8M100.9 147.8h7.7M100.9 147.7h7.7M100.9 147.7h7.6"/>
<path d="M100.9 147.6h7.6M100.9 147.6h7.5M100.9 147.5h7.5M100.9 147.4h7.5M100.9 147.3h7.4M100.9 147.2h7.3M100.9 147.1l7.3 .1M100.9 147.1h7.3M100.9 147h7.2M100.9 146.9h7.2M100.9 146.8h7.2M100.9 146.7l7.2 .1"/>
<path d="M100.9 146.7h7.1M100.9 146.6l7.1 .1M100.9 146.6h7.1M100.9 146.5h7.1M100.9 146.4l7.1 .1M100.9 146.4h7M100.9 146.3l7 .1M100.9 146.3h7M100.9 146.2h7M100.9 146.1h7M100.9 146h7M100.9 145.9h7"/>
<path d="M100.9 145.8h7M100.9 145.7h7M100.9 145.6h7M100.9 145.5h7.1M100.9 145.4h7.1M100.9 145.2h7.2M100.9 145.1h7.2M100.9 144.9h7.3M100.9 144.8h7.3M100.9 143.3h13.7M100.9 143.2h13.7M100.9 143.1h13.7"/>
<path d="M100.9 143h13.7M100.9 142.9h13.7M100.9 142.8h13.7M100.9 142.7h13.7M100.9 142.6h13.7M100.9 142.5h13.7M100.9 142.4h13.7M100.9 142.3h13.7M100.9 142.2h13.7M100.9 142.1h13.7M100.9 142h13.7M100.9 141.9h13.7"/>
<path d="M100.9 141.8h13.7M100.9 141.7h13.7M100.9 141.6h13.7M100.9 141.5h13.7M100.9 141.4h13.7M100.9 141.3h13.7M100.9 141.2h13.7M100.9 141.1h13.7M100.9 141h13.7M100.9 140.9h13.7M100.9 140.8h13.7M100.9 140.7h13.7"/>
<path d="M100.9 140.6h13.7M100.9 140.5h13.7M100.9 140.4h13.7M100.9 140.3h13.7M100.9 140.2h13.7M100.9 140.1h13.7M107.9 145.6l-7 .1M108 145.5h-7.1M108 145.3l-7.1 .1M108.1 145.3h-7.2M108.1 145.2h-7.2M108.1 145h-7.2"/>
<path d="M108.1 145l-.2 .7 .2 1.3M108.1 147a2.54 2.54 0 0 0 2.1 1.6M108.1 144.9l-7.2 .1M108.2 144.8l-7.3 .1M108.3 144.7l-7.4 .1M108.3 144.7h-7.4M108.3 144.6l-7.4 .1M108.4 144.6h-7.5M108.4 144.5h-7.5M108.5 144.4l-7.6 .1M108.5 144.4h-7.6M108.5 144.3l-7.6 .1"/>
<path d="M108.6 144.3h-7.7M108.7 144.2l-7.8 .1M108.7 144.2h-7.8M108.8 144.1h-7.9M108.9 144h-8M109 143.9h-8.1M109.1 143.8l-8.2 .1M109.2 143.8h-8.3M109.2 143.7l-8.3 .1M109.3 143.7h-8.4M109.4 143.6l-8.5 .1M109.5 143.6h-8.6"/>
<path d="M109.7 143.5l-8.8 .1M109.9 143.5h-9M110.1 143.4h-9.2M110.2 143.4a2.64 2.64 0 0 0-2.1 1.6M110.9 143.4l1.3 .5M111.1 143.4h3.5M111.1 148.6h3.5M111.2 143.5h3.4M111.3 148.5h3.3M111.4 143.5h3.2M111.5 148.5h3.1M111.6 143.6h3"/>
<path d="M111.6 148.4h3M111.7 143.6h2.9M111.7 148.4h2.9M111.8 143.7h2.8M111.8 148.3h2.8M111.9 143.7h2.7M111.9 148.3h2.7M112 143.8h2.6M112 148.2h2.6M112.1 148.2h2.5M112.1 143.8h2.5M112.1 143.9h2.5"/>
<path d="M112.2 148.1h2.4M112.2 143.9l.8 1.1M112.2 144h2.4M112.3 144h2.3M112.3 148h2.3M112.3 144.1h2.3M112.4 144.1h2.2M112.4 147.9h2.2M112.4 147.8h2.2M112.4 144.2h2.2M112.5 144.2h2.1M112.5 147.8h2.1"/>
<path d="M112.5 147.7h2.1M112.5 144.3h2.1M112.6 144.3h2M112.6 147.7h2M112.6 147.6h2M112.6 144.4h2M112.7 144.4h1.9M112.7 147.6h1.9M112.7 147.5h1.9M112.7 144.5h1.9M112.8 147.5h1.8M112.8 147.4h1.8"/>
<path d="M112.8 144.6h1.8M112.8 147.3h1.8M112.8 144.7h1.8M112.9 144.7h1.7M112.9 147.3h1.7M112.9 147.2h1.7M112.9 144.8h1.7M112.9 147.1h1.7M113 147.1h1.6M113 144.9h1.6M113 147h1.6M113 145l.2 .7"/>
<path d="M113 147a2.54 2.54 0 0 1-2.1 1.6M113 146.9h1.6M113 145.1h1.6M113 145h1.6M113.1 146.9h1.5M113.1 145.2h1.5M113.1 145.1h1.5M113.1 146.8h1.5M113.1 146.7h1.5M113.1 145.3h1.5M113.1 146.6h1.5M113.1 145.4h1.5"/>
<path d="M113.1 145.5h1.5M113.2 146.5h1.4M113.2 145.5h1.4M113.2 146.4h1.4M113.2 145.6h1.4M113.2 146.3h1.4M113.2 146.2h1.4M113.2 146.1h1.4M113.2 146h1.4M113.2 145.9h1.4M113.2 145.8h1.4M113.2 145.7h1.4"/>
<path d="M113.2 145.7v.7M113.2 146.4l-.2 .6M114.6 143.4h-13.7M124.7 151.2h19.1M124.7 148.6h101.2M124.7 151.4h19.1M124.7 151.3h19.1M124.7 151.1h19.1M124.7 151h19.1M124.7 150.9h19.1M124.7 150.8h19.1M124.7 150.6h19.2"/>
<path d="M124.7 150.5h19.3M124.7 150.4h19.3M124.7 150.1h19.5M124.7 149.9h19.6M124.7 148.5l3.3 .1M124.7 148.5h3M124.7 148.4l2.9 .1M124.7 148.4h2.7M124.7 148.3l2.6 .1M124.7 148.3h2.5M124.7 148.2l2.4 .1M124.7 148.2h2.3"/>
<path d="M124.7 148.1l2.3 .1M124.7 148.1h2.2M124.7 148l2.1 .1M124.7 148h2.1M124.7 147.9l2 .1M124.7 147.9h2M124.7 147.8h1.9M124.7 147.7h1.8M124.7 147.7h1.7M124.7 147.6h1.7M124.7 147.5h1.6M124.7 147.4l1.6 .1"/>
<path d="M124.7 147.4h1.6M124.7 147.3h1.5M124.7 147.2l1.5 .1M124.7 147.2h1.5M124.7 147.1h1.4M124.7 147h1.3M124.7 146.9h1.3M124.7 146.8h1.3M124.7 146.7l1.3 .1M124.7 146.7h1.3M124.7 146.6h1.2M124.7 146.5l1.2 .1"/>
<path d="M124.7 146.5h1.2M124.7 146.4l1.2 .1M124.7 146.4h1.2M124.7 146.3h1.2M124.7 146.2h1.2M124.7 146.1h1.2M124.7 146h1.2M124.7 145.9h1.2M124.7 145.8h1.2M124.7 145.7h1.2M124.7 145.6h1.2M124.7 145.4h1.2"/>
<path d="M124.7 145.3h1.2M124.7 145.3h1.3M124.7 145.1h1.3M124.7 145h1.3M124.7 144.5h1.6M124.7 143.3h101.2M124.7 143.2h101.2M124.7 143.1h101.2M124.7 143h101.2M124.7 142.9h101.2M124.7 142.8h101.2M124.7 142.7h101.2"/>
<path d="M124.7 142.6h101.2M124.7 142.5h101.2M124.7 142.4h101.2M124.7 142.3h101.2M124.7 142.2h101.2M124.7 142.1h101.2M124.7 142h101.2M124.7 141.9h101.2M124.7 141.8h101.2M124.7 141.7h101.2M124.7 141.6h101.2M124.7 141.5h101.2"/>
<path d="M124.7 141.4h101.2M124.7 141.3h101.2M124.7 141.2h101.2M124.7 141.1h101.2M124.7 141h101.2M124.7 140.9h101.2M124.7 140.8h101.2M124.7 140.7h101.2M124.7 140.6h101.2M124.7 140.5h101.2M124.7 140.4h101.2M124.7 140.3h101.2"/>
<path d="M124.7 140.2h101.2M124.7 140.1h101.2M125.9 145.7v.7M125.9 146.4l.1 .6M125.9 145.5l-1.2 .1M125.9 145.5h-1.2M125.9 145.4h-1.2M126 145.2h-1.3M126 145.1h-1.3M126 145l-.1 .7M126 147a2.54 2.54 0 0 0 2.1 1.6M126.1 144.9l-1.4 .1"/>
<path d="M126.1 144.9h-1.4M126.1 144.8l-1.4 .1M126.2 144.8h-1.5M126.2 144.7l-1.5 .1M126.2 144.7h-1.5M126.3 144.6l-1.6 .1M126.3 144.6h-1.6M126.3 144.5l-1.6 .1M126.4 144.4l-1.7 .1M126.4 144.4h-1.7M126.5 144.3l-1.8 .1M126.5 144.3h-1.8"/>
<path d="M126.6 144.2l-1.9 .1M126.6 144.2h-1.9M126.7 144.1h-2M126.8 144h-2.1M126.9 143.9l-.9 1.1M126.9 143.9h-2.2M127 143.8l-2.3 .1M127.1 143.8h-2.4M127.2 143.7l-2.5 .1M127.3 143.7h-2.6M127.4 143.6l-2.7 .1M127.5 143.6h-2.8"/>
<path d="M127.6 143.5l-2.9 .1M127.8 143.5h-3.1M128 143.4h-3.3M128.1 143.4l-1.2 .5M128.8 143.4a2.64 2.64 0 0 1 2.1 1.6M129 143.4h36.1M129 148.6h36.1M129.1 143.5h35.9M129.2 148.5h35.7M129.4 143.5h35.3M129.4 148.5h35.3M129.5 143.6h35.1"/>
<path d="M129.6 148.4h35M129.6 143.6h34.9M129.6 148.4h34.9M129.7 143.7h34.7M129.8 148.3h34.6M129.8 148.3h34.5M129.8 143.7h34.5M129.9 143.8h34.3M129.9 148.2h34.3M130 143.8h34.1M130 148.2h34.1M130.1 143.9h34"/>
<path d="M130.1 148.1h33.9M130.1 144h33.9M130.2 148.1h33.8M130.2 148h33.7M130.3 148h33.6M130.3 144.1h33.5M130.3 147.9h33.5M130.4 147.8h33.4M130.4 144.2h33.4M130.4 144.2h33.3M130.4 147.8h33.3M130.5 144.3h33.2"/>
<path d="M130.5 147.7h33.1M130.6 147.6h33M130.6 144.4h32.9M130.6 147.6h32.9M130.6 147.5h32.9M130.6 144.5h32.9M130.7 144.5h32.7M130.7 147.4l32.7 .1M130.7 147.4h32.7M130.7 144.6h32.7M130.7 147.3l32.7 .1M130.8 147.3h32.6"/>
<path d="M130.8 144.7h32.5M130.8 147.2l32.5 .1M130.8 147.2h32.5M130.8 144.8h32.5M130.9 147.2h32.4M130.9 144.8h32.4M130.9 144.9h32.3M130.9 147.1h32.3M130.9 145l.2 .7-.2 1.3M130.9 147a2.54 2.54 0 0 1-2.1 1.6M130.9 147h32.3M130.9 145h32.3"/>
<path d="M131 146.9h32.2M131 146.8h32.1M131 145.2h32.1M131 145.1h32.2M131 146.7h32.1M131 145.3h32.1M131 146.6h32.1M131.1 146.5l32 .1M131.1 146.5h31.9M131.1 145.5h31.9M131.1 145.4h32M131.1 146.4h31.9"/>
<path d="M131.1 145.6h31.9M131.1 146.3h31.9M131.1 146.2h31.9M131.1 146.1h31.9M131.1 146h31.9M131.1 145.9h31.9M131.1 145.8h31.9M131.1 145.7h31.9M143.8 151.1v.1M143.8 151l-19.1 .1M143.8 150.9l-19.1 .1M143.8 150.8l-19.1 .1"/>
<path d="M143.9 150.7v.1M143.9 150.7h.1M143.9 150.7l-.1 .4M143.9 150.7l-19.2 .1M143.9 150.7h-19.2M143.9 150.6h-19.2M144 150.4h.1M144 150.3v.1M144 150.4l-.1 .3M144 150.4h-19.3M144 150.3h-19.3M144.1 150.3h-19.4"/>
<path d="M144.1 150.2h-19.4M144.1 150.1h-19.4M144.2 150h-19.5M144.2 150h.1M144.2 150l-.2 .3M144.3 149.9h-19.6M144.3 149.8l-19.6 .1M144.4 149.8h-19.7M144.4 149.7l-19.7 .1M144.4 149.7h.1M144.4 149.7l-.2 .3M144.5 149.7h-19.8"/>
<path d="M144.5 149.6h-19.8M144.6 149.5h-19.9M144.7 149.5h-20M144.7 149.4h-20M144.7 149.4h.1M144.7 149.4l-.2 .3M144.8 149.4h-20.1M144.9 149.3h-20.2M144.9 149.2l-20.2 .1M145 149.2h-20.3M145.1 149.1v.1M145.1 149.1l-.3 .3"/>
<path d="M145.1 149.1l-20.4 .1M145.2 149.1h-20.5M145.3 149l-20.6 .1M145.4 149h-20.7M145.5 148.9h-20.8M145.5 148.9l-.4 .2M145.6 148.9h-20.9M145.7 148.8h-21M145.8 148.8h.1M145.8 148.8l-.4 .1M145.9 148.8h-21.2M146.2 148.7h-21.5"/>
<path d="M146.2 148.7l-.4 .1M146.7 148.7h-.5M147.3 148.7h.4M147.7 148.7h53.4M147.7 148.7l.4 .1M147.9 148.8h53M148.1 148.8l.3 .1M148.1 148.8h.1M148.2 148.8h52.4M148.3 148.9h52.2M148.4 148.9h52M148.5 148.9h.1"/>
<path d="M148.5 148.9l.3 .3M148.5 149h51.8M148.6 149h51.6M148.7 149.1h51.4M148.8 149.1l.3 .3M148.9 149.2h51M149 149.2h50.8M149 149.3h50.8M149.1 149.4h50.6M149.1 149.4h50.5M149.2 149.4l.3 .3M149.2 149.5h50.4"/>
<path d="M149.3 149.5h50.2M149.3 149.6h50.2M149.4 149.7h50M149.4 149.7h.1M149.5 149.7l.2 .3M149.5 149.7h49.8M149.5 149.8h49.8M149.6 149.8h49.6M149.6 149.9h49.6M149.7 150h49.4M149.7 150l.2 .4M149.7 150h.1"/>
<path d="M149.7 150.1h49.4M149.8 150.2h49.2M149.8 150.3h49.2M149.9 150.3h49.1M149.9 150.4l.1 .3M149.9 150.4h49M149.9 150.5h49M150 150.6h48.8M150 150.7h48.8M150 150.7l.1 .4M150 150.7l.1 .1M150 150.7h.1"/>
<path d="M150.1 150.8h48.7M150.1 150.9h48.6M150.1 151h48.6M150.1 151.2v.3h48.6v-.3M150.1 151.1v.1M150.1 151.2h48.6M150.1 151.3h48.6M150.1 151.1h48.6M150.1 151.4h48.6M163 145.7v.7M163 146.4a2.67 2.67 0 0 0 2.3 2.2M163 145.6h-31.9"/>
<path d="M163.1 145.4h-32.1M163.1 145.3h-32.1M163.2 145.1h-32.2M163.2 144.9l-32.3 .1M163.4 144.7h-32.6M163.6 144.4h-33M163.6 144.3h-33.1M163.9 144.1h-33.6M163.9 144h-33.7M165.3 143.4a2.67 2.67 0 0 0-2.3 2.3M166 143.4l.6 .2 1.1 .8M166.1 148.6h16.6"/>
<path d="M166.1 143.4h16.6M166.3 143.5h16.3M166.4 148.5h16.1M166.5 148.5h15.9M166.5 143.5h15.9M166.6 143.6h15.6M166.7 148.4h15.5M166.8 143.6h15.3M166.8 148.4h15.3M166.9 143.7h15.1M166.9 148.3h15.1M167 148.3h14.9"/>
<path d="M167 143.7h14.9M167 143.8h14.8M167.1 148.2h14.7M167.1 148.2h14.6M167.1 143.8h14.6M167.2 143.9h14.5M167.2 148.1h14.4M167.3 144h14.3M167.3 148h14.3M167.3 144h14.2M167.4 148h14.1M167.4 144.1h14.1"/>
<path d="M167.4 144.1h14M167.5 147.9h13.9M167.5 147.8h13.9M167.5 144.2h13.9M167.5 144.2h13.8M167.6 147.8h13.7M167.6 144.3h13.7M167.6 147.7h13.7M167.6 144.3h13.6M167.7 147.7h13.5M167.7 144.4l.6 1.3M167.7 147.6l-.5 .5-1.2 .5"/>
<path d="M167.7 147.6h13.5M167.7 144.4h13.4M167.8 147.6h13.3M167.8 147.5h13.3M167.8 144.5h13.3M167.8 144.6h13.2M167.9 147.4h13.1M167.9 144.6h13.1M167.9 147.3l13.1 .1M167.9 147.3h13.1M167.9 147.3h13M167.9 144.7h13.1"/>
<path d="M168 147.2h12.9M168 144.8h12.9M168 144.9h12.8M168 147.1h12.8M168.1 147h12.7M168.1 147l-.4 .6M168.1 145.1h12.7M168.1 145h12.7M168.1 146.9h12.7M168.1 146.8h12.6M168.1 145.2h12.6M168.1 146.7h12.6"/>
<path d="M168.1 145.3h12.6M168.2 146.7h12.5M168.2 145.4h12.5M168.2 145.3h12.5M168.2 146.6h12.5M168.2 146.5h12.5M168.2 145.5h12.5M168.2 146.4h12.4M168.2 145.6h12.4M168.3 145.7v.7M168.3 146.4l-.2 .6M168.3 146.4h12.3"/>
<path d="M168.3 146.3h12.3M168.3 146.2h12.3M168.3 146.1h12.3M168.3 146h12.3M168.3 145.9h12.3M168.3 145.8h12.3M168.3 145.7h12.3M168.3 145.6h12.3M180.6 145.7v.7M180.6 146.4l.2 .6M180.8 147l.3 .6M181 144.7h-13.1"/>
<path d="M181.1 144.4l-.5 1.3M181.1 147.6l.5 .5 1.3 .5M181.2 144.4h-13.5M181.6 143.9l-.5 .5M182.9 143.4l-1.3 .5M183.6 143.4l1.2 .5M183.7 148.6h36.2M183.7 143.4h36.2M183.9 143.5h35.8M184 148.5h35.6M184.1 148.5h35.4M184.1 143.5h35.4"/>
<path d="M184.3 143.6h35.1M184.3 148.4h35M184.4 143.6h34.8M184.4 148.4h34.8M184.5 143.7h34.7M184.5 148.3h34.6M184.6 148.3h34.5M184.6 143.7h34.5M184.6 143.8h34.4M184.7 148.2h34.2M184.7 143.8h34.2M184.8 143.9h34"/>
<path d="M184.8 143.9l.5 .5M184.9 148.1h33.9M184.9 144h33.8M184.9 148.1h33.8M185 144h33.7M185 148h33.7M185 148h33.6M185 144.1h33.6M185.1 147.9h33.4M185.1 144.2h33.4M185.1 147.8h33.4M185.2 147.8h33.2"/>
<path d="M185.2 144.3h33.2M185.2 147.7h33.2M185.3 144.3h33.1M185.3 147.7h33M185.3 144.4l.4 .6M185.3 147.6l-.5 .5-1.2 .5M185.3 147.6h33M185.3 144.4h33M185.4 144.4h32.9M185.4 147.6h32.8M185.4 147.5h32.8M185.4 144.5h32.8"/>
<path d="M185.4 147.4h32.8M185.4 144.6h32.8M185.5 147.4h32.7M185.5 144.6h32.6M185.5 147.3h32.6M185.5 144.7h32.6M185.6 147.2h32.4M185.6 144.8h32.5M185.6 144.8h32.4M185.6 144.9h32.4M185.7 147.1h32.3M185.7 147h32.3"/>
<path d="M185.7 144.9h32.3M185.7 145l.2 .7M185.7 147l-.4 .6M185.7 147h32.2M185.7 145h32.2M185.7 146.9h32.2M185.7 145.1h32.2M185.7 146.8h32.2M185.7 145.2h32.2M185.8 146.7h32.1M185.8 145.3h32.1M185.8 145.2h32.1"/>
<path d="M185.8 146.7h32M185.8 145.3h32M185.8 146.6h32M185.8 145.4h32M185.8 146.5h32M185.8 146.4h32M185.8 145.6h32M185.8 145.5h32M185.9 145.7v.7M185.9 146.4l-.2 .6M185.9 146.4h31.9M185.9 146.3h31.9"/>
<path d="M185.9 146.2h31.9M185.9 146.1h31.9M185.9 146h31.9M185.9 145.9h31.9M185.9 145.8h31.9M185.9 145.7h31.9M185.9 145.6h31.9M198.7 151.1v.1M198.8 150.9h-48.7M198.8 150.7v.1M198.8 150.7h.1M198.8 150.7l-.1 .4"/>
<path d="M198.8 150.8h-48.7M198.9 150.4h.1M198.9 150.4l-.1 .3M199.1 150h.1M199.1 150l-.2 .4M199.4 149.7h.1M199.4 149.7l-.3 .3M199.4 149.6l-50 .1M199.6 149.4l-.2 .3M200 149.1h.1M200 149.1l-.3 .3M200 149.1l-51.2 .1"/>
<path d="M200.3 148.9h.1M200.3 148.9l-.3 .2M200.4 148.9h.1M200.7 148.8h.1M200.7 148.8l-.3 .1M201.1 148.7h.5M201.2 148.7l-.5 .1M202.2 148.7h.4M202.6 148.7h.1M202.6 148.7h23.3M202.6 148.7l.4 .1M202.9 148.8h23"/>
<path d="M203 148.8h.1M203 148.8l.4 .1M203.1 148.8h22.8M203.2 148.9h22.7M203.4 148.9h.1M203.4 148.9h22.5M203.4 148.9l.4 .3M203.4 149h22.5M203.6 149h22.3M203.6 149.1h22.3M203.8 149.1l.6 .6M203.8 149.1h22.1"/>
<path d="M203.8 149.2h22.1M203.9 149.2h22M203.9 149.3h22M204 149.4h21.9M204.1 149.4h21.8M204.2 149.5h21.7M204.3 149.6h21.6M204.4 149.7l.2 .3M204.4 149.7h21.5M204.4 149.8h21.5M204.5 149.8h21.4M204.5 149.9h21.4"/>
<path d="M204.6 149.9h21.3M204.6 150h.1M204.6 150h21.3M204.6 150l.2 .4M204.6 150.1h21.3M204.7 150.1h21.2M204.7 150.2h21.2M204.7 150.3h21.2M204.8 150.3h21.1M204.8 150.4l.1 .3M204.8 150.4h21.1M204.9 150.5h21"/>
<path d="M204.9 150.6h21M204.9 150.7h21M204.9 150.7l.1 .4M205 150.8h20.9M205 150.9h20.9M205 151h20.9M205 151.1h20.9M205 151.1v.1M205 151.2h20.9M205 151.4h20.9M205 151.3h20.9M205.1 151.4h20.8"/>
<path d="M217.8 145.7v.7M217.8 146.4l.1 .6M217.8 145.5h-32M217.9 145l-.1 .7M217.9 147l.4 .6M218.3 144.4l-.4 .6M218.3 147.6l.5 .5 1.2 .5M218.8 143.9l-.5 .5M220 143.4l-1.2 .5M220.7 143.4l.7 .2 1.1 .8M220.9 148.6h5M220.9 143.4h5"/>
<path d="M221 143.5h4.9M221.1 148.5h4.8M221.3 143.5h4.6M221.3 148.5h4.6M221.4 143.6h4.5M221.4 148.4h4.5M221.5 143.6h4.4M221.5 148.4h4.4M221.6 143.7h4.3M221.7 148.3h4.2M221.7 143.7h4.2M221.8 143.8h4.1"/>
<path d="M221.8 148.2h4.1M221.9 148.2h4M221.9 143.8h4M222 143.9h3.9M222 148.1h3.9M222 144h3.9M222.1 148h3.8M222.1 144h3.8M222.1 144.1h3.8M222.2 144.1h3.7M222.2 147.9h3.7M222.2 147.8h3.7"/>
<path d="M222.2 144.2h3.7M222.3 144.2h3.6M222.3 147.8h3.6M222.4 144.3h3.5M222.4 147.7h3.5M222.5 147.6h3.4M222.5 144.4h3.4M222.5 144.4l.5 1.3M222.5 147.6l-.5 .5-1.3 .5M222.5 144.5h3.4M222.5 147.5h3.4M222.6 147.5h3.3"/>
<path d="M222.6 144.6h3.3M222.6 147.4h3.3M222.7 147.3h3.2M222.7 144.7h3.2M222.7 147.2h3.2M222.7 144.8h3.2M222.8 147.2h3.1M222.8 147.1h3.1M222.8 144.9h3.1M222.8 147h3.1M222.8 147l-.3 .6M222.8 145.1h3.1"/>
<path d="M222.8 145h3.1M222.9 146.9h3M222.9 145.1h3M222.9 146.8h3M222.9 145.2h3M222.9 146.7h3M222.9 145.3h3M222.9 146.6h3M222.9 145.4h3M223 146.5h2.9M223 145.5h2.9M223 146.4h2.9"/>
<path d="M223 145.6h2.9M223 145.7v.7M223 146.4l-.2 .6M223 146.3h2.9M223 146.2h2.9M223 146.1h2.9M223 146h2.9M223 145.9h2.9M223 145.8h2.9M223 145.7h2.9M225.9 148.7h-101.2M225.9 143.4h-101.2"/>
</g>
<path d="M203.8 63.6v2.3M133.6 90.6v.1M135.8 91.6h.3M133.6 114.4h.1" fill="none" stroke="#000" stroke-width="1"/>
<path d="M213 67.1h5.1M217.1 68.1l1.6-1.6h-6.4l1.6 1.6h3.8l.2 .2M218.6 71.5l-1 1h-3.7l-1.6 1.6h6.4l-1.6-1.6" fill="none" stroke="#000" stroke-width=".76"/>
<g fill="none" stroke="#000" stroke-width="1.5">
<path d="M215.5 73.1l3.7-.7 .8 .8M216.7 72.5l1.1-1h1.6l2.9 2.9h-2.1M219.7 67.3l-1.1 1.1v.6M220 73.2l.6 .6M220 73.2l-.4 .3h-5.7l-.6 .6h-.3M221.1 67.3h-2.2l-1 1M222.2 66.2l-2.8 2.8h-1.6l-1.8-1.9M82.2 84.1l1.5 1.5v1.6l-1 1.1M88.3 83.6l-2 2v1.6l1.8 1.8M82.2 116.3l1.5 1.5v1.6l-1.7 1.7M87.8 116.3l-1.5 1.5v1.6l2 2M96 103.2l1.7 1.7v1.6l-1.5 1.5"/>
<path d="M102.3 102.9l-2 2v1.6l1.8 1.8M131.3 103.8l4.9 .1 .2 .1M136.4 101.2l-.1 .1h-5"/>
</g>
<path d="M133.6 90.6l.5 .5h3.5M137.6 96.2h-3M134.5 108.9l3.1 .1" fill="none" stroke="#000" stroke-width="1.8"/>
<path d="M136.1 89.3a1.6 1.6 0 0 1 1.5 1.6 1.6 1.6 0 0 1-1.4 1.6h-3.2" fill="none" stroke="#000" stroke-width="1.9"/>
<circle cx="134.6" cy="101.3" r=".76" fill="#000"/>
<path d="M73.6 51.2h-7.9v8M221.2 51.2h7v7M65.7 144.6v9.2h7.9M228.2 146.2v7.6h-7.3" fill="none" stroke="#000" stroke-width="2.5"/>
<circle cx="145.4" cy="76.3" r="2.31" fill="#000" stroke="#000" stroke-width=".21"/>
<circle cx="145.4" cy="76.3" r=".99" fill="#fff" stroke="#000" stroke-width=".21"/>
<circle cx="155.5" cy="76.3" r="2.5" fill="#000" stroke="#000" stroke-width=".21"/>
<circle cx="155.5" cy="76.3" r=".99" fill="#fff" stroke="#000" stroke-width=".21"/>
<circle cx="145.4" cy="102.4" r="2.31" fill="#000" stroke="#000" stroke-width=".21"/>
<circle cx="145.4" cy="102.4" r=".99" fill="#fff" stroke="#000" stroke-width=".21"/>
<circle cx="155.5" cy="102.4" r="2.5" fill="#000" stroke="#000" stroke-width=".21"/>
<circle cx="155.5" cy="102.4" r=".99" fill="#fff" stroke="#000" stroke-width=".21"/>
<circle cx="145.4" cy="128.4" r="2.31" fill="#000" stroke="#000" stroke-width=".21"/>
<circle cx="145.4" cy="128.4" r=".99" fill="#fff" stroke="#000" stroke-width=".21"/>
<circle cx="155.5" cy="128.4" r="2.5" fill="#000" stroke="#000" stroke-width=".21"/>
<circle cx="155.5" cy="128.4" r=".99" fill="#fff" stroke="#000" stroke-width=".21"/>
<circle cx="193.6" cy="76.3" r="2.31" fill="#000" stroke="#000" stroke-width=".21"/>
<circle cx="193.6" cy="76.3" r=".99" fill="#fff" stroke="#000" stroke-width=".21"/>
<circle cx="203.8" cy="76.3" r="2.5" fill="#000" stroke="#000" stroke-width=".21"/>
<circle cx="203.8" cy="76.3" r=".99" fill="#fff" stroke="#000" stroke-width=".21"/>
<circle cx="193.6" cy="102.4" r="2.31" fill="#000" stroke="#000" stroke-width=".21"/>
<circle cx="193.6" cy="102.4" r=".99" fill="#fff" stroke="#000" stroke-width=".21"/>
<circle cx="203.8" cy="102.4" r="2.5" fill="#000" stroke="#000" stroke-width=".21"/>
<circle cx="203.8" cy="102.4" r=".99" fill="#fff" stroke="#000" stroke-width=".21"/>
<circle cx="193.6" cy="128.4" r="2.31" fill="#000" stroke="#000" stroke-width=".21"/>
<circle cx="193.6" cy="128.4" r=".99" fill="#fff" stroke="#000" stroke-width=".21"/>
<circle cx="203.8" cy="128.4" r="2.5" fill="#000" stroke="#000" stroke-width=".21"/>
<circle cx="203.8" cy="128.4" r=".99" fill="#fff" stroke="#000" stroke-width=".21"/>
<path d="M132.3 140.8h2.6" fill="none" stroke="#000" stroke-width="2.5"/>
<circle cx="133.6" cy="140.8" r=".55" fill="#fff" stroke="#000" stroke-width=".21"/>
<path d="M127.3 140.8h2.5" fill="none" stroke="#000" stroke-width="2.5"/>
<circle cx="128.6" cy="140.8" r=".55" fill="#fff" stroke="#000" stroke-width=".21"/>
<path d="M93.3 69.3h2.5" fill="none" stroke="#000" stroke-width="2.5"/>
<circle cx="94.5" cy="69.3" r=".55" fill="#fff" stroke="#000" stroke-width=".21"/>
<path d="M88.3 69.3h2.5" fill="none" stroke="#000" stroke-width="2.5"/>
<circle cx="89.5" cy="69.3" r=".55" fill="#fff" stroke="#000" stroke-width=".21"/>
<path d="M132.3 119.5h2.6" fill="none" stroke="#000" stroke-width="2.5"/>
<circle cx="133.6" cy="119.5" r=".55" fill="#fff" stroke="#000" stroke-width=".21"/>
<path d="M127.3 119.5h2.5" fill="none" stroke="#000" stroke-width="2.5"/>
<circle cx="128.6" cy="119.5" r=".55" fill="#fff" stroke="#000" stroke-width=".21"/>
<path d="M79 102.5h2.5" fill="none" stroke="#000" stroke-width="2.5"/>
<circle cx="80.2" cy="102.5" r=".66" fill="#fff" stroke="#000" stroke-width=".21"/>
<path d="M74 102.5h2.5" fill="none" stroke="#000" stroke-width="2.5"/>
<circle cx="75.2" cy="102.5" r=".66" fill="#fff" stroke="#000" stroke-width=".21"/>
<path d="M104.1 114.4h2.6" fill="none" stroke="#000" stroke-width="2.5"/>
<circle cx="105.4" cy="114.4" r=".55" fill="#fff" stroke="#000" stroke-width=".21"/>
<path d="M109.1 114.4h2.6" fill="none" stroke="#000" stroke-width="2.5"/>
<circle cx="110.4" cy="114.4" r=".55" fill="#fff" stroke="#000" stroke-width=".21"/>
<path d="M109.1 85.2h2.6" fill="none" stroke="#000" stroke-width="2.5"/>
<circle cx="110.4" cy="85.2" r=".55" fill="#fff" stroke="#000" stroke-width=".21"/>
<path d="M104.1 85.2h2.6" fill="none" stroke="#000" stroke-width="2.5"/>
<circle cx="105.4" cy="85.2" r=".55" fill="#fff" stroke="#000" stroke-width=".21"/>
<path d="M79 115.4h2.5" fill="none" stroke="#000" stroke-width="2.5"/>
<circle cx="80.2" cy="115.4" r=".66" fill="#fff" stroke="#000" stroke-width=".21"/>
<path d="M74 115.4h2.5" fill="none" stroke="#000" stroke-width="2.5"/>
<circle cx="75.2" cy="115.4" r=".66" fill="#fff" stroke="#000" stroke-width=".21"/>
<path d="M88.3 135.7h2.5" fill="none" stroke="#000" stroke-width="2.5"/>
<circle cx="89.5" cy="135.7" r=".55" fill="#fff" stroke="#000" stroke-width=".21"/>
<path d="M93.3 135.7h2.5" fill="none" stroke="#000" stroke-width="2.5"/>
<circle cx="94.5" cy="135.7" r=".55" fill="#fff" stroke="#000" stroke-width=".21"/>
<path d="M132.3 74.7h2.6" fill="none" stroke="#000" stroke-width="2.5"/>
<circle cx="133.6" cy="74.7" r=".55" fill="#fff" stroke="#000" stroke-width=".21"/>
<path d="M127.3 74.7h2.5" fill="none" stroke="#000" stroke-width="2.5"/>
<circle cx="128.6" cy="74.7" r=".55" fill="#fff" stroke="#000" stroke-width=".21"/>
<path d="M132.3 85.2h2.6" fill="none" stroke="#000" stroke-width="2.5"/>
<circle cx="133.6" cy="85.2" r=".55" fill="#fff" stroke="#000" stroke-width=".21"/>
<path d="M127.3 85.2h2.5" fill="none" stroke="#000" stroke-width="2.5"/>
<circle cx="128.6" cy="85.2" r=".55" fill="#fff" stroke="#000" stroke-width=".21"/>
<path d="M132.3 64.3h2.6" fill="none" stroke="#000" stroke-width="2.5"/>
<circle cx="133.6" cy="64.3" r=".55" fill="#fff" stroke="#000" stroke-width=".21"/>
<path d="M127.3 64.3h2.5" fill="none" stroke="#000" stroke-width="2.5"/>
<circle cx="128.6" cy="64.3" r=".55" fill="#fff" stroke="#000" stroke-width=".21"/>
<path d="M132.3 90.6h2.6" fill="none" stroke="#000" stroke-width="2.5"/>
<circle cx="133.6" cy="90.6" r=".55" fill="#fff" stroke="#000" stroke-width=".21"/>
<path d="M127.3 90.6h2.5" fill="none" stroke="#000" stroke-width="2.5"/>
<circle cx="128.6" cy="90.6" r=".55" fill="#fff" stroke="#000" stroke-width=".21"/>
<path d="M132.3 79.8h2.6" fill="none" stroke="#000" stroke-width="2.5"/>
<circle cx="133.6" cy="79.8" r=".55" fill="#fff" stroke="#000" stroke-width=".21"/>
<path d="M127.3 79.8h2.5" fill="none" stroke="#000" stroke-width="2.5"/>
<circle cx="128.6" cy="79.8" r=".55" fill="#fff" stroke="#000" stroke-width=".21"/>
<path d="M93.3 125.2h2.5" fill="none" stroke="#000" stroke-width="2.5"/>
<circle cx="94.5" cy="125.2" r=".55" fill="#fff" stroke="#000" stroke-width=".21"/>
<path d="M88.3 125.2h2.5" fill="none" stroke="#000" stroke-width="2.5"/>
<circle cx="89.5" cy="125.2" r=".55" fill="#fff" stroke="#000" stroke-width=".21"/>
<path d="M132.3 69.3h2.6" fill="none" stroke="#000" stroke-width="2.5"/>
<circle cx="133.6" cy="69.3" r=".55" fill="#fff" stroke="#000" stroke-width=".21"/>
<path d="M127.3 69.3h2.5" fill="none" stroke="#000" stroke-width="2.5"/>
<circle cx="128.6" cy="69.3" r=".55" fill="#fff" stroke="#000" stroke-width=".21"/>
<path d="M212.4 129.6h2.5" fill="none" stroke="#000" stroke-width="2.5"/>
<circle cx="213.7" cy="129.6" r=".66" fill="#fff" stroke="#000" stroke-width=".21"/>
<path d="M217.4 129.6h2.5" fill="none" stroke="#000" stroke-width="2.5"/>
<circle cx="218.7" cy="129.6" r=".66" fill="#fff" stroke="#000" stroke-width=".21"/>
<path d="M79 89.7h2.5" fill="none" stroke="#000" stroke-width="2.5"/>
<circle cx="80.2" cy="89.7" r=".66" fill="#fff" stroke="#000" stroke-width=".21"/>
<path d="M74 89.7h2.5" fill="none" stroke="#000" stroke-width="2.5"/>
<circle cx="75.2" cy="89.7" r=".66" fill="#fff" stroke="#000" stroke-width=".21"/>
<path d="M88.3 79.8h2.5" fill="none" stroke="#000" stroke-width="2.5"/>
<circle cx="89.5" cy="79.8" r=".55" fill="#fff" stroke="#000" stroke-width=".21"/>
<path d="M93.3 79.8h2.5" fill="none" stroke="#000" stroke-width="2.5"/>
<circle cx="94.5" cy="79.8" r=".55" fill="#fff" stroke="#000" stroke-width=".21"/>
<path d="M132.3 124.9h2.6" fill="none" stroke="#000" stroke-width="2.5"/>
<circle cx="133.6" cy="124.9" r=".55" fill="#fff" stroke="#000" stroke-width=".21"/>
<path d="M127.3 124.9h2.5" fill="none" stroke="#000" stroke-width="2.5"/>
<circle cx="128.6" cy="124.9" r=".55" fill="#fff" stroke="#000" stroke-width=".21"/>
<path d="M212.4 139.5h2.5" fill="none" stroke="#000" stroke-width="2.5"/>
<circle cx="213.7" cy="139.5" r=".66" fill="#fff" stroke="#000" stroke-width=".21"/>
<path d="M217.4 139.5h2.5" fill="none" stroke="#000" stroke-width="2.5"/>
<circle cx="218.7" cy="139.5" r=".66" fill="#fff" stroke="#000" stroke-width=".21"/>
<path d="M132.3 130h2.6" fill="none" stroke="#000" stroke-width="2.5"/>
<circle cx="133.6" cy="130" r=".55" fill="#fff" stroke="#000" stroke-width=".21"/>
<path d="M127.3 130h2.5" fill="none" stroke="#000" stroke-width="2.5"/>
<circle cx="128.6" cy="130" r=".55" fill="#fff" stroke="#000" stroke-width=".21"/>
<path d="M132.3 114.4h2.6" fill="none" stroke="#000" stroke-width="2.5"/>
<circle cx="133.6" cy="114.4" r=".55" fill="#fff" stroke="#000" stroke-width=".21"/>
<path d="M127.3 114.4h2.5" fill="none" stroke="#000" stroke-width="2.5"/>
<circle cx="128.6" cy="114.4" r=".55" fill="#fff" stroke="#000" stroke-width=".21"/>
<path d="M132.3 135.4h2.6" fill="none" stroke="#000" stroke-width="2.5"/>
<circle cx="133.6" cy="135.4" r=".55" fill="#fff" stroke="#000" stroke-width=".21"/>
<path d="M127.3 135.4h2.5" fill="none" stroke="#000" stroke-width="2.5"/>
<circle cx="128.6" cy="135.4" r=".55" fill="#fff" stroke="#000" stroke-width=".21"/>
<path d="M93.3 74.7h2.5" fill="none" stroke="#000" stroke-width="2.5"/>
<circle cx="94.5" cy="74.7" r=".55" fill="#fff" stroke="#000" stroke-width=".21"/>
<path d="M88.3 74.7h2.5" fill="none" stroke="#000" stroke-width="2.5"/>
<circle cx="89.5" cy="74.7" r=".55" fill="#fff" stroke="#000" stroke-width=".21"/>
<path d="M93.3 64.3h2.5" fill="none" stroke="#000" stroke-width="2.5"/>
<circle cx="94.5" cy="64.3" r=".55" fill="#fff" stroke="#000" stroke-width=".21"/>
<path d="M88.3 64.3h2.5" fill="none" stroke="#000" stroke-width="2.5"/>
<circle cx="89.5" cy="64.3" r=".55" fill="#fff" stroke="#000" stroke-width=".21"/>
<path d="M104.1 119.5h2.6" fill="none" stroke="#000" stroke-width="2.5"/>
<circle cx="105.4" cy="119.5" r=".55" fill="#fff" stroke="#000" stroke-width=".21"/>
<path d="M109.1 119.5h2.6" fill="none" stroke="#000" stroke-width="2.5"/>
<circle cx="110.4" cy="119.5" r=".55" fill="#fff" stroke="#000" stroke-width=".21"/>
<path d="M104.1 90.6h2.6" fill="none" stroke="#000" stroke-width="2.5"/>
<circle cx="105.4" cy="90.6" r=".55" fill="#fff" stroke="#000" stroke-width=".21"/>
<path d="M109.1 90.6h2.6" fill="none" stroke="#000" stroke-width="2.5"/>
<circle cx="110.4" cy="90.6" r=".55" fill="#fff" stroke="#000" stroke-width=".21"/>
<path d="M93.3 140.8h2.5" fill="none" stroke="#000" stroke-width="2.5"/>
<circle cx="94.5" cy="140.8" r=".55" fill="#fff" stroke="#000" stroke-width=".21"/>
<path d="M88.3 140.8h2.5" fill="none" stroke="#000" stroke-width="2.5"/>
<circle cx="89.5" cy="140.8" r=".55" fill="#fff" stroke="#000" stroke-width=".21"/>
<path d="M93.3 130.3h2.5" fill="none" stroke="#000" stroke-width="2.5"/>
<circle cx="94.5" cy="130.3" r=".55" fill="#fff" stroke="#000" stroke-width=".21"/>
<path d="M88.3 130.3h2.5" fill="none" stroke="#000" stroke-width="2.5"/>
<circle cx="89.5" cy="130.3" r=".55" fill="#fff" stroke="#000" stroke-width=".21"/>
<circle cx="137.6" cy="109" r=".71" fill="#000" stroke="#000" stroke-width=".21"/>
<circle cx="137.6" cy="109" r=".4" fill="#fff" stroke="#000" stroke-width=".21"/>
<circle cx="137.6" cy="114" r=".71" fill="#000" stroke="#000" stroke-width=".21"/>
<circle cx="137.6" cy="114" r=".4" fill="#fff" stroke="#000" stroke-width=".21"/>
<circle cx="134.5" cy="108.9" r=".71" fill="#000" stroke="#000" stroke-width=".21"/>
<circle cx="134.5" cy="108.9" r=".4" fill="#fff" stroke="#000" stroke-width=".21"/>
<circle cx="134.5" cy="103.9" r=".71" fill="#000" stroke="#000" stroke-width=".21"/>
<circle cx="134.5" cy="103.9" r=".4" fill="#fff" stroke="#000" stroke-width=".21"/>
<circle cx="134.6" cy="96.2" r=".71" fill="#000" stroke="#000" stroke-width=".21"/>
<circle cx="134.6" cy="96.2" r=".4" fill="#fff" stroke="#000" stroke-width=".21"/>
<circle cx="134.6" cy="101.3" r=".71" fill="#000" stroke="#000" stroke-width=".21"/>
<circle cx="134.6" cy="101.3" r=".4" fill="#fff" stroke="#000" stroke-width=".21"/>
<circle cx="137.6" cy="96.2" r=".71" fill="#000" stroke="#000" stroke-width=".21"/>
<circle cx="137.6" cy="96.2" r=".4" fill="#fff" stroke="#000" stroke-width=".21"/>
<circle cx="137.6" cy="91.1" r=".71" fill="#000" stroke="#000" stroke-width=".21"/>
<circle cx="137.6" cy="91.1" r=".4" fill="#fff" stroke="#000" stroke-width=".21"/>
<path d="M217.8 71.5h1.6" fill="none" stroke="#000" stroke-width="1.5"/>
<circle cx="218.6" cy="71.5" r=".51" fill="#fff" stroke="#000" stroke-width=".21"/>
<path d="M217.8 69h1.6" fill="none" stroke="#000" stroke-width="1.5"/>
<circle cx="218.6" cy="69" r=".51" fill="#fff" stroke="#000" stroke-width=".21"/>
<path d="M86.3 85.6v1.6" fill="none" stroke="#000" stroke-width="1.5"/>
<circle cx="86.3" cy="86.4" r=".51" fill="#fff" stroke="#000" stroke-width=".21"/>
<path d="M83.7 85.6v1.6" fill="none" stroke="#000" stroke-width="1.5"/>
<circle cx="83.7" cy="86.4" r=".51" fill="#fff" stroke="#000" stroke-width=".21"/>
<path d="M100.3 104.9v1.5" fill="none" stroke="#000" stroke-width="1.5"/>
<circle cx="100.3" cy="105.7" r=".51" fill="#fff" stroke="#000" stroke-width=".21"/>
<path d="M97.7 104.9v1.5" fill="none" stroke="#000" stroke-width="1.5"/>
<circle cx="97.7" cy="105.7" r=".51" fill="#fff" stroke="#000" stroke-width=".21"/>
<path d="M83.7 117.8v1.6" fill="none" stroke="#000" stroke-width="1.5"/>
<circle cx="83.7" cy="118.6" r=".51" fill="#fff" stroke="#000" stroke-width=".21"/>
<path d="M86.3 117.8v1.6" fill="none" stroke="#000" stroke-width="1.5"/>
<circle cx="86.3" cy="118.6" r=".51" fill="#fff" stroke="#000" stroke-width=".21"/>
<path d="M130.6 101.3h1.5" fill="none" stroke="#000" stroke-width="1.5"/>
<circle cx="131.3" cy="101.3" r=".51" fill="#fff" stroke="#000" stroke-width=".21"/>
<path d="M130.6 103.8h1.5" fill="none" stroke="#000" stroke-width="1.5"/>
<circle cx="131.3" cy="103.8" r=".51" fill="#fff" stroke="#000" stroke-width=".21"/>
<g fill="none" stroke="#000" stroke-width=".21">
<path d="M67 52.5h159.9v100h-159.9z"/>
<circle cx="73.4" cy="58.9" r="1.61"/>
</g>
<circle cx="73.4" cy="58.9" r="1.61" fill="#fff" stroke="#000" stroke-width=".21"/>
<circle cx="73.4" cy="96.1" r="1.61" fill="none" stroke="#000" stroke-width=".21"/>
<circle cx="73.4" cy="96.1" r="1.61" fill="#fff" stroke="#000" stroke-width=".21"/>
<circle cx="110.6" cy="58.9" r="1.61" fill="none" stroke="#000" stroke-width=".21"/>
<circle cx="110.6" cy="58.9" r="1.61" fill="#fff" stroke="#000" stroke-width=".21"/>
<circle cx="110.6" cy="96.1" r="1.61" fill="none" stroke="#000" stroke-width=".21"/>
<circle cx="110.6" cy="96.1" r="1.61" fill="#fff" stroke="#000" stroke-width=".21"/>
<circle cx="73.4" cy="108.9" r="1.61" fill="none" stroke="#000" stroke-width=".21"/>
<circle cx="73.4" cy="108.9" r="1.61" fill="#fff" stroke="#000" stroke-width=".21"/>
<circle cx="73.4" cy="146" r="1.61" fill="none" stroke="#000" stroke-width=".21"/>
<circle cx="73.4" cy="146" r="1.61" fill="#fff" stroke="#000" stroke-width=".21"/>
<circle cx="110.6" cy="108.9" r="1.61" fill="none" stroke="#000" stroke-width=".21"/>
<circle cx="110.6" cy="108.9" r="1.61" fill="#fff" stroke="#000" stroke-width=".21"/>
<circle cx="110.6" cy="146" r="1.61" fill="none" stroke="#000" stroke-width=".21"/>
<circle cx="110.6" cy="146" r="1.61" fill="#fff" stroke="#000" stroke-width=".21"/>
<circle cx="183.2" cy="58.9" r="1.61" fill="none" stroke="#000" stroke-width=".21"/>
<circle cx="183.2" cy="58.9" r="1.61" fill="#fff" stroke="#000" stroke-width=".21"/>
<circle cx="183.2" cy="96.1" r="1.61" fill="none" stroke="#000" stroke-width=".21"/>
<circle cx="183.2" cy="96.1" r="1.61" fill="#fff" stroke="#000" stroke-width=".21"/>
<circle cx="220.4" cy="58.9" r="1.61" fill="none" stroke="#000" stroke-width=".21"/>
<circle cx="220.4" cy="58.9" r="1.61" fill="#fff" stroke="#000" stroke-width=".21"/>
<circle cx="220.4" cy="96.1" r="1.61" fill="none" stroke="#000" stroke-width=".21"/>
<circle cx="220.4" cy="96.1" r="1.61" fill="#fff" stroke="#000" stroke-width=".21"/>
<circle cx="183.2" cy="108.9" r="1.61" fill="none" stroke="#000" stroke-width=".21"/>
<circle cx="183.2" cy="108.9" r="1.61" fill="#fff" stroke="#000" stroke-width=".21"/>
<circle cx="183.2" cy="146" r="1.61" fill="none" stroke="#000" stroke-width=".21"/>
<circle cx="183.2" cy="146" r="1.61" fill="#fff" stroke="#000" stroke-width=".21"/>
<circle cx="220.4" cy="108.9" r="1.61" fill="none" stroke="#000" stroke-width=".21"/>
<circle cx="220.4" cy="108.9" r="1.61" fill="#fff" stroke="#000" stroke-width=".21"/>
<circle cx="220.4" cy="146" r="1.61" fill="none" stroke="#000" stroke-width=".21"/>
<circle cx="220.4" cy="146" r="1.61" fill="#fff" stroke="#000" stroke-width=".21"/>
<circle cx="128.5" cy="58.9" r="1.61" fill="none" stroke="#000" stroke-width=".21"/>
<circle cx="128.5" cy="58.9" r="1.61" fill="#fff" stroke="#000" stroke-width=".21"/>
<circle cx="128.5" cy="96.1" r="1.61" fill="none" stroke="#000" stroke-width=".21"/>
<circle cx="128.5" cy="96.1" r="1.61" fill="#fff" stroke="#000" stroke-width=".21"/>
<circle cx="165.6" cy="58.9" r="1.61" fill="none" stroke="#000" stroke-width=".21"/>
<circle cx="165.6" cy="58.9" r="1.61" fill="#fff" stroke="#000" stroke-width=".21"/>
<circle cx="165.6" cy="96.1" r="1.61" fill="none" stroke="#000" stroke-width=".21"/>
<circle cx="165.6" cy="96.1" r="1.61" fill="#fff" stroke="#000" stroke-width=".21"/>
<circle cx="128.5" cy="108.9" r="1.61" fill="none" stroke="#000" stroke-width=".21"/>
<circle cx="128.5" cy="108.9" r="1.61" fill="#fff" stroke="#000" stroke-width=".21"/>
<circle cx="128.5" cy="146" r="1.61" fill="none" stroke="#000" stroke-width=".21"/>
<circle cx="128.5" cy="146" r="1.61" fill="#fff" stroke="#000" stroke-width=".21"/>
<circle cx="165.6" cy="108.9" r="1.61" fill="none" stroke="#000" stroke-width=".21"/>
<circle cx="165.6" cy="108.9" r="1.61" fill="#fff" stroke="#000" stroke-width=".21"/>
<circle cx="165.6" cy="146" r="1.61" fill="none" stroke="#000" stroke-width=".21"/>
<circle cx="165.6" cy="146" r="1.61" fill="#fff" stroke="#000" stroke-width=".21"/>
<g fill="none" stroke="#000" stroke-width=".21">
<path d="M22.5 18.9h252.7v171.4h-252.7zM64.6 15.1v3.8M106.7 15.1v3.8M148.8 15.1v3.8M191 15.1v3.8M233.1 15.1v3.8M18.7 61.7h3.8M275.2 61.7h3.8M18.7 104.6h3.8M275.2 104.6h3.8M18.7 147.4h3.8M275.2 147.4h3.8"/>
<path d="M233.9 170v20.3M233.9 175h41.3M235.9 177.2l.6 1.6 .5-1.6M237.6 177.2h.7M238.3 176.4l-.5 .3v2.1M239.9 176.4v2.4l-.8-.1-.3-.3 .1-1 .3-.2h.7M240.7 179h1M243.4 176.4v2.4l-.8-.1-.2-.2v-1.1l.4-.2h.6M245.2 177.2h-.7l-.2 .4v.9l.4 .3h.5M246 176.4v2.4l.8-.1 .2-.2v-1.1l-.4-.2h-.6M247.8 177.2l.1 1.3 .3 .3h.7v-1.6M250.6 177.3l-.7-.1-.2 .4 1 .6v.4l-.3 .2-.7-.2"/>
<path d="M275.2 170h-95.2v20.3M64.6 190.3v3.8M106.7 190.3v3.8M148.8 190.3v3.8M191 190.3v3.8M233.1 190.3v3.8M233.9 185.2h41.3M233.9 180.1h41.3M235.9 182.2l.6-.5v2.1M235.9 183.8h1.2M239.7 183.7l.1 .1zM240.8 181.9l.1-.1a.86 .86 0 0 1 .8 1.2l-.1 .3a.51 .51 0 0 1-.5 .5 .51 .51 0 0 1-.5-.5v-.8z"/>
<path d="M241.6 182.2l-1 1.2M242.5 182v-.3h1.1l-.6 2.1M244.3 183.7l.2 .1zM245.2 182.2a.58 .58 0 0 1 .8-.4 .58 .58 0 0 1 .1 .9l-.9 1.1h1.1M247.3 181.9l.2-.1a.86 .86 0 0 1 .7 1.2v.3a.51 .51 0 0 1-.6 .5 .51 .51 0 0 1-.5-.5v-.8zM248.1 182.2l-.9 1.2M250 182.2a.58 .58 0 0 1 .8-.4 .58 .58 0 0 1 .2 .9l-1 1.1h1.2M251.9 182.2a.58 .58 0 0 1 .9-.4 .58 .58 0 0 1 .1 .9l-1 1.1h1.2M253.9 182.6l.1 .1zM253.9 183.6l.1 .1zM254.8 181.7h.7a.47 .47 0 0 1 .4 .5 .47 .47 0 0 1-.4 .5h-.5M255.3 182.7a.58 .58 0 0 1 .6 .6 .58 .58 0 0 1-.6 .5h-.5"/>
<path d="M256.7 182v-.3h1.2l-.6 2.1M265 185.2v5.1"/>
<circle cx="238.4" cy="183.3" r=".59"/>
<circle cx="238.4" cy="182.2" r=".46"/>
</g>
<path d="M18.7 15.1h260.3v179h-260.3z" fill="none" stroke="#000" stroke-width=".32"/>
<use href="#words"/>
</svg>
